VERSION 5.7 ;
  NOWIREEXTENSIONATPIN ON ;
  DIVIDERCHAR "/" ;
  BUSBITCHARS "[]" ;
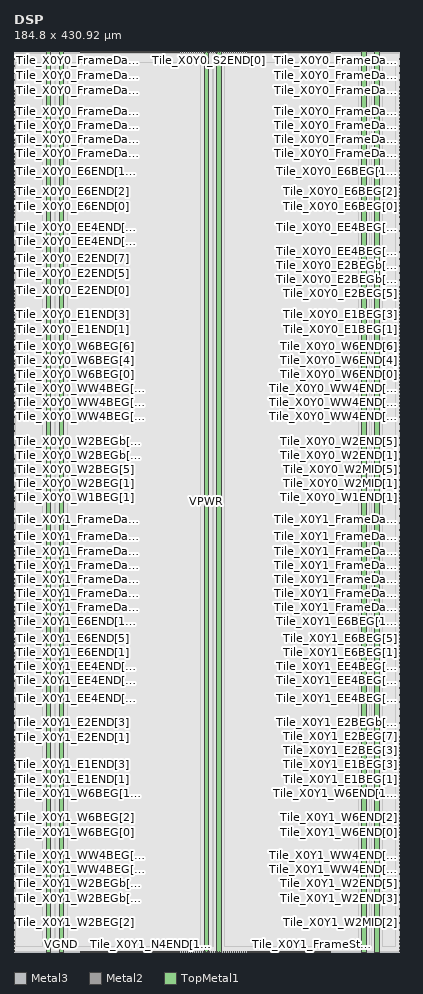
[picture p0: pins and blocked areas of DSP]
MACRO DSP
  CLASS BLOCK ;
  FOREIGN DSP ;
  ORIGIN 0.000 0.000 ;
  SIZE 184.800 BY 430.920 ;
  PIN Tile_X0Y0_E1BEG[0]
    DIRECTION OUTPUT ;
    USE SIGNAL ;
    ANTENNADIFFAREA 0.708600 ;
    PORT
      LAYER Metal3 ;
        RECT 184.400 296.320 184.800 296.720 ;
    END
  END Tile_X0Y0_E1BEG[0]
  PIN Tile_X0Y0_E1BEG[1]
    DIRECTION OUTPUT ;
    USE SIGNAL ;
    ANTENNADIFFAREA 0.708600 ;
    PORT
      LAYER Metal3 ;
        RECT 184.400 298.000 184.800 298.400 ;
    END
  END Tile_X0Y0_E1BEG[1]
  PIN Tile_X0Y0_E1BEG[2]
    DIRECTION OUTPUT ;
    USE SIGNAL ;
    ANTENNADIFFAREA 0.708600 ;
    PORT
      LAYER Metal3 ;
        RECT 184.400 299.680 184.800 300.080 ;
    END
  END Tile_X0Y0_E1BEG[2]
  PIN Tile_X0Y0_E1BEG[3]
    DIRECTION OUTPUT ;
    USE SIGNAL ;
    ANTENNADIFFAREA 0.708600 ;
    PORT
      LAYER Metal3 ;
        RECT 184.400 301.360 184.800 301.760 ;
    END
  END Tile_X0Y0_E1BEG[3]
  PIN Tile_X0Y0_E1END[0]
    DIRECTION INPUT ;
    USE SIGNAL ;
    ANTENNAGATEAREA 0.668200 ;
    PORT
      LAYER Metal3 ;
        RECT 0.000 296.320 0.400 296.720 ;
    END
  END Tile_X0Y0_E1END[0]
  PIN Tile_X0Y0_E1END[1]
    DIRECTION INPUT ;
    USE SIGNAL ;
    ANTENNAGATEAREA 1.834300 ;
    PORT
      LAYER Metal3 ;
        RECT 0.000 298.000 0.400 298.400 ;
    END
  END Tile_X0Y0_E1END[1]
  PIN Tile_X0Y0_E1END[2]
    DIRECTION INPUT ;
    USE SIGNAL ;
    ANTENNAGATEAREA 2.345200 ;
    PORT
      LAYER Metal3 ;
        RECT 0.000 299.680 0.400 300.080 ;
    END
  END Tile_X0Y0_E1END[2]
  PIN Tile_X0Y0_E1END[3]
    DIRECTION INPUT ;
    USE SIGNAL ;
    ANTENNAGATEAREA 1.336400 ;
    PORT
      LAYER Metal3 ;
        RECT 0.000 301.360 0.400 301.760 ;
    END
  END Tile_X0Y0_E1END[3]
  PIN Tile_X0Y0_E2BEG[0]
    DIRECTION OUTPUT ;
    USE SIGNAL ;
    ANTENNADIFFAREA 0.708600 ;
    PORT
      LAYER Metal3 ;
        RECT 184.400 303.040 184.800 303.440 ;
    END
  END Tile_X0Y0_E2BEG[0]
  PIN Tile_X0Y0_E2BEG[1]
    DIRECTION OUTPUT ;
    USE SIGNAL ;
    ANTENNADIFFAREA 0.708600 ;
    PORT
      LAYER Metal3 ;
        RECT 184.400 304.720 184.800 305.120 ;
    END
  END Tile_X0Y0_E2BEG[1]
  PIN Tile_X0Y0_E2BEG[2]
    DIRECTION OUTPUT ;
    USE SIGNAL ;
    ANTENNADIFFAREA 0.708600 ;
    PORT
      LAYER Metal3 ;
        RECT 184.400 306.400 184.800 306.800 ;
    END
  END Tile_X0Y0_E2BEG[2]
  PIN Tile_X0Y0_E2BEG[3]
    DIRECTION OUTPUT ;
    USE SIGNAL ;
    ANTENNADIFFAREA 0.708600 ;
    PORT
      LAYER Metal3 ;
        RECT 184.400 308.080 184.800 308.480 ;
    END
  END Tile_X0Y0_E2BEG[3]
  PIN Tile_X0Y0_E2BEG[4]
    DIRECTION OUTPUT ;
    USE SIGNAL ;
    ANTENNADIFFAREA 0.708600 ;
    PORT
      LAYER Metal3 ;
        RECT 184.400 309.760 184.800 310.160 ;
    END
  END Tile_X0Y0_E2BEG[4]
  PIN Tile_X0Y0_E2BEG[5]
    DIRECTION OUTPUT ;
    USE SIGNAL ;
    ANTENNADIFFAREA 0.708600 ;
    PORT
      LAYER Metal3 ;
        RECT 184.400 311.440 184.800 311.840 ;
    END
  END Tile_X0Y0_E2BEG[5]
  PIN Tile_X0Y0_E2BEG[6]
    DIRECTION OUTPUT ;
    USE SIGNAL ;
    ANTENNADIFFAREA 0.708600 ;
    PORT
      LAYER Metal3 ;
        RECT 184.400 313.120 184.800 313.520 ;
    END
  END Tile_X0Y0_E2BEG[6]
  PIN Tile_X0Y0_E2BEG[7]
    DIRECTION OUTPUT ;
    USE SIGNAL ;
    ANTENNADIFFAREA 0.708600 ;
    PORT
      LAYER Metal3 ;
        RECT 184.400 314.800 184.800 315.200 ;
    END
  END Tile_X0Y0_E2BEG[7]
  PIN Tile_X0Y0_E2BEGb[0]
    DIRECTION OUTPUT ;
    USE SIGNAL ;
    ANTENNADIFFAREA 0.708600 ;
    PORT
      LAYER Metal3 ;
        RECT 184.400 316.480 184.800 316.880 ;
    END
  END Tile_X0Y0_E2BEGb[0]
  PIN Tile_X0Y0_E2BEGb[1]
    DIRECTION OUTPUT ;
    USE SIGNAL ;
    ANTENNADIFFAREA 0.708600 ;
    PORT
      LAYER Metal3 ;
        RECT 184.400 318.160 184.800 318.560 ;
    END
  END Tile_X0Y0_E2BEGb[1]
  PIN Tile_X0Y0_E2BEGb[2]
    DIRECTION OUTPUT ;
    USE SIGNAL ;
    ANTENNADIFFAREA 0.708600 ;
    PORT
      LAYER Metal3 ;
        RECT 184.400 319.840 184.800 320.240 ;
    END
  END Tile_X0Y0_E2BEGb[2]
  PIN Tile_X0Y0_E2BEGb[3]
    DIRECTION OUTPUT ;
    USE SIGNAL ;
    ANTENNADIFFAREA 0.708600 ;
    PORT
      LAYER Metal3 ;
        RECT 184.400 321.520 184.800 321.920 ;
    END
  END Tile_X0Y0_E2BEGb[3]
  PIN Tile_X0Y0_E2BEGb[4]
    DIRECTION OUTPUT ;
    USE SIGNAL ;
    ANTENNADIFFAREA 0.708600 ;
    PORT
      LAYER Metal3 ;
        RECT 184.400 323.200 184.800 323.600 ;
    END
  END Tile_X0Y0_E2BEGb[4]
  PIN Tile_X0Y0_E2BEGb[5]
    DIRECTION OUTPUT ;
    USE SIGNAL ;
    ANTENNADIFFAREA 0.708600 ;
    PORT
      LAYER Metal3 ;
        RECT 184.400 324.880 184.800 325.280 ;
    END
  END Tile_X0Y0_E2BEGb[5]
  PIN Tile_X0Y0_E2BEGb[6]
    DIRECTION OUTPUT ;
    USE SIGNAL ;
    ANTENNADIFFAREA 0.708600 ;
    PORT
      LAYER Metal3 ;
        RECT 184.400 326.560 184.800 326.960 ;
    END
  END Tile_X0Y0_E2BEGb[6]
  PIN Tile_X0Y0_E2BEGb[7]
    DIRECTION OUTPUT ;
    USE SIGNAL ;
    ANTENNADIFFAREA 0.708600 ;
    PORT
      LAYER Metal3 ;
        RECT 184.400 328.240 184.800 328.640 ;
    END
  END Tile_X0Y0_E2BEGb[7]
  PIN Tile_X0Y0_E2END[0]
    DIRECTION INPUT ;
    USE SIGNAL ;
    ANTENNAGATEAREA 0.938600 ;
    PORT
      LAYER Metal3 ;
        RECT 0.000 316.480 0.400 316.880 ;
    END
  END Tile_X0Y0_E2END[0]
  PIN Tile_X0Y0_E2END[1]
    DIRECTION INPUT ;
    USE SIGNAL ;
    ANTENNAGATEAREA 0.894400 ;
    PORT
      LAYER Metal3 ;
        RECT 0.000 318.160 0.400 318.560 ;
    END
  END Tile_X0Y0_E2END[1]
  PIN Tile_X0Y0_E2END[2]
    DIRECTION INPUT ;
    USE SIGNAL ;
    ANTENNAGATEAREA 1.501500 ;
    PORT
      LAYER Metal3 ;
        RECT 0.000 319.840 0.400 320.240 ;
    END
  END Tile_X0Y0_E2END[2]
  PIN Tile_X0Y0_E2END[3]
    DIRECTION INPUT ;
    USE SIGNAL ;
    ANTENNAGATEAREA 1.714700 ;
    PORT
      LAYER Metal3 ;
        RECT 0.000 321.520 0.400 321.920 ;
    END
  END Tile_X0Y0_E2END[3]
  PIN Tile_X0Y0_E2END[4]
    DIRECTION INPUT ;
    USE SIGNAL ;
    ANTENNAGATEAREA 1.066000 ;
    PORT
      LAYER Metal3 ;
        RECT 0.000 323.200 0.400 323.600 ;
    END
  END Tile_X0Y0_E2END[4]
  PIN Tile_X0Y0_E2END[5]
    DIRECTION INPUT ;
    USE SIGNAL ;
    ANTENNAGATEAREA 1.378000 ;
    PORT
      LAYER Metal3 ;
        RECT 0.000 324.880 0.400 325.280 ;
    END
  END Tile_X0Y0_E2END[5]
  PIN Tile_X0Y0_E2END[6]
    DIRECTION INPUT ;
    USE SIGNAL ;
    ANTENNAGATEAREA 1.279200 ;
    PORT
      LAYER Metal3 ;
        RECT 0.000 326.560 0.400 326.960 ;
    END
  END Tile_X0Y0_E2END[6]
  PIN Tile_X0Y0_E2END[7]
    DIRECTION INPUT ;
    USE SIGNAL ;
    ANTENNAGATEAREA 1.180400 ;
    PORT
      LAYER Metal3 ;
        RECT 0.000 328.240 0.400 328.640 ;
    END
  END Tile_X0Y0_E2END[7]
  PIN Tile_X0Y0_E2MID[0]
    DIRECTION INPUT ;
    USE SIGNAL ;
    ANTENNAGATEAREA 0.914700 ;
    PORT
      LAYER Metal3 ;
        RECT 0.000 303.040 0.400 303.440 ;
    END
  END Tile_X0Y0_E2MID[0]
  PIN Tile_X0Y0_E2MID[1]
    DIRECTION INPUT ;
    USE SIGNAL ;
    ANTENNAGATEAREA 0.968500 ;
    PORT
      LAYER Metal3 ;
        RECT 0.000 304.720 0.400 305.120 ;
    END
  END Tile_X0Y0_E2MID[1]
  PIN Tile_X0Y0_E2MID[2]
    DIRECTION INPUT ;
    USE SIGNAL ;
    ANTENNAGATEAREA 0.848900 ;
    PORT
      LAYER Metal3 ;
        RECT 0.000 306.400 0.400 306.800 ;
    END
  END Tile_X0Y0_E2MID[2]
  PIN Tile_X0Y0_E2MID[3]
    DIRECTION INPUT ;
    USE SIGNAL ;
    ANTENNAGATEAREA 1.059500 ;
    PORT
      LAYER Metal3 ;
        RECT 0.000 308.080 0.400 308.480 ;
    END
  END Tile_X0Y0_E2MID[3]
  PIN Tile_X0Y0_E2MID[4]
    DIRECTION INPUT ;
    USE SIGNAL ;
    ANTENNAGATEAREA 1.062100 ;
    PORT
      LAYER Metal3 ;
        RECT 0.000 309.760 0.400 310.160 ;
    END
  END Tile_X0Y0_E2MID[4]
  PIN Tile_X0Y0_E2MID[5]
    DIRECTION INPUT ;
    USE SIGNAL ;
    ANTENNAGATEAREA 1.127900 ;
    PORT
      LAYER Metal3 ;
        RECT 0.000 311.440 0.400 311.840 ;
    END
  END Tile_X0Y0_E2MID[5]
  PIN Tile_X0Y0_E2MID[6]
    DIRECTION INPUT ;
    USE SIGNAL ;
    ANTENNAGATEAREA 0.848900 ;
    PORT
      LAYER Metal3 ;
        RECT 0.000 313.120 0.400 313.520 ;
    END
  END Tile_X0Y0_E2MID[6]
  PIN Tile_X0Y0_E2MID[7]
    DIRECTION INPUT ;
    USE SIGNAL ;
    ANTENNAGATEAREA 1.062100 ;
    PORT
      LAYER Metal3 ;
        RECT 0.000 314.800 0.400 315.200 ;
    END
  END Tile_X0Y0_E2MID[7]
  PIN Tile_X0Y0_E6BEG[0]
    DIRECTION OUTPUT ;
    USE SIGNAL ;
    ANTENNADIFFAREA 0.708600 ;
    PORT
      LAYER Metal3 ;
        RECT 184.400 356.800 184.800 357.200 ;
    END
  END Tile_X0Y0_E6BEG[0]
  PIN Tile_X0Y0_E6BEG[10]
    DIRECTION OUTPUT ;
    USE SIGNAL ;
    ANTENNADIFFAREA 0.708600 ;
    PORT
      LAYER Metal3 ;
        RECT 184.400 373.600 184.800 374.000 ;
    END
  END Tile_X0Y0_E6BEG[10]
  PIN Tile_X0Y0_E6BEG[11]
    DIRECTION OUTPUT ;
    USE SIGNAL ;
    ANTENNADIFFAREA 0.708600 ;
    PORT
      LAYER Metal3 ;
        RECT 184.400 375.280 184.800 375.680 ;
    END
  END Tile_X0Y0_E6BEG[11]
  PIN Tile_X0Y0_E6BEG[1]
    DIRECTION OUTPUT ;
    USE SIGNAL ;
    ANTENNADIFFAREA 0.708600 ;
    PORT
      LAYER Metal3 ;
        RECT 184.400 358.480 184.800 358.880 ;
    END
  END Tile_X0Y0_E6BEG[1]
  PIN Tile_X0Y0_E6BEG[2]
    DIRECTION OUTPUT ;
    USE SIGNAL ;
    ANTENNADIFFAREA 0.708600 ;
    PORT
      LAYER Metal3 ;
        RECT 184.400 360.160 184.800 360.560 ;
    END
  END Tile_X0Y0_E6BEG[2]
  PIN Tile_X0Y0_E6BEG[3]
    DIRECTION OUTPUT ;
    USE SIGNAL ;
    ANTENNADIFFAREA 0.708600 ;
    PORT
      LAYER Metal3 ;
        RECT 184.400 361.840 184.800 362.240 ;
    END
  END Tile_X0Y0_E6BEG[3]
  PIN Tile_X0Y0_E6BEG[4]
    DIRECTION OUTPUT ;
    USE SIGNAL ;
    ANTENNADIFFAREA 0.708600 ;
    PORT
      LAYER Metal3 ;
        RECT 184.400 363.520 184.800 363.920 ;
    END
  END Tile_X0Y0_E6BEG[4]
  PIN Tile_X0Y0_E6BEG[5]
    DIRECTION OUTPUT ;
    USE SIGNAL ;
    ANTENNADIFFAREA 0.708600 ;
    PORT
      LAYER Metal3 ;
        RECT 184.400 365.200 184.800 365.600 ;
    END
  END Tile_X0Y0_E6BEG[5]
  PIN Tile_X0Y0_E6BEG[6]
    DIRECTION OUTPUT ;
    USE SIGNAL ;
    ANTENNADIFFAREA 0.708600 ;
    PORT
      LAYER Metal3 ;
        RECT 184.400 366.880 184.800 367.280 ;
    END
  END Tile_X0Y0_E6BEG[6]
  PIN Tile_X0Y0_E6BEG[7]
    DIRECTION OUTPUT ;
    USE SIGNAL ;
    ANTENNADIFFAREA 0.708600 ;
    PORT
      LAYER Metal3 ;
        RECT 184.400 368.560 184.800 368.960 ;
    END
  END Tile_X0Y0_E6BEG[7]
  PIN Tile_X0Y0_E6BEG[8]
    DIRECTION OUTPUT ;
    USE SIGNAL ;
    ANTENNADIFFAREA 0.708600 ;
    PORT
      LAYER Metal3 ;
        RECT 184.400 370.240 184.800 370.640 ;
    END
  END Tile_X0Y0_E6BEG[8]
  PIN Tile_X0Y0_E6BEG[9]
    DIRECTION OUTPUT ;
    USE SIGNAL ;
    ANTENNADIFFAREA 0.708600 ;
    PORT
      LAYER Metal3 ;
        RECT 184.400 371.920 184.800 372.320 ;
    END
  END Tile_X0Y0_E6BEG[9]
  PIN Tile_X0Y0_E6END[0]
    DIRECTION INPUT ;
    USE SIGNAL ;
    ANTENNAGATEAREA 2.567500 ;
    PORT
      LAYER Metal3 ;
        RECT 0.000 356.800 0.400 357.200 ;
    END
  END Tile_X0Y0_E6END[0]
  PIN Tile_X0Y0_E6END[10]
    DIRECTION INPUT ;
    USE SIGNAL ;
    ANTENNAGATEAREA 0.789100 ;
    ANTENNADIFFAREA 2.015400 ;
    PORT
      LAYER Metal3 ;
        RECT 0.000 373.600 0.400 374.000 ;
    END
  END Tile_X0Y0_E6END[10]
  PIN Tile_X0Y0_E6END[11]
    DIRECTION INPUT ;
    USE SIGNAL ;
    ANTENNAGATEAREA 0.180700 ;
    PORT
      LAYER Metal3 ;
        RECT 0.000 375.280 0.400 375.680 ;
    END
  END Tile_X0Y0_E6END[11]
  PIN Tile_X0Y0_E6END[1]
    DIRECTION INPUT ;
    USE SIGNAL ;
    ANTENNAGATEAREA 2.764900 ;
    PORT
      LAYER Metal3 ;
        RECT 0.000 358.480 0.400 358.880 ;
    END
  END Tile_X0Y0_E6END[1]
  PIN Tile_X0Y0_E6END[2]
    DIRECTION INPUT ;
    USE SIGNAL ;
    ANTENNAGATEAREA 0.180700 ;
    PORT
      LAYER Metal3 ;
        RECT 0.000 360.160 0.400 360.560 ;
    END
  END Tile_X0Y0_E6END[2]
  PIN Tile_X0Y0_E6END[3]
    DIRECTION INPUT ;
    USE SIGNAL ;
    ANTENNAGATEAREA 0.789100 ;
    ANTENNADIFFAREA 2.015400 ;
    PORT
      LAYER Metal3 ;
        RECT 0.000 361.840 0.400 362.240 ;
    END
  END Tile_X0Y0_E6END[3]
  PIN Tile_X0Y0_E6END[4]
    DIRECTION INPUT ;
    USE SIGNAL ;
    ANTENNAGATEAREA 0.789100 ;
    ANTENNADIFFAREA 2.015400 ;
    PORT
      LAYER Metal3 ;
        RECT 0.000 363.520 0.400 363.920 ;
    END
  END Tile_X0Y0_E6END[4]
  PIN Tile_X0Y0_E6END[5]
    DIRECTION INPUT ;
    USE SIGNAL ;
    ANTENNAGATEAREA 0.180700 ;
    PORT
      LAYER Metal3 ;
        RECT 0.000 365.200 0.400 365.600 ;
    END
  END Tile_X0Y0_E6END[5]
  PIN Tile_X0Y0_E6END[6]
    DIRECTION INPUT ;
    USE SIGNAL ;
    ANTENNAGATEAREA 0.789100 ;
    ANTENNADIFFAREA 2.015400 ;
    PORT
      LAYER Metal3 ;
        RECT 0.000 366.880 0.400 367.280 ;
    END
  END Tile_X0Y0_E6END[6]
  PIN Tile_X0Y0_E6END[7]
    DIRECTION INPUT ;
    USE SIGNAL ;
    ANTENNAGATEAREA 0.180700 ;
    PORT
      LAYER Metal3 ;
        RECT 0.000 368.560 0.400 368.960 ;
    END
  END Tile_X0Y0_E6END[7]
  PIN Tile_X0Y0_E6END[8]
    DIRECTION INPUT ;
    USE SIGNAL ;
    ANTENNAGATEAREA 0.180700 ;
    PORT
      LAYER Metal3 ;
        RECT 0.000 370.240 0.400 370.640 ;
    END
  END Tile_X0Y0_E6END[8]
  PIN Tile_X0Y0_E6END[9]
    DIRECTION INPUT ;
    USE SIGNAL ;
    ANTENNAGATEAREA 0.180700 ;
    PORT
      LAYER Metal3 ;
        RECT 0.000 371.920 0.400 372.320 ;
    END
  END Tile_X0Y0_E6END[9]
  PIN Tile_X0Y0_EE4BEG[0]
    DIRECTION OUTPUT ;
    USE SIGNAL ;
    ANTENNADIFFAREA 0.708600 ;
    PORT
      LAYER Metal3 ;
        RECT 184.400 329.920 184.800 330.320 ;
    END
  END Tile_X0Y0_EE4BEG[0]
  PIN Tile_X0Y0_EE4BEG[10]
    DIRECTION OUTPUT ;
    USE SIGNAL ;
    ANTENNADIFFAREA 0.708600 ;
    PORT
      LAYER Metal3 ;
        RECT 184.400 346.720 184.800 347.120 ;
    END
  END Tile_X0Y0_EE4BEG[10]
  PIN Tile_X0Y0_EE4BEG[11]
    DIRECTION OUTPUT ;
    USE SIGNAL ;
    ANTENNADIFFAREA 0.708600 ;
    PORT
      LAYER Metal3 ;
        RECT 184.400 348.400 184.800 348.800 ;
    END
  END Tile_X0Y0_EE4BEG[11]
  PIN Tile_X0Y0_EE4BEG[12]
    DIRECTION OUTPUT ;
    USE SIGNAL ;
    ANTENNADIFFAREA 0.708600 ;
    PORT
      LAYER Metal3 ;
        RECT 184.400 350.080 184.800 350.480 ;
    END
  END Tile_X0Y0_EE4BEG[12]
  PIN Tile_X0Y0_EE4BEG[13]
    DIRECTION OUTPUT ;
    USE SIGNAL ;
    ANTENNADIFFAREA 0.708600 ;
    PORT
      LAYER Metal3 ;
        RECT 184.400 351.760 184.800 352.160 ;
    END
  END Tile_X0Y0_EE4BEG[13]
  PIN Tile_X0Y0_EE4BEG[14]
    DIRECTION OUTPUT ;
    USE SIGNAL ;
    ANTENNADIFFAREA 0.708600 ;
    PORT
      LAYER Metal3 ;
        RECT 184.400 353.440 184.800 353.840 ;
    END
  END Tile_X0Y0_EE4BEG[14]
  PIN Tile_X0Y0_EE4BEG[15]
    DIRECTION OUTPUT ;
    USE SIGNAL ;
    ANTENNADIFFAREA 0.708600 ;
    PORT
      LAYER Metal3 ;
        RECT 184.400 355.120 184.800 355.520 ;
    END
  END Tile_X0Y0_EE4BEG[15]
  PIN Tile_X0Y0_EE4BEG[1]
    DIRECTION OUTPUT ;
    USE SIGNAL ;
    ANTENNADIFFAREA 0.708600 ;
    PORT
      LAYER Metal3 ;
        RECT 184.400 331.600 184.800 332.000 ;
    END
  END Tile_X0Y0_EE4BEG[1]
  PIN Tile_X0Y0_EE4BEG[2]
    DIRECTION OUTPUT ;
    USE SIGNAL ;
    ANTENNADIFFAREA 0.708600 ;
    PORT
      LAYER Metal3 ;
        RECT 184.400 333.280 184.800 333.680 ;
    END
  END Tile_X0Y0_EE4BEG[2]
  PIN Tile_X0Y0_EE4BEG[3]
    DIRECTION OUTPUT ;
    USE SIGNAL ;
    ANTENNADIFFAREA 0.708600 ;
    PORT
      LAYER Metal3 ;
        RECT 184.400 334.960 184.800 335.360 ;
    END
  END Tile_X0Y0_EE4BEG[3]
  PIN Tile_X0Y0_EE4BEG[4]
    DIRECTION OUTPUT ;
    USE SIGNAL ;
    ANTENNADIFFAREA 0.708600 ;
    PORT
      LAYER Metal3 ;
        RECT 184.400 336.640 184.800 337.040 ;
    END
  END Tile_X0Y0_EE4BEG[4]
  PIN Tile_X0Y0_EE4BEG[5]
    DIRECTION OUTPUT ;
    USE SIGNAL ;
    ANTENNADIFFAREA 0.708600 ;
    PORT
      LAYER Metal3 ;
        RECT 184.400 338.320 184.800 338.720 ;
    END
  END Tile_X0Y0_EE4BEG[5]
  PIN Tile_X0Y0_EE4BEG[6]
    DIRECTION OUTPUT ;
    USE SIGNAL ;
    ANTENNADIFFAREA 0.708600 ;
    PORT
      LAYER Metal3 ;
        RECT 184.400 340.000 184.800 340.400 ;
    END
  END Tile_X0Y0_EE4BEG[6]
  PIN Tile_X0Y0_EE4BEG[7]
    DIRECTION OUTPUT ;
    USE SIGNAL ;
    ANTENNADIFFAREA 0.708600 ;
    PORT
      LAYER Metal3 ;
        RECT 184.400 341.680 184.800 342.080 ;
    END
  END Tile_X0Y0_EE4BEG[7]
  PIN Tile_X0Y0_EE4BEG[8]
    DIRECTION OUTPUT ;
    USE SIGNAL ;
    ANTENNADIFFAREA 0.708600 ;
    PORT
      LAYER Metal3 ;
        RECT 184.400 343.360 184.800 343.760 ;
    END
  END Tile_X0Y0_EE4BEG[8]
  PIN Tile_X0Y0_EE4BEG[9]
    DIRECTION OUTPUT ;
    USE SIGNAL ;
    ANTENNADIFFAREA 0.708600 ;
    PORT
      LAYER Metal3 ;
        RECT 184.400 345.040 184.800 345.440 ;
    END
  END Tile_X0Y0_EE4BEG[9]
  PIN Tile_X0Y0_EE4END[0]
    DIRECTION INPUT ;
    USE SIGNAL ;
    ANTENNAGATEAREA 0.696800 ;
    PORT
      LAYER Metal3 ;
        RECT 0.000 329.920 0.400 330.320 ;
    END
  END Tile_X0Y0_EE4END[0]
  PIN Tile_X0Y0_EE4END[10]
    DIRECTION INPUT ;
    USE SIGNAL ;
    ANTENNAGATEAREA 0.789100 ;
    ANTENNADIFFAREA 2.015400 ;
    PORT
      LAYER Metal3 ;
        RECT 0.000 346.720 0.400 347.120 ;
    END
  END Tile_X0Y0_EE4END[10]
  PIN Tile_X0Y0_EE4END[11]
    DIRECTION INPUT ;
    USE SIGNAL ;
    ANTENNAGATEAREA 0.789100 ;
    ANTENNADIFFAREA 2.015400 ;
    PORT
      LAYER Metal3 ;
        RECT 0.000 348.400 0.400 348.800 ;
    END
  END Tile_X0Y0_EE4END[11]
  PIN Tile_X0Y0_EE4END[12]
    DIRECTION INPUT ;
    USE SIGNAL ;
    ANTENNAGATEAREA 0.789100 ;
    ANTENNADIFFAREA 2.015400 ;
    PORT
      LAYER Metal3 ;
        RECT 0.000 350.080 0.400 350.480 ;
    END
  END Tile_X0Y0_EE4END[12]
  PIN Tile_X0Y0_EE4END[13]
    DIRECTION INPUT ;
    USE SIGNAL ;
    ANTENNAGATEAREA 0.789100 ;
    ANTENNADIFFAREA 2.015400 ;
    PORT
      LAYER Metal3 ;
        RECT 0.000 351.760 0.400 352.160 ;
    END
  END Tile_X0Y0_EE4END[13]
  PIN Tile_X0Y0_EE4END[14]
    DIRECTION INPUT ;
    USE SIGNAL ;
    ANTENNAGATEAREA 0.789100 ;
    ANTENNADIFFAREA 2.015400 ;
    PORT
      LAYER Metal3 ;
        RECT 0.000 353.440 0.400 353.840 ;
    END
  END Tile_X0Y0_EE4END[14]
  PIN Tile_X0Y0_EE4END[15]
    DIRECTION INPUT ;
    USE SIGNAL ;
    ANTENNAGATEAREA 0.180700 ;
    PORT
      LAYER Metal3 ;
        RECT 0.000 355.120 0.400 355.520 ;
    END
  END Tile_X0Y0_EE4END[15]
  PIN Tile_X0Y0_EE4END[1]
    DIRECTION INPUT ;
    USE SIGNAL ;
    ANTENNAGATEAREA 0.681200 ;
    PORT
      LAYER Metal3 ;
        RECT 0.000 331.600 0.400 332.000 ;
    END
  END Tile_X0Y0_EE4END[1]
  PIN Tile_X0Y0_EE4END[2]
    DIRECTION INPUT ;
    USE SIGNAL ;
    ANTENNAGATEAREA 0.705400 ;
    PORT
      LAYER Metal3 ;
        RECT 0.000 333.280 0.400 333.680 ;
    END
  END Tile_X0Y0_EE4END[2]
  PIN Tile_X0Y0_EE4END[3]
    DIRECTION INPUT ;
    USE SIGNAL ;
    ANTENNAGATEAREA 0.393900 ;
    PORT
      LAYER Metal3 ;
        RECT 0.000 334.960 0.400 335.360 ;
    END
  END Tile_X0Y0_EE4END[3]
  PIN Tile_X0Y0_EE4END[4]
    DIRECTION INPUT ;
    USE SIGNAL ;
    ANTENNAGATEAREA 0.180700 ;
    PORT
      LAYER Metal3 ;
        RECT 0.000 336.640 0.400 337.040 ;
    END
  END Tile_X0Y0_EE4END[4]
  PIN Tile_X0Y0_EE4END[5]
    DIRECTION INPUT ;
    USE SIGNAL ;
    ANTENNAGATEAREA 0.789100 ;
    ANTENNADIFFAREA 2.015400 ;
    PORT
      LAYER Metal3 ;
        RECT 0.000 338.320 0.400 338.720 ;
    END
  END Tile_X0Y0_EE4END[5]
  PIN Tile_X0Y0_EE4END[6]
    DIRECTION INPUT ;
    USE SIGNAL ;
    ANTENNAGATEAREA 0.789100 ;
    ANTENNADIFFAREA 2.015400 ;
    PORT
      LAYER Metal3 ;
        RECT 0.000 340.000 0.400 340.400 ;
    END
  END Tile_X0Y0_EE4END[6]
  PIN Tile_X0Y0_EE4END[7]
    DIRECTION INPUT ;
    USE SIGNAL ;
    ANTENNAGATEAREA 0.180700 ;
    PORT
      LAYER Metal3 ;
        RECT 0.000 341.680 0.400 342.080 ;
    END
  END Tile_X0Y0_EE4END[7]
  PIN Tile_X0Y0_EE4END[8]
    DIRECTION INPUT ;
    USE SIGNAL ;
    ANTENNAGATEAREA 0.789100 ;
    ANTENNADIFFAREA 2.015400 ;
    PORT
      LAYER Metal3 ;
        RECT 0.000 343.360 0.400 343.760 ;
    END
  END Tile_X0Y0_EE4END[8]
  PIN Tile_X0Y0_EE4END[9]
    DIRECTION INPUT ;
    USE SIGNAL ;
    ANTENNAGATEAREA 0.180700 ;
    PORT
      LAYER Metal3 ;
        RECT 0.000 345.040 0.400 345.440 ;
    END
  END Tile_X0Y0_EE4END[9]
  PIN Tile_X0Y0_FrameData[0]
    DIRECTION INPUT ;
    USE SIGNAL ;
    ANTENNAGATEAREA 2.349100 ;
    PORT
      LAYER Metal3 ;
        RECT 0.000 376.960 0.400 377.360 ;
    END
  END Tile_X0Y0_FrameData[0]
  PIN Tile_X0Y0_FrameData[10]
    DIRECTION INPUT ;
    USE SIGNAL ;
    ANTENNAGATEAREA 2.529800 ;
    PORT
      LAYER Metal3 ;
        RECT 0.000 393.760 0.400 394.160 ;
    END
  END Tile_X0Y0_FrameData[10]
  PIN Tile_X0Y0_FrameData[11]
    DIRECTION INPUT ;
    USE SIGNAL ;
    ANTENNAGATEAREA 2.529800 ;
    PORT
      LAYER Metal3 ;
        RECT 0.000 395.440 0.400 395.840 ;
    END
  END Tile_X0Y0_FrameData[11]
  PIN Tile_X0Y0_FrameData[12]
    DIRECTION INPUT ;
    USE SIGNAL ;
    ANTENNAGATEAREA 2.529800 ;
    PORT
      LAYER Metal3 ;
        RECT 0.000 397.120 0.400 397.520 ;
    END
  END Tile_X0Y0_FrameData[12]
  PIN Tile_X0Y0_FrameData[13]
    DIRECTION INPUT ;
    USE SIGNAL ;
    ANTENNAGATEAREA 2.529800 ;
    PORT
      LAYER Metal3 ;
        RECT 0.000 398.800 0.400 399.200 ;
    END
  END Tile_X0Y0_FrameData[13]
  PIN Tile_X0Y0_FrameData[14]
    DIRECTION INPUT ;
    USE SIGNAL ;
    ANTENNAGATEAREA 2.529800 ;
    PORT
      LAYER Metal3 ;
        RECT 0.000 400.480 0.400 400.880 ;
    END
  END Tile_X0Y0_FrameData[14]
  PIN Tile_X0Y0_FrameData[15]
    DIRECTION INPUT ;
    USE SIGNAL ;
    ANTENNAGATEAREA 2.529800 ;
    PORT
      LAYER Metal3 ;
        RECT 0.000 402.160 0.400 402.560 ;
    END
  END Tile_X0Y0_FrameData[15]
  PIN Tile_X0Y0_FrameData[16]
    DIRECTION INPUT ;
    USE SIGNAL ;
    ANTENNAGATEAREA 2.529800 ;
    PORT
      LAYER Metal3 ;
        RECT 0.000 403.840 0.400 404.240 ;
    END
  END Tile_X0Y0_FrameData[16]
  PIN Tile_X0Y0_FrameData[17]
    DIRECTION INPUT ;
    USE SIGNAL ;
    ANTENNAGATEAREA 2.529800 ;
    PORT
      LAYER Metal3 ;
        RECT 0.000 405.520 0.400 405.920 ;
    END
  END Tile_X0Y0_FrameData[17]
  PIN Tile_X0Y0_FrameData[18]
    DIRECTION INPUT ;
    USE SIGNAL ;
    ANTENNAGATEAREA 2.529800 ;
    PORT
      LAYER Metal3 ;
        RECT 0.000 407.200 0.400 407.600 ;
    END
  END Tile_X0Y0_FrameData[18]
  PIN Tile_X0Y0_FrameData[19]
    DIRECTION INPUT ;
    USE SIGNAL ;
    ANTENNAGATEAREA 2.529800 ;
    PORT
      LAYER Metal3 ;
        RECT 0.000 408.880 0.400 409.280 ;
    END
  END Tile_X0Y0_FrameData[19]
  PIN Tile_X0Y0_FrameData[1]
    DIRECTION INPUT ;
    USE SIGNAL ;
    ANTENNAGATEAREA 2.349100 ;
    PORT
      LAYER Metal3 ;
        RECT 0.000 378.640 0.400 379.040 ;
    END
  END Tile_X0Y0_FrameData[1]
  PIN Tile_X0Y0_FrameData[20]
    DIRECTION INPUT ;
    USE SIGNAL ;
    ANTENNAGATEAREA 2.529800 ;
    PORT
      LAYER Metal3 ;
        RECT 0.000 410.560 0.400 410.960 ;
    END
  END Tile_X0Y0_FrameData[20]
  PIN Tile_X0Y0_FrameData[21]
    DIRECTION INPUT ;
    USE SIGNAL ;
    ANTENNAGATEAREA 2.529800 ;
    PORT
      LAYER Metal3 ;
        RECT 0.000 412.240 0.400 412.640 ;
    END
  END Tile_X0Y0_FrameData[21]
  PIN Tile_X0Y0_FrameData[22]
    DIRECTION INPUT ;
    USE SIGNAL ;
    ANTENNAGATEAREA 2.529800 ;
    PORT
      LAYER Metal3 ;
        RECT 0.000 413.920 0.400 414.320 ;
    END
  END Tile_X0Y0_FrameData[22]
  PIN Tile_X0Y0_FrameData[23]
    DIRECTION INPUT ;
    USE SIGNAL ;
    ANTENNAGATEAREA 2.529800 ;
    PORT
      LAYER Metal3 ;
        RECT 0.000 415.600 0.400 416.000 ;
    END
  END Tile_X0Y0_FrameData[23]
  PIN Tile_X0Y0_FrameData[24]
    DIRECTION INPUT ;
    USE SIGNAL ;
    ANTENNAGATEAREA 2.529800 ;
    PORT
      LAYER Metal3 ;
        RECT 0.000 417.280 0.400 417.680 ;
    END
  END Tile_X0Y0_FrameData[24]
  PIN Tile_X0Y0_FrameData[25]
    DIRECTION INPUT ;
    USE SIGNAL ;
    ANTENNAGATEAREA 2.529800 ;
    PORT
      LAYER Metal3 ;
        RECT 0.000 418.960 0.400 419.360 ;
    END
  END Tile_X0Y0_FrameData[25]
  PIN Tile_X0Y0_FrameData[26]
    DIRECTION INPUT ;
    USE SIGNAL ;
    ANTENNAGATEAREA 2.529800 ;
    PORT
      LAYER Metal3 ;
        RECT 0.000 420.640 0.400 421.040 ;
    END
  END Tile_X0Y0_FrameData[26]
  PIN Tile_X0Y0_FrameData[27]
    DIRECTION INPUT ;
    USE SIGNAL ;
    ANTENNAGATEAREA 2.529800 ;
    PORT
      LAYER Metal3 ;
        RECT 0.000 422.320 0.400 422.720 ;
    END
  END Tile_X0Y0_FrameData[27]
  PIN Tile_X0Y0_FrameData[28]
    DIRECTION INPUT ;
    USE SIGNAL ;
    ANTENNAGATEAREA 2.529800 ;
    PORT
      LAYER Metal3 ;
        RECT 0.000 424.000 0.400 424.400 ;
    END
  END Tile_X0Y0_FrameData[28]
  PIN Tile_X0Y0_FrameData[29]
    DIRECTION INPUT ;
    USE SIGNAL ;
    ANTENNAGATEAREA 2.529800 ;
    PORT
      LAYER Metal3 ;
        RECT 0.000 425.680 0.400 426.080 ;
    END
  END Tile_X0Y0_FrameData[29]
  PIN Tile_X0Y0_FrameData[2]
    DIRECTION INPUT ;
    USE SIGNAL ;
    ANTENNAGATEAREA 2.349100 ;
    PORT
      LAYER Metal3 ;
        RECT 0.000 380.320 0.400 380.720 ;
    END
  END Tile_X0Y0_FrameData[2]
  PIN Tile_X0Y0_FrameData[30]
    DIRECTION INPUT ;
    USE SIGNAL ;
    ANTENNAGATEAREA 2.529800 ;
    PORT
      LAYER Metal3 ;
        RECT 0.000 427.360 0.400 427.760 ;
    END
  END Tile_X0Y0_FrameData[30]
  PIN Tile_X0Y0_FrameData[31]
    DIRECTION INPUT ;
    USE SIGNAL ;
    ANTENNAGATEAREA 2.529800 ;
    PORT
      LAYER Metal3 ;
        RECT 0.000 429.040 0.400 429.440 ;
    END
  END Tile_X0Y0_FrameData[31]
  PIN Tile_X0Y0_FrameData[3]
    DIRECTION INPUT ;
    USE SIGNAL ;
    ANTENNAGATEAREA 2.349100 ;
    PORT
      LAYER Metal3 ;
        RECT 0.000 382.000 0.400 382.400 ;
    END
  END Tile_X0Y0_FrameData[3]
  PIN Tile_X0Y0_FrameData[4]
    DIRECTION INPUT ;
    USE SIGNAL ;
    ANTENNAGATEAREA 2.349100 ;
    PORT
      LAYER Metal3 ;
        RECT 0.000 383.680 0.400 384.080 ;
    END
  END Tile_X0Y0_FrameData[4]
  PIN Tile_X0Y0_FrameData[5]
    DIRECTION INPUT ;
    USE SIGNAL ;
    ANTENNAGATEAREA 2.349100 ;
    PORT
      LAYER Metal3 ;
        RECT 0.000 385.360 0.400 385.760 ;
    END
  END Tile_X0Y0_FrameData[5]
  PIN Tile_X0Y0_FrameData[6]
    DIRECTION INPUT ;
    USE SIGNAL ;
    ANTENNAGATEAREA 2.349100 ;
    PORT
      LAYER Metal3 ;
        RECT 0.000 387.040 0.400 387.440 ;
    END
  END Tile_X0Y0_FrameData[6]
  PIN Tile_X0Y0_FrameData[7]
    DIRECTION INPUT ;
    USE SIGNAL ;
    ANTENNAGATEAREA 2.349100 ;
    PORT
      LAYER Metal3 ;
        RECT 0.000 388.720 0.400 389.120 ;
    END
  END Tile_X0Y0_FrameData[7]
  PIN Tile_X0Y0_FrameData[8]
    DIRECTION INPUT ;
    USE SIGNAL ;
    ANTENNAGATEAREA 2.349100 ;
    PORT
      LAYER Metal3 ;
        RECT 0.000 390.400 0.400 390.800 ;
    END
  END Tile_X0Y0_FrameData[8]
  PIN Tile_X0Y0_FrameData[9]
    DIRECTION INPUT ;
    USE SIGNAL ;
    ANTENNAGATEAREA 2.349100 ;
    PORT
      LAYER Metal3 ;
        RECT 0.000 392.080 0.400 392.480 ;
    END
  END Tile_X0Y0_FrameData[9]
  PIN Tile_X0Y0_FrameData_O[0]
    DIRECTION OUTPUT ;
    USE SIGNAL ;
    ANTENNADIFFAREA 0.708600 ;
    PORT
      LAYER Metal3 ;
        RECT 184.400 376.960 184.800 377.360 ;
    END
  END Tile_X0Y0_FrameData_O[0]
  PIN Tile_X0Y0_FrameData_O[10]
    DIRECTION OUTPUT ;
    USE SIGNAL ;
    ANTENNADIFFAREA 0.708600 ;
    PORT
      LAYER Metal3 ;
        RECT 184.400 393.760 184.800 394.160 ;
    END
  END Tile_X0Y0_FrameData_O[10]
  PIN Tile_X0Y0_FrameData_O[11]
    DIRECTION OUTPUT ;
    USE SIGNAL ;
    ANTENNADIFFAREA 0.708600 ;
    PORT
      LAYER Metal3 ;
        RECT 184.400 395.440 184.800 395.840 ;
    END
  END Tile_X0Y0_FrameData_O[11]
  PIN Tile_X0Y0_FrameData_O[12]
    DIRECTION OUTPUT ;
    USE SIGNAL ;
    ANTENNADIFFAREA 0.708600 ;
    PORT
      LAYER Metal3 ;
        RECT 184.400 397.120 184.800 397.520 ;
    END
  END Tile_X0Y0_FrameData_O[12]
  PIN Tile_X0Y0_FrameData_O[13]
    DIRECTION OUTPUT ;
    USE SIGNAL ;
    ANTENNADIFFAREA 0.708600 ;
    PORT
      LAYER Metal3 ;
        RECT 184.400 398.800 184.800 399.200 ;
    END
  END Tile_X0Y0_FrameData_O[13]
  PIN Tile_X0Y0_FrameData_O[14]
    DIRECTION OUTPUT ;
    USE SIGNAL ;
    ANTENNADIFFAREA 0.708600 ;
    PORT
      LAYER Metal3 ;
        RECT 184.400 400.480 184.800 400.880 ;
    END
  END Tile_X0Y0_FrameData_O[14]
  PIN Tile_X0Y0_FrameData_O[15]
    DIRECTION OUTPUT ;
    USE SIGNAL ;
    ANTENNADIFFAREA 0.708600 ;
    PORT
      LAYER Metal3 ;
        RECT 184.400 402.160 184.800 402.560 ;
    END
  END Tile_X0Y0_FrameData_O[15]
  PIN Tile_X0Y0_FrameData_O[16]
    DIRECTION OUTPUT ;
    USE SIGNAL ;
    ANTENNADIFFAREA 0.708600 ;
    PORT
      LAYER Metal3 ;
        RECT 184.400 403.840 184.800 404.240 ;
    END
  END Tile_X0Y0_FrameData_O[16]
  PIN Tile_X0Y0_FrameData_O[17]
    DIRECTION OUTPUT ;
    USE SIGNAL ;
    ANTENNADIFFAREA 0.708600 ;
    PORT
      LAYER Metal3 ;
        RECT 184.400 405.520 184.800 405.920 ;
    END
  END Tile_X0Y0_FrameData_O[17]
  PIN Tile_X0Y0_FrameData_O[18]
    DIRECTION OUTPUT ;
    USE SIGNAL ;
    ANTENNADIFFAREA 0.708600 ;
    PORT
      LAYER Metal3 ;
        RECT 184.400 407.200 184.800 407.600 ;
    END
  END Tile_X0Y0_FrameData_O[18]
  PIN Tile_X0Y0_FrameData_O[19]
    DIRECTION OUTPUT ;
    USE SIGNAL ;
    ANTENNADIFFAREA 0.708600 ;
    PORT
      LAYER Metal3 ;
        RECT 184.400 408.880 184.800 409.280 ;
    END
  END Tile_X0Y0_FrameData_O[19]
  PIN Tile_X0Y0_FrameData_O[1]
    DIRECTION OUTPUT ;
    USE SIGNAL ;
    ANTENNADIFFAREA 0.708600 ;
    PORT
      LAYER Metal3 ;
        RECT 184.400 378.640 184.800 379.040 ;
    END
  END Tile_X0Y0_FrameData_O[1]
  PIN Tile_X0Y0_FrameData_O[20]
    DIRECTION OUTPUT ;
    USE SIGNAL ;
    ANTENNADIFFAREA 0.708600 ;
    PORT
      LAYER Metal3 ;
        RECT 184.400 410.560 184.800 410.960 ;
    END
  END Tile_X0Y0_FrameData_O[20]
  PIN Tile_X0Y0_FrameData_O[21]
    DIRECTION OUTPUT ;
    USE SIGNAL ;
    ANTENNADIFFAREA 0.708600 ;
    PORT
      LAYER Metal3 ;
        RECT 184.400 412.240 184.800 412.640 ;
    END
  END Tile_X0Y0_FrameData_O[21]
  PIN Tile_X0Y0_FrameData_O[22]
    DIRECTION OUTPUT ;
    USE SIGNAL ;
    ANTENNADIFFAREA 0.708600 ;
    PORT
      LAYER Metal3 ;
        RECT 184.400 413.920 184.800 414.320 ;
    END
  END Tile_X0Y0_FrameData_O[22]
  PIN Tile_X0Y0_FrameData_O[23]
    DIRECTION OUTPUT ;
    USE SIGNAL ;
    ANTENNADIFFAREA 0.708600 ;
    PORT
      LAYER Metal3 ;
        RECT 184.400 415.600 184.800 416.000 ;
    END
  END Tile_X0Y0_FrameData_O[23]
  PIN Tile_X0Y0_FrameData_O[24]
    DIRECTION OUTPUT ;
    USE SIGNAL ;
    ANTENNADIFFAREA 0.708600 ;
    PORT
      LAYER Metal3 ;
        RECT 184.400 417.280 184.800 417.680 ;
    END
  END Tile_X0Y0_FrameData_O[24]
  PIN Tile_X0Y0_FrameData_O[25]
    DIRECTION OUTPUT ;
    USE SIGNAL ;
    ANTENNADIFFAREA 0.708600 ;
    PORT
      LAYER Metal3 ;
        RECT 184.400 418.960 184.800 419.360 ;
    END
  END Tile_X0Y0_FrameData_O[25]
  PIN Tile_X0Y0_FrameData_O[26]
    DIRECTION OUTPUT ;
    USE SIGNAL ;
    ANTENNADIFFAREA 0.708600 ;
    PORT
      LAYER Metal3 ;
        RECT 184.400 420.640 184.800 421.040 ;
    END
  END Tile_X0Y0_FrameData_O[26]
  PIN Tile_X0Y0_FrameData_O[27]
    DIRECTION OUTPUT ;
    USE SIGNAL ;
    ANTENNADIFFAREA 0.708600 ;
    PORT
      LAYER Metal3 ;
        RECT 184.400 422.320 184.800 422.720 ;
    END
  END Tile_X0Y0_FrameData_O[27]
  PIN Tile_X0Y0_FrameData_O[28]
    DIRECTION OUTPUT ;
    USE SIGNAL ;
    ANTENNADIFFAREA 0.708600 ;
    PORT
      LAYER Metal3 ;
        RECT 184.400 424.000 184.800 424.400 ;
    END
  END Tile_X0Y0_FrameData_O[28]
  PIN Tile_X0Y0_FrameData_O[29]
    DIRECTION OUTPUT ;
    USE SIGNAL ;
    ANTENNADIFFAREA 0.708600 ;
    PORT
      LAYER Metal3 ;
        RECT 184.400 425.680 184.800 426.080 ;
    END
  END Tile_X0Y0_FrameData_O[29]
  PIN Tile_X0Y0_FrameData_O[2]
    DIRECTION OUTPUT ;
    USE SIGNAL ;
    ANTENNADIFFAREA 0.708600 ;
    PORT
      LAYER Metal3 ;
        RECT 184.400 380.320 184.800 380.720 ;
    END
  END Tile_X0Y0_FrameData_O[2]
  PIN Tile_X0Y0_FrameData_O[30]
    DIRECTION OUTPUT ;
    USE SIGNAL ;
    ANTENNADIFFAREA 0.708600 ;
    PORT
      LAYER Metal3 ;
        RECT 184.400 427.360 184.800 427.760 ;
    END
  END Tile_X0Y0_FrameData_O[30]
  PIN Tile_X0Y0_FrameData_O[31]
    DIRECTION OUTPUT ;
    USE SIGNAL ;
    ANTENNADIFFAREA 0.708600 ;
    PORT
      LAYER Metal3 ;
        RECT 184.400 429.040 184.800 429.440 ;
    END
  END Tile_X0Y0_FrameData_O[31]
  PIN Tile_X0Y0_FrameData_O[3]
    DIRECTION OUTPUT ;
    USE SIGNAL ;
    ANTENNADIFFAREA 0.708600 ;
    PORT
      LAYER Metal3 ;
        RECT 184.400 382.000 184.800 382.400 ;
    END
  END Tile_X0Y0_FrameData_O[3]
  PIN Tile_X0Y0_FrameData_O[4]
    DIRECTION OUTPUT ;
    USE SIGNAL ;
    ANTENNADIFFAREA 0.708600 ;
    PORT
      LAYER Metal3 ;
        RECT 184.400 383.680 184.800 384.080 ;
    END
  END Tile_X0Y0_FrameData_O[4]
  PIN Tile_X0Y0_FrameData_O[5]
    DIRECTION OUTPUT ;
    USE SIGNAL ;
    ANTENNADIFFAREA 0.708600 ;
    PORT
      LAYER Metal3 ;
        RECT 184.400 385.360 184.800 385.760 ;
    END
  END Tile_X0Y0_FrameData_O[5]
  PIN Tile_X0Y0_FrameData_O[6]
    DIRECTION OUTPUT ;
    USE SIGNAL ;
    ANTENNADIFFAREA 0.708600 ;
    PORT
      LAYER Metal3 ;
        RECT 184.400 387.040 184.800 387.440 ;
    END
  END Tile_X0Y0_FrameData_O[6]
  PIN Tile_X0Y0_FrameData_O[7]
    DIRECTION OUTPUT ;
    USE SIGNAL ;
    ANTENNADIFFAREA 0.708600 ;
    PORT
      LAYER Metal3 ;
        RECT 184.400 388.720 184.800 389.120 ;
    END
  END Tile_X0Y0_FrameData_O[7]
  PIN Tile_X0Y0_FrameData_O[8]
    DIRECTION OUTPUT ;
    USE SIGNAL ;
    ANTENNADIFFAREA 0.708600 ;
    PORT
      LAYER Metal3 ;
        RECT 184.400 390.400 184.800 390.800 ;
    END
  END Tile_X0Y0_FrameData_O[8]
  PIN Tile_X0Y0_FrameData_O[9]
    DIRECTION OUTPUT ;
    USE SIGNAL ;
    ANTENNADIFFAREA 0.708600 ;
    PORT
      LAYER Metal3 ;
        RECT 184.400 392.080 184.800 392.480 ;
    END
  END Tile_X0Y0_FrameData_O[9]
  PIN Tile_X0Y0_FrameStrobe_O[0]
    DIRECTION OUTPUT ;
    USE SIGNAL ;
    ANTENNADIFFAREA 0.708600 ;
    PORT
      LAYER Metal2 ;
        RECT 132.760 430.520 133.160 430.920 ;
    END
  END Tile_X0Y0_FrameStrobe_O[0]
  PIN Tile_X0Y0_FrameStrobe_O[10]
    DIRECTION OUTPUT ;
    USE SIGNAL ;
    ANTENNADIFFAREA 0.708600 ;
    PORT
      LAYER Metal2 ;
        RECT 142.360 430.520 142.760 430.920 ;
    END
  END Tile_X0Y0_FrameStrobe_O[10]
  PIN Tile_X0Y0_FrameStrobe_O[11]
    DIRECTION OUTPUT ;
    USE SIGNAL ;
    ANTENNADIFFAREA 0.708600 ;
    PORT
      LAYER Metal2 ;
        RECT 143.320 430.520 143.720 430.920 ;
    END
  END Tile_X0Y0_FrameStrobe_O[11]
  PIN Tile_X0Y0_FrameStrobe_O[12]
    DIRECTION OUTPUT ;
    USE SIGNAL ;
    ANTENNADIFFAREA 0.708600 ;
    PORT
      LAYER Metal2 ;
        RECT 144.280 430.520 144.680 430.920 ;
    END
  END Tile_X0Y0_FrameStrobe_O[12]
  PIN Tile_X0Y0_FrameStrobe_O[13]
    DIRECTION OUTPUT ;
    USE SIGNAL ;
    ANTENNADIFFAREA 0.708600 ;
    PORT
      LAYER Metal2 ;
        RECT 145.240 430.520 145.640 430.920 ;
    END
  END Tile_X0Y0_FrameStrobe_O[13]
  PIN Tile_X0Y0_FrameStrobe_O[14]
    DIRECTION OUTPUT ;
    USE SIGNAL ;
    ANTENNADIFFAREA 0.708600 ;
    PORT
      LAYER Metal2 ;
        RECT 146.200 430.520 146.600 430.920 ;
    END
  END Tile_X0Y0_FrameStrobe_O[14]
  PIN Tile_X0Y0_FrameStrobe_O[15]
    DIRECTION OUTPUT ;
    USE SIGNAL ;
    ANTENNADIFFAREA 0.708600 ;
    PORT
      LAYER Metal2 ;
        RECT 147.160 430.520 147.560 430.920 ;
    END
  END Tile_X0Y0_FrameStrobe_O[15]
  PIN Tile_X0Y0_FrameStrobe_O[16]
    DIRECTION OUTPUT ;
    USE SIGNAL ;
    ANTENNADIFFAREA 0.708600 ;
    PORT
      LAYER Metal2 ;
        RECT 148.120 430.520 148.520 430.920 ;
    END
  END Tile_X0Y0_FrameStrobe_O[16]
  PIN Tile_X0Y0_FrameStrobe_O[17]
    DIRECTION OUTPUT ;
    USE SIGNAL ;
    ANTENNADIFFAREA 0.708600 ;
    PORT
      LAYER Metal2 ;
        RECT 149.080 430.520 149.480 430.920 ;
    END
  END Tile_X0Y0_FrameStrobe_O[17]
  PIN Tile_X0Y0_FrameStrobe_O[18]
    DIRECTION OUTPUT ;
    USE SIGNAL ;
    ANTENNADIFFAREA 0.708600 ;
    PORT
      LAYER Metal2 ;
        RECT 150.040 430.520 150.440 430.920 ;
    END
  END Tile_X0Y0_FrameStrobe_O[18]
  PIN Tile_X0Y0_FrameStrobe_O[19]
    DIRECTION OUTPUT ;
    USE SIGNAL ;
    ANTENNADIFFAREA 0.708600 ;
    PORT
      LAYER Metal2 ;
        RECT 151.000 430.520 151.400 430.920 ;
    END
  END Tile_X0Y0_FrameStrobe_O[19]
  PIN Tile_X0Y0_FrameStrobe_O[1]
    DIRECTION OUTPUT ;
    USE SIGNAL ;
    ANTENNADIFFAREA 0.708600 ;
    PORT
      LAYER Metal2 ;
        RECT 133.720 430.520 134.120 430.920 ;
    END
  END Tile_X0Y0_FrameStrobe_O[1]
  PIN Tile_X0Y0_FrameStrobe_O[2]
    DIRECTION OUTPUT ;
    USE SIGNAL ;
    ANTENNADIFFAREA 0.708600 ;
    PORT
      LAYER Metal2 ;
        RECT 134.680 430.520 135.080 430.920 ;
    END
  END Tile_X0Y0_FrameStrobe_O[2]
  PIN Tile_X0Y0_FrameStrobe_O[3]
    DIRECTION OUTPUT ;
    USE SIGNAL ;
    ANTENNADIFFAREA 0.708600 ;
    PORT
      LAYER Metal2 ;
        RECT 135.640 430.520 136.040 430.920 ;
    END
  END Tile_X0Y0_FrameStrobe_O[3]
  PIN Tile_X0Y0_FrameStrobe_O[4]
    DIRECTION OUTPUT ;
    USE SIGNAL ;
    ANTENNADIFFAREA 0.708600 ;
    PORT
      LAYER Metal2 ;
        RECT 136.600 430.520 137.000 430.920 ;
    END
  END Tile_X0Y0_FrameStrobe_O[4]
  PIN Tile_X0Y0_FrameStrobe_O[5]
    DIRECTION OUTPUT ;
    USE SIGNAL ;
    ANTENNADIFFAREA 0.708600 ;
    PORT
      LAYER Metal2 ;
        RECT 137.560 430.520 137.960 430.920 ;
    END
  END Tile_X0Y0_FrameStrobe_O[5]
  PIN Tile_X0Y0_FrameStrobe_O[6]
    DIRECTION OUTPUT ;
    USE SIGNAL ;
    ANTENNADIFFAREA 0.708600 ;
    PORT
      LAYER Metal2 ;
        RECT 138.520 430.520 138.920 430.920 ;
    END
  END Tile_X0Y0_FrameStrobe_O[6]
  PIN Tile_X0Y0_FrameStrobe_O[7]
    DIRECTION OUTPUT ;
    USE SIGNAL ;
    ANTENNADIFFAREA 0.708600 ;
    PORT
      LAYER Metal2 ;
        RECT 139.480 430.520 139.880 430.920 ;
    END
  END Tile_X0Y0_FrameStrobe_O[7]
  PIN Tile_X0Y0_FrameStrobe_O[8]
    DIRECTION OUTPUT ;
    USE SIGNAL ;
    ANTENNADIFFAREA 0.708600 ;
    PORT
      LAYER Metal2 ;
        RECT 140.440 430.520 140.840 430.920 ;
    END
  END Tile_X0Y0_FrameStrobe_O[8]
  PIN Tile_X0Y0_FrameStrobe_O[9]
    DIRECTION OUTPUT ;
    USE SIGNAL ;
    ANTENNADIFFAREA 0.708600 ;
    PORT
      LAYER Metal2 ;
        RECT 141.400 430.520 141.800 430.920 ;
    END
  END Tile_X0Y0_FrameStrobe_O[9]
  PIN Tile_X0Y0_N1BEG[0]
    DIRECTION OUTPUT ;
    USE SIGNAL ;
    ANTENNADIFFAREA 0.708600 ;
    PORT
      LAYER Metal2 ;
        RECT 31.960 430.520 32.360 430.920 ;
    END
  END Tile_X0Y0_N1BEG[0]
  PIN Tile_X0Y0_N1BEG[1]
    DIRECTION OUTPUT ;
    USE SIGNAL ;
    ANTENNADIFFAREA 0.708600 ;
    PORT
      LAYER Metal2 ;
        RECT 32.920 430.520 33.320 430.920 ;
    END
  END Tile_X0Y0_N1BEG[1]
  PIN Tile_X0Y0_N1BEG[2]
    DIRECTION OUTPUT ;
    USE SIGNAL ;
    ANTENNADIFFAREA 0.708600 ;
    PORT
      LAYER Metal2 ;
        RECT 33.880 430.520 34.280 430.920 ;
    END
  END Tile_X0Y0_N1BEG[2]
  PIN Tile_X0Y0_N1BEG[3]
    DIRECTION OUTPUT ;
    USE SIGNAL ;
    ANTENNADIFFAREA 0.708600 ;
    PORT
      LAYER Metal2 ;
        RECT 34.840 430.520 35.240 430.920 ;
    END
  END Tile_X0Y0_N1BEG[3]
  PIN Tile_X0Y0_N2BEG[0]
    DIRECTION OUTPUT ;
    USE SIGNAL ;
    ANTENNADIFFAREA 0.708600 ;
    PORT
      LAYER Metal2 ;
        RECT 35.800 430.520 36.200 430.920 ;
    END
  END Tile_X0Y0_N2BEG[0]
  PIN Tile_X0Y0_N2BEG[1]
    DIRECTION OUTPUT ;
    USE SIGNAL ;
    ANTENNADIFFAREA 0.708600 ;
    PORT
      LAYER Metal2 ;
        RECT 36.760 430.520 37.160 430.920 ;
    END
  END Tile_X0Y0_N2BEG[1]
  PIN Tile_X0Y0_N2BEG[2]
    DIRECTION OUTPUT ;
    USE SIGNAL ;
    ANTENNADIFFAREA 0.708600 ;
    PORT
      LAYER Metal2 ;
        RECT 37.720 430.520 38.120 430.920 ;
    END
  END Tile_X0Y0_N2BEG[2]
  PIN Tile_X0Y0_N2BEG[3]
    DIRECTION OUTPUT ;
    USE SIGNAL ;
    ANTENNADIFFAREA 0.708600 ;
    PORT
      LAYER Metal2 ;
        RECT 38.680 430.520 39.080 430.920 ;
    END
  END Tile_X0Y0_N2BEG[3]
  PIN Tile_X0Y0_N2BEG[4]
    DIRECTION OUTPUT ;
    USE SIGNAL ;
    ANTENNADIFFAREA 0.708600 ;
    PORT
      LAYER Metal2 ;
        RECT 39.640 430.520 40.040 430.920 ;
    END
  END Tile_X0Y0_N2BEG[4]
  PIN Tile_X0Y0_N2BEG[5]
    DIRECTION OUTPUT ;
    USE SIGNAL ;
    ANTENNADIFFAREA 0.708600 ;
    PORT
      LAYER Metal2 ;
        RECT 40.600 430.520 41.000 430.920 ;
    END
  END Tile_X0Y0_N2BEG[5]
  PIN Tile_X0Y0_N2BEG[6]
    DIRECTION OUTPUT ;
    USE SIGNAL ;
    ANTENNADIFFAREA 0.708600 ;
    PORT
      LAYER Metal2 ;
        RECT 41.560 430.520 41.960 430.920 ;
    END
  END Tile_X0Y0_N2BEG[6]
  PIN Tile_X0Y0_N2BEG[7]
    DIRECTION OUTPUT ;
    USE SIGNAL ;
    ANTENNADIFFAREA 0.708600 ;
    PORT
      LAYER Metal2 ;
        RECT 42.520 430.520 42.920 430.920 ;
    END
  END Tile_X0Y0_N2BEG[7]
  PIN Tile_X0Y0_N2BEGb[0]
    DIRECTION OUTPUT ;
    USE SIGNAL ;
    ANTENNADIFFAREA 0.708600 ;
    PORT
      LAYER Metal2 ;
        RECT 43.480 430.520 43.880 430.920 ;
    END
  END Tile_X0Y0_N2BEGb[0]
  PIN Tile_X0Y0_N2BEGb[1]
    DIRECTION OUTPUT ;
    USE SIGNAL ;
    ANTENNADIFFAREA 0.708600 ;
    PORT
      LAYER Metal2 ;
        RECT 44.440 430.520 44.840 430.920 ;
    END
  END Tile_X0Y0_N2BEGb[1]
  PIN Tile_X0Y0_N2BEGb[2]
    DIRECTION OUTPUT ;
    USE SIGNAL ;
    ANTENNADIFFAREA 0.708600 ;
    PORT
      LAYER Metal2 ;
        RECT 45.400 430.520 45.800 430.920 ;
    END
  END Tile_X0Y0_N2BEGb[2]
  PIN Tile_X0Y0_N2BEGb[3]
    DIRECTION OUTPUT ;
    USE SIGNAL ;
    ANTENNADIFFAREA 0.708600 ;
    PORT
      LAYER Metal2 ;
        RECT 46.360 430.520 46.760 430.920 ;
    END
  END Tile_X0Y0_N2BEGb[3]
  PIN Tile_X0Y0_N2BEGb[4]
    DIRECTION OUTPUT ;
    USE SIGNAL ;
    ANTENNADIFFAREA 0.708600 ;
    PORT
      LAYER Metal2 ;
        RECT 47.320 430.520 47.720 430.920 ;
    END
  END Tile_X0Y0_N2BEGb[4]
  PIN Tile_X0Y0_N2BEGb[5]
    DIRECTION OUTPUT ;
    USE SIGNAL ;
    ANTENNADIFFAREA 0.708600 ;
    PORT
      LAYER Metal2 ;
        RECT 48.280 430.520 48.680 430.920 ;
    END
  END Tile_X0Y0_N2BEGb[5]
  PIN Tile_X0Y0_N2BEGb[6]
    DIRECTION OUTPUT ;
    USE SIGNAL ;
    ANTENNADIFFAREA 0.708600 ;
    PORT
      LAYER Metal2 ;
        RECT 49.240 430.520 49.640 430.920 ;
    END
  END Tile_X0Y0_N2BEGb[6]
  PIN Tile_X0Y0_N2BEGb[7]
    DIRECTION OUTPUT ;
    USE SIGNAL ;
    ANTENNADIFFAREA 0.708600 ;
    PORT
      LAYER Metal2 ;
        RECT 50.200 430.520 50.600 430.920 ;
    END
  END Tile_X0Y0_N2BEGb[7]
  PIN Tile_X0Y0_N4BEG[0]
    DIRECTION OUTPUT ;
    USE SIGNAL ;
    ANTENNADIFFAREA 0.708600 ;
    PORT
      LAYER Metal2 ;
        RECT 51.160 430.520 51.560 430.920 ;
    END
  END Tile_X0Y0_N4BEG[0]
  PIN Tile_X0Y0_N4BEG[10]
    DIRECTION OUTPUT ;
    USE SIGNAL ;
    ANTENNADIFFAREA 0.708600 ;
    PORT
      LAYER Metal2 ;
        RECT 60.760 430.520 61.160 430.920 ;
    END
  END Tile_X0Y0_N4BEG[10]
  PIN Tile_X0Y0_N4BEG[11]
    DIRECTION OUTPUT ;
    USE SIGNAL ;
    ANTENNADIFFAREA 0.708600 ;
    PORT
      LAYER Metal2 ;
        RECT 61.720 430.520 62.120 430.920 ;
    END
  END Tile_X0Y0_N4BEG[11]
  PIN Tile_X0Y0_N4BEG[12]
    DIRECTION OUTPUT ;
    USE SIGNAL ;
    ANTENNADIFFAREA 0.708600 ;
    PORT
      LAYER Metal2 ;
        RECT 62.680 430.520 63.080 430.920 ;
    END
  END Tile_X0Y0_N4BEG[12]
  PIN Tile_X0Y0_N4BEG[13]
    DIRECTION OUTPUT ;
    USE SIGNAL ;
    ANTENNADIFFAREA 0.708600 ;
    PORT
      LAYER Metal2 ;
        RECT 63.640 430.520 64.040 430.920 ;
    END
  END Tile_X0Y0_N4BEG[13]
  PIN Tile_X0Y0_N4BEG[14]
    DIRECTION OUTPUT ;
    USE SIGNAL ;
    ANTENNADIFFAREA 0.708600 ;
    PORT
      LAYER Metal2 ;
        RECT 64.600 430.520 65.000 430.920 ;
    END
  END Tile_X0Y0_N4BEG[14]
  PIN Tile_X0Y0_N4BEG[15]
    DIRECTION OUTPUT ;
    USE SIGNAL ;
    ANTENNADIFFAREA 0.708600 ;
    PORT
      LAYER Metal2 ;
        RECT 65.560 430.520 65.960 430.920 ;
    END
  END Tile_X0Y0_N4BEG[15]
  PIN Tile_X0Y0_N4BEG[1]
    DIRECTION OUTPUT ;
    USE SIGNAL ;
    ANTENNADIFFAREA 0.708600 ;
    PORT
      LAYER Metal2 ;
        RECT 52.120 430.520 52.520 430.920 ;
    END
  END Tile_X0Y0_N4BEG[1]
  PIN Tile_X0Y0_N4BEG[2]
    DIRECTION OUTPUT ;
    USE SIGNAL ;
    ANTENNADIFFAREA 0.708600 ;
    PORT
      LAYER Metal2 ;
        RECT 53.080 430.520 53.480 430.920 ;
    END
  END Tile_X0Y0_N4BEG[2]
  PIN Tile_X0Y0_N4BEG[3]
    DIRECTION OUTPUT ;
    USE SIGNAL ;
    ANTENNADIFFAREA 0.708600 ;
    PORT
      LAYER Metal2 ;
        RECT 54.040 430.520 54.440 430.920 ;
    END
  END Tile_X0Y0_N4BEG[3]
  PIN Tile_X0Y0_N4BEG[4]
    DIRECTION OUTPUT ;
    USE SIGNAL ;
    ANTENNADIFFAREA 0.708600 ;
    PORT
      LAYER Metal2 ;
        RECT 55.000 430.520 55.400 430.920 ;
    END
  END Tile_X0Y0_N4BEG[4]
  PIN Tile_X0Y0_N4BEG[5]
    DIRECTION OUTPUT ;
    USE SIGNAL ;
    ANTENNADIFFAREA 0.708600 ;
    PORT
      LAYER Metal2 ;
        RECT 55.960 430.520 56.360 430.920 ;
    END
  END Tile_X0Y0_N4BEG[5]
  PIN Tile_X0Y0_N4BEG[6]
    DIRECTION OUTPUT ;
    USE SIGNAL ;
    ANTENNADIFFAREA 0.708600 ;
    PORT
      LAYER Metal2 ;
        RECT 56.920 430.520 57.320 430.920 ;
    END
  END Tile_X0Y0_N4BEG[6]
  PIN Tile_X0Y0_N4BEG[7]
    DIRECTION OUTPUT ;
    USE SIGNAL ;
    ANTENNADIFFAREA 0.708600 ;
    PORT
      LAYER Metal2 ;
        RECT 57.880 430.520 58.280 430.920 ;
    END
  END Tile_X0Y0_N4BEG[7]
  PIN Tile_X0Y0_N4BEG[8]
    DIRECTION OUTPUT ;
    USE SIGNAL ;
    ANTENNADIFFAREA 0.708600 ;
    PORT
      LAYER Metal2 ;
        RECT 58.840 430.520 59.240 430.920 ;
    END
  END Tile_X0Y0_N4BEG[8]
  PIN Tile_X0Y0_N4BEG[9]
    DIRECTION OUTPUT ;
    USE SIGNAL ;
    ANTENNADIFFAREA 0.708600 ;
    PORT
      LAYER Metal2 ;
        RECT 59.800 430.520 60.200 430.920 ;
    END
  END Tile_X0Y0_N4BEG[9]
  PIN Tile_X0Y0_NN4BEG[0]
    DIRECTION OUTPUT ;
    USE SIGNAL ;
    ANTENNADIFFAREA 0.708600 ;
    PORT
      LAYER Metal2 ;
        RECT 66.520 430.520 66.920 430.920 ;
    END
  END Tile_X0Y0_NN4BEG[0]
  PIN Tile_X0Y0_NN4BEG[10]
    DIRECTION OUTPUT ;
    USE SIGNAL ;
    ANTENNADIFFAREA 0.708600 ;
    PORT
      LAYER Metal2 ;
        RECT 76.120 430.520 76.520 430.920 ;
    END
  END Tile_X0Y0_NN4BEG[10]
  PIN Tile_X0Y0_NN4BEG[11]
    DIRECTION OUTPUT ;
    USE SIGNAL ;
    ANTENNADIFFAREA 0.708600 ;
    PORT
      LAYER Metal2 ;
        RECT 77.080 430.520 77.480 430.920 ;
    END
  END Tile_X0Y0_NN4BEG[11]
  PIN Tile_X0Y0_NN4BEG[12]
    DIRECTION OUTPUT ;
    USE SIGNAL ;
    ANTENNADIFFAREA 0.708600 ;
    PORT
      LAYER Metal2 ;
        RECT 78.040 430.520 78.440 430.920 ;
    END
  END Tile_X0Y0_NN4BEG[12]
  PIN Tile_X0Y0_NN4BEG[13]
    DIRECTION OUTPUT ;
    USE SIGNAL ;
    ANTENNADIFFAREA 0.708600 ;
    PORT
      LAYER Metal2 ;
        RECT 79.000 430.520 79.400 430.920 ;
    END
  END Tile_X0Y0_NN4BEG[13]
  PIN Tile_X0Y0_NN4BEG[14]
    DIRECTION OUTPUT ;
    USE SIGNAL ;
    ANTENNADIFFAREA 0.708600 ;
    PORT
      LAYER Metal2 ;
        RECT 79.960 430.520 80.360 430.920 ;
    END
  END Tile_X0Y0_NN4BEG[14]
  PIN Tile_X0Y0_NN4BEG[15]
    DIRECTION OUTPUT ;
    USE SIGNAL ;
    ANTENNADIFFAREA 0.708600 ;
    PORT
      LAYER Metal2 ;
        RECT 80.920 430.520 81.320 430.920 ;
    END
  END Tile_X0Y0_NN4BEG[15]
  PIN Tile_X0Y0_NN4BEG[1]
    DIRECTION OUTPUT ;
    USE SIGNAL ;
    ANTENNADIFFAREA 0.708600 ;
    PORT
      LAYER Metal2 ;
        RECT 67.480 430.520 67.880 430.920 ;
    END
  END Tile_X0Y0_NN4BEG[1]
  PIN Tile_X0Y0_NN4BEG[2]
    DIRECTION OUTPUT ;
    USE SIGNAL ;
    ANTENNADIFFAREA 0.708600 ;
    PORT
      LAYER Metal2 ;
        RECT 68.440 430.520 68.840 430.920 ;
    END
  END Tile_X0Y0_NN4BEG[2]
  PIN Tile_X0Y0_NN4BEG[3]
    DIRECTION OUTPUT ;
    USE SIGNAL ;
    ANTENNADIFFAREA 0.708600 ;
    PORT
      LAYER Metal2 ;
        RECT 69.400 430.520 69.800 430.920 ;
    END
  END Tile_X0Y0_NN4BEG[3]
  PIN Tile_X0Y0_NN4BEG[4]
    DIRECTION OUTPUT ;
    USE SIGNAL ;
    ANTENNADIFFAREA 0.708600 ;
    PORT
      LAYER Metal2 ;
        RECT 70.360 430.520 70.760 430.920 ;
    END
  END Tile_X0Y0_NN4BEG[4]
  PIN Tile_X0Y0_NN4BEG[5]
    DIRECTION OUTPUT ;
    USE SIGNAL ;
    ANTENNADIFFAREA 0.708600 ;
    PORT
      LAYER Metal2 ;
        RECT 71.320 430.520 71.720 430.920 ;
    END
  END Tile_X0Y0_NN4BEG[5]
  PIN Tile_X0Y0_NN4BEG[6]
    DIRECTION OUTPUT ;
    USE SIGNAL ;
    ANTENNADIFFAREA 0.708600 ;
    PORT
      LAYER Metal2 ;
        RECT 72.280 430.520 72.680 430.920 ;
    END
  END Tile_X0Y0_NN4BEG[6]
  PIN Tile_X0Y0_NN4BEG[7]
    DIRECTION OUTPUT ;
    USE SIGNAL ;
    ANTENNADIFFAREA 0.708600 ;
    PORT
      LAYER Metal2 ;
        RECT 73.240 430.520 73.640 430.920 ;
    END
  END Tile_X0Y0_NN4BEG[7]
  PIN Tile_X0Y0_NN4BEG[8]
    DIRECTION OUTPUT ;
    USE SIGNAL ;
    ANTENNADIFFAREA 0.708600 ;
    PORT
      LAYER Metal2 ;
        RECT 74.200 430.520 74.600 430.920 ;
    END
  END Tile_X0Y0_NN4BEG[8]
  PIN Tile_X0Y0_NN4BEG[9]
    DIRECTION OUTPUT ;
    USE SIGNAL ;
    ANTENNADIFFAREA 0.708600 ;
    PORT
      LAYER Metal2 ;
        RECT 75.160 430.520 75.560 430.920 ;
    END
  END Tile_X0Y0_NN4BEG[9]
  PIN Tile_X0Y0_S1END[0]
    DIRECTION INPUT ;
    USE SIGNAL ;
    ANTENNAGATEAREA 1.107600 ;
    PORT
      LAYER Metal2 ;
        RECT 81.880 430.520 82.280 430.920 ;
    END
  END Tile_X0Y0_S1END[0]
  PIN Tile_X0Y0_S1END[1]
    DIRECTION INPUT ;
    USE SIGNAL ;
    ANTENNAGATEAREA 1.606800 ;
    PORT
      LAYER Metal2 ;
        RECT 82.840 430.520 83.240 430.920 ;
    END
  END Tile_X0Y0_S1END[1]
  PIN Tile_X0Y0_S1END[2]
    DIRECTION INPUT ;
    USE SIGNAL ;
    ANTENNAGATEAREA 1.830400 ;
    PORT
      LAYER Metal2 ;
        RECT 83.800 430.520 84.200 430.920 ;
    END
  END Tile_X0Y0_S1END[2]
  PIN Tile_X0Y0_S1END[3]
    DIRECTION INPUT ;
    USE SIGNAL ;
    ANTENNAGATEAREA 1.648400 ;
    PORT
      LAYER Metal2 ;
        RECT 84.760 430.520 85.160 430.920 ;
    END
  END Tile_X0Y0_S1END[3]
  PIN Tile_X0Y0_S2END[0]
    DIRECTION INPUT ;
    USE SIGNAL ;
    ANTENNAGATEAREA 1.246700 ;
    PORT
      LAYER Metal2 ;
        RECT 93.400 430.520 93.800 430.920 ;
    END
  END Tile_X0Y0_S2END[0]
  PIN Tile_X0Y0_S2END[1]
    DIRECTION INPUT ;
    USE SIGNAL ;
    ANTENNAGATEAREA 1.280000 ;
    PORT
      LAYER Metal2 ;
        RECT 94.360 430.520 94.760 430.920 ;
    END
  END Tile_X0Y0_S2END[1]
  PIN Tile_X0Y0_S2END[2]
    DIRECTION INPUT ;
    USE SIGNAL ;
    ANTENNAGATEAREA 1.373600 ;
    PORT
      LAYER Metal2 ;
        RECT 95.320 430.520 95.720 430.920 ;
    END
  END Tile_X0Y0_S2END[2]
  PIN Tile_X0Y0_S2END[3]
    DIRECTION INPUT ;
    USE SIGNAL ;
    ANTENNAGATEAREA 1.094600 ;
    PORT
      LAYER Metal2 ;
        RECT 96.280 430.520 96.680 430.920 ;
    END
  END Tile_X0Y0_S2END[3]
  PIN Tile_X0Y0_S2END[4]
    DIRECTION INPUT ;
    USE SIGNAL ;
    ANTENNAGATEAREA 1.066000 ;
    PORT
      LAYER Metal2 ;
        RECT 97.240 430.520 97.640 430.920 ;
    END
  END Tile_X0Y0_S2END[4]
  PIN Tile_X0Y0_S2END[5]
    DIRECTION INPUT ;
    USE SIGNAL ;
    ANTENNAGATEAREA 1.189000 ;
    PORT
      LAYER Metal2 ;
        RECT 98.200 430.520 98.600 430.920 ;
    END
  END Tile_X0Y0_S2END[5]
  PIN Tile_X0Y0_S2END[6]
    DIRECTION INPUT ;
    USE SIGNAL ;
    ANTENNAGATEAREA 1.223600 ;
    PORT
      LAYER Metal2 ;
        RECT 99.160 430.520 99.560 430.920 ;
    END
  END Tile_X0Y0_S2END[6]
  PIN Tile_X0Y0_S2END[7]
    DIRECTION INPUT ;
    USE SIGNAL ;
    ANTENNAGATEAREA 1.468000 ;
    PORT
      LAYER Metal2 ;
        RECT 100.120 430.520 100.520 430.920 ;
    END
  END Tile_X0Y0_S2END[7]
  PIN Tile_X0Y0_S2MID[0]
    DIRECTION INPUT ;
    USE SIGNAL ;
    ANTENNAGATEAREA 1.094600 ;
    PORT
      LAYER Metal2 ;
        RECT 85.720 430.520 86.120 430.920 ;
    END
  END Tile_X0Y0_S2MID[0]
  PIN Tile_X0Y0_S2MID[1]
    DIRECTION INPUT ;
    USE SIGNAL ;
    ANTENNAGATEAREA 2.167100 ;
    PORT
      LAYER Metal2 ;
        RECT 86.680 430.520 87.080 430.920 ;
    END
  END Tile_X0Y0_S2MID[1]
  PIN Tile_X0Y0_S2MID[2]
    DIRECTION INPUT ;
    USE SIGNAL ;
    ANTENNAGATEAREA 7.937800 ;
    ANTENNADIFFAREA 20.153999 ;
    PORT
      LAYER Metal2 ;
        RECT 87.640 430.520 88.040 430.920 ;
    END
  END Tile_X0Y0_S2MID[2]
  PIN Tile_X0Y0_S2MID[3]
    DIRECTION INPUT ;
    USE SIGNAL ;
    ANTENNAGATEAREA 2.215200 ;
    PORT
      LAYER Metal2 ;
        RECT 88.600 430.520 89.000 430.920 ;
    END
  END Tile_X0Y0_S2MID[3]
  PIN Tile_X0Y0_S2MID[4]
    DIRECTION INPUT ;
    USE SIGNAL ;
    ANTENNAGATEAREA 1.307800 ;
    PORT
      LAYER Metal2 ;
        RECT 89.560 430.520 89.960 430.920 ;
    END
  END Tile_X0Y0_S2MID[4]
  PIN Tile_X0Y0_S2MID[5]
    DIRECTION INPUT ;
    USE SIGNAL ;
    ANTENNAGATEAREA 1.718400 ;
    PORT
      LAYER Metal2 ;
        RECT 90.520 430.520 90.920 430.920 ;
    END
  END Tile_X0Y0_S2MID[5]
  PIN Tile_X0Y0_S2MID[6]
    DIRECTION INPUT ;
    USE SIGNAL ;
    ANTENNAGATEAREA 1.586800 ;
    PORT
      LAYER Metal2 ;
        RECT 91.480 430.520 91.880 430.920 ;
    END
  END Tile_X0Y0_S2MID[6]
  PIN Tile_X0Y0_S2MID[7]
    DIRECTION INPUT ;
    USE SIGNAL ;
    ANTENNAGATEAREA 2.358000 ;
    PORT
      LAYER Metal2 ;
        RECT 92.440 430.520 92.840 430.920 ;
    END
  END Tile_X0Y0_S2MID[7]
  PIN Tile_X0Y0_S4END[0]
    DIRECTION INPUT ;
    USE SIGNAL ;
    ANTENNAGATEAREA 1.107600 ;
    PORT
      LAYER Metal2 ;
        RECT 101.080 430.520 101.480 430.920 ;
    END
  END Tile_X0Y0_S4END[0]
  PIN Tile_X0Y0_S4END[10]
    DIRECTION INPUT ;
    USE SIGNAL ;
    ANTENNAGATEAREA 0.180700 ;
    PORT
      LAYER Metal2 ;
        RECT 110.680 430.520 111.080 430.920 ;
    END
  END Tile_X0Y0_S4END[10]
  PIN Tile_X0Y0_S4END[11]
    DIRECTION INPUT ;
    USE SIGNAL ;
    ANTENNAGATEAREA 0.180700 ;
    PORT
      LAYER Metal2 ;
        RECT 111.640 430.520 112.040 430.920 ;
    END
  END Tile_X0Y0_S4END[11]
  PIN Tile_X0Y0_S4END[12]
    DIRECTION INPUT ;
    USE SIGNAL ;
    ANTENNAGATEAREA 0.180700 ;
    PORT
      LAYER Metal2 ;
        RECT 112.600 430.520 113.000 430.920 ;
    END
  END Tile_X0Y0_S4END[12]
  PIN Tile_X0Y0_S4END[13]
    DIRECTION INPUT ;
    USE SIGNAL ;
    ANTENNAGATEAREA 0.180700 ;
    PORT
      LAYER Metal2 ;
        RECT 113.560 430.520 113.960 430.920 ;
    END
  END Tile_X0Y0_S4END[13]
  PIN Tile_X0Y0_S4END[14]
    DIRECTION INPUT ;
    USE SIGNAL ;
    ANTENNAGATEAREA 0.180700 ;
    PORT
      LAYER Metal2 ;
        RECT 114.520 430.520 114.920 430.920 ;
    END
  END Tile_X0Y0_S4END[14]
  PIN Tile_X0Y0_S4END[15]
    DIRECTION INPUT ;
    USE SIGNAL ;
    ANTENNAGATEAREA 0.180700 ;
    PORT
      LAYER Metal2 ;
        RECT 115.480 430.520 115.880 430.920 ;
    END
  END Tile_X0Y0_S4END[15]
  PIN Tile_X0Y0_S4END[1]
    DIRECTION INPUT ;
    USE SIGNAL ;
    ANTENNAGATEAREA 0.696800 ;
    PORT
      LAYER Metal2 ;
        RECT 102.040 430.520 102.440 430.920 ;
    END
  END Tile_X0Y0_S4END[1]
  PIN Tile_X0Y0_S4END[2]
    DIRECTION INPUT ;
    USE SIGNAL ;
    ANTENNAGATEAREA 0.960200 ;
    PORT
      LAYER Metal2 ;
        RECT 103.000 430.520 103.400 430.920 ;
    END
  END Tile_X0Y0_S4END[2]
  PIN Tile_X0Y0_S4END[3]
    DIRECTION INPUT ;
    USE SIGNAL ;
    ANTENNAGATEAREA 1.107600 ;
    PORT
      LAYER Metal2 ;
        RECT 103.960 430.520 104.360 430.920 ;
    END
  END Tile_X0Y0_S4END[3]
  PIN Tile_X0Y0_S4END[4]
    DIRECTION INPUT ;
    USE SIGNAL ;
    ANTENNAGATEAREA 3.101800 ;
    ANTENNADIFFAREA 8.061600 ;
    PORT
      LAYER Metal2 ;
        RECT 104.920 430.520 105.320 430.920 ;
    END
  END Tile_X0Y0_S4END[4]
  PIN Tile_X0Y0_S4END[5]
    DIRECTION INPUT ;
    USE SIGNAL ;
    ANTENNAGATEAREA 1.107600 ;
    PORT
      LAYER Metal2 ;
        RECT 105.880 430.520 106.280 430.920 ;
    END
  END Tile_X0Y0_S4END[5]
  PIN Tile_X0Y0_S4END[6]
    DIRECTION INPUT ;
    USE SIGNAL ;
    ANTENNAGATEAREA 1.029600 ;
    PORT
      LAYER Metal2 ;
        RECT 106.840 430.520 107.240 430.920 ;
    END
  END Tile_X0Y0_S4END[6]
  PIN Tile_X0Y0_S4END[7]
    DIRECTION INPUT ;
    USE SIGNAL ;
    ANTENNAGATEAREA 1.144800 ;
    PORT
      LAYER Metal2 ;
        RECT 107.800 430.520 108.200 430.920 ;
    END
  END Tile_X0Y0_S4END[7]
  PIN Tile_X0Y0_S4END[8]
    DIRECTION INPUT ;
    USE SIGNAL ;
    ANTENNAGATEAREA 0.180700 ;
    PORT
      LAYER Metal2 ;
        RECT 108.760 430.520 109.160 430.920 ;
    END
  END Tile_X0Y0_S4END[8]
  PIN Tile_X0Y0_S4END[9]
    DIRECTION INPUT ;
    USE SIGNAL ;
    ANTENNAGATEAREA 0.180700 ;
    PORT
      LAYER Metal2 ;
        RECT 109.720 430.520 110.120 430.920 ;
    END
  END Tile_X0Y0_S4END[9]
  PIN Tile_X0Y0_SS4END[0]
    DIRECTION INPUT ;
    USE SIGNAL ;
    ANTENNAGATEAREA 0.668200 ;
    PORT
      LAYER Metal2 ;
        RECT 116.440 430.520 116.840 430.920 ;
    END
  END Tile_X0Y0_SS4END[0]
  PIN Tile_X0Y0_SS4END[10]
    DIRECTION INPUT ;
    USE SIGNAL ;
    ANTENNAGATEAREA 0.180700 ;
    PORT
      LAYER Metal2 ;
        RECT 126.040 430.520 126.440 430.920 ;
    END
  END Tile_X0Y0_SS4END[10]
  PIN Tile_X0Y0_SS4END[11]
    DIRECTION INPUT ;
    USE SIGNAL ;
    ANTENNAGATEAREA 0.180700 ;
    PORT
      LAYER Metal2 ;
        RECT 127.000 430.520 127.400 430.920 ;
    END
  END Tile_X0Y0_SS4END[11]
  PIN Tile_X0Y0_SS4END[12]
    DIRECTION INPUT ;
    USE SIGNAL ;
    ANTENNAGATEAREA 0.180700 ;
    PORT
      LAYER Metal2 ;
        RECT 127.960 430.520 128.360 430.920 ;
    END
  END Tile_X0Y0_SS4END[12]
  PIN Tile_X0Y0_SS4END[13]
    DIRECTION INPUT ;
    USE SIGNAL ;
    ANTENNAGATEAREA 0.180700 ;
    PORT
      LAYER Metal2 ;
        RECT 128.920 430.520 129.320 430.920 ;
    END
  END Tile_X0Y0_SS4END[13]
  PIN Tile_X0Y0_SS4END[14]
    DIRECTION INPUT ;
    USE SIGNAL ;
    ANTENNAGATEAREA 0.180700 ;
    PORT
      LAYER Metal2 ;
        RECT 129.880 430.520 130.280 430.920 ;
    END
  END Tile_X0Y0_SS4END[14]
  PIN Tile_X0Y0_SS4END[15]
    DIRECTION INPUT ;
    USE SIGNAL ;
    ANTENNAGATEAREA 0.180700 ;
    PORT
      LAYER Metal2 ;
        RECT 130.840 430.520 131.240 430.920 ;
    END
  END Tile_X0Y0_SS4END[15]
  PIN Tile_X0Y0_SS4END[1]
    DIRECTION INPUT ;
    USE SIGNAL ;
    ANTENNAGATEAREA 0.668200 ;
    PORT
      LAYER Metal2 ;
        RECT 117.400 430.520 117.800 430.920 ;
    END
  END Tile_X0Y0_SS4END[1]
  PIN Tile_X0Y0_SS4END[2]
    DIRECTION INPUT ;
    USE SIGNAL ;
    ANTENNAGATEAREA 0.681200 ;
    PORT
      LAYER Metal2 ;
        RECT 118.360 430.520 118.760 430.920 ;
    END
  END Tile_X0Y0_SS4END[2]
  PIN Tile_X0Y0_SS4END[3]
    DIRECTION INPUT ;
    USE SIGNAL ;
    ANTENNAGATEAREA 0.455000 ;
    PORT
      LAYER Metal2 ;
        RECT 119.320 430.520 119.720 430.920 ;
    END
  END Tile_X0Y0_SS4END[3]
  PIN Tile_X0Y0_SS4END[4]
    DIRECTION INPUT ;
    USE SIGNAL ;
    ANTENNAGATEAREA 0.734000 ;
    PORT
      LAYER Metal2 ;
        RECT 120.280 430.520 120.680 430.920 ;
    END
  END Tile_X0Y0_SS4END[4]
  PIN Tile_X0Y0_SS4END[5]
    DIRECTION INPUT ;
    USE SIGNAL ;
    ANTENNAGATEAREA 3.086200 ;
    ANTENNADIFFAREA 8.061600 ;
    PORT
      LAYER Metal2 ;
        RECT 121.240 430.520 121.640 430.920 ;
    END
  END Tile_X0Y0_SS4END[5]
  PIN Tile_X0Y0_SS4END[6]
    DIRECTION INPUT ;
    USE SIGNAL ;
    ANTENNAGATEAREA 0.696800 ;
    PORT
      LAYER Metal2 ;
        RECT 122.200 430.520 122.600 430.920 ;
    END
  END Tile_X0Y0_SS4END[6]
  PIN Tile_X0Y0_SS4END[7]
    DIRECTION INPUT ;
    USE SIGNAL ;
    ANTENNAGATEAREA 0.455000 ;
    PORT
      LAYER Metal2 ;
        RECT 123.160 430.520 123.560 430.920 ;
    END
  END Tile_X0Y0_SS4END[7]
  PIN Tile_X0Y0_SS4END[8]
    DIRECTION INPUT ;
    USE SIGNAL ;
    ANTENNAGATEAREA 0.180700 ;
    PORT
      LAYER Metal2 ;
        RECT 124.120 430.520 124.520 430.920 ;
    END
  END Tile_X0Y0_SS4END[8]
  PIN Tile_X0Y0_SS4END[9]
    DIRECTION INPUT ;
    USE SIGNAL ;
    ANTENNAGATEAREA 0.180700 ;
    PORT
      LAYER Metal2 ;
        RECT 125.080 430.520 125.480 430.920 ;
    END
  END Tile_X0Y0_SS4END[9]
  PIN Tile_X0Y0_UserCLKo
    DIRECTION OUTPUT ;
    USE SIGNAL ;
    ANTENNADIFFAREA 0.708600 ;
    PORT
      LAYER Metal2 ;
        RECT 131.800 430.520 132.200 430.920 ;
    END
  END Tile_X0Y0_UserCLKo
  PIN Tile_X0Y0_W1BEG[0]
    DIRECTION OUTPUT ;
    USE SIGNAL ;
    ANTENNADIFFAREA 0.708600 ;
    PORT
      LAYER Metal3 ;
        RECT 0.000 215.680 0.400 216.080 ;
    END
  END Tile_X0Y0_W1BEG[0]
  PIN Tile_X0Y0_W1BEG[1]
    DIRECTION OUTPUT ;
    USE SIGNAL ;
    ANTENNADIFFAREA 0.708600 ;
    PORT
      LAYER Metal3 ;
        RECT 0.000 217.360 0.400 217.760 ;
    END
  END Tile_X0Y0_W1BEG[1]
  PIN Tile_X0Y0_W1BEG[2]
    DIRECTION OUTPUT ;
    USE SIGNAL ;
    ANTENNADIFFAREA 0.708600 ;
    PORT
      LAYER Metal3 ;
        RECT 0.000 219.040 0.400 219.440 ;
    END
  END Tile_X0Y0_W1BEG[2]
  PIN Tile_X0Y0_W1BEG[3]
    DIRECTION OUTPUT ;
    USE SIGNAL ;
    ANTENNADIFFAREA 0.708600 ;
    PORT
      LAYER Metal3 ;
        RECT 0.000 220.720 0.400 221.120 ;
    END
  END Tile_X0Y0_W1BEG[3]
  PIN Tile_X0Y0_W1END[0]
    DIRECTION INPUT ;
    USE SIGNAL ;
    ANTENNAGATEAREA 1.904800 ;
    PORT
      LAYER Metal3 ;
        RECT 184.400 215.680 184.800 216.080 ;
    END
  END Tile_X0Y0_W1END[0]
  PIN Tile_X0Y0_W1END[1]
    DIRECTION INPUT ;
    USE SIGNAL ;
    ANTENNAGATEAREA 2.149500 ;
    PORT
      LAYER Metal3 ;
        RECT 184.400 217.360 184.800 217.760 ;
    END
  END Tile_X0Y0_W1END[1]
  PIN Tile_X0Y0_W1END[2]
    DIRECTION INPUT ;
    USE SIGNAL ;
    ANTENNAGATEAREA 2.228200 ;
    PORT
      LAYER Metal3 ;
        RECT 184.400 219.040 184.800 219.440 ;
    END
  END Tile_X0Y0_W1END[2]
  PIN Tile_X0Y0_W1END[3]
    DIRECTION INPUT ;
    USE SIGNAL ;
    ANTENNAGATEAREA 2.176200 ;
    PORT
      LAYER Metal3 ;
        RECT 184.400 220.720 184.800 221.120 ;
    END
  END Tile_X0Y0_W1END[3]
  PIN Tile_X0Y0_W2BEG[0]
    DIRECTION OUTPUT ;
    USE SIGNAL ;
    ANTENNADIFFAREA 0.708600 ;
    PORT
      LAYER Metal3 ;
        RECT 0.000 222.400 0.400 222.800 ;
    END
  END Tile_X0Y0_W2BEG[0]
  PIN Tile_X0Y0_W2BEG[1]
    DIRECTION OUTPUT ;
    USE SIGNAL ;
    ANTENNADIFFAREA 0.708600 ;
    PORT
      LAYER Metal3 ;
        RECT 0.000 224.080 0.400 224.480 ;
    END
  END Tile_X0Y0_W2BEG[1]
  PIN Tile_X0Y0_W2BEG[2]
    DIRECTION OUTPUT ;
    USE SIGNAL ;
    ANTENNADIFFAREA 0.708600 ;
    PORT
      LAYER Metal3 ;
        RECT 0.000 225.760 0.400 226.160 ;
    END
  END Tile_X0Y0_W2BEG[2]
  PIN Tile_X0Y0_W2BEG[3]
    DIRECTION OUTPUT ;
    USE SIGNAL ;
    ANTENNADIFFAREA 0.708600 ;
    PORT
      LAYER Metal3 ;
        RECT 0.000 227.440 0.400 227.840 ;
    END
  END Tile_X0Y0_W2BEG[3]
  PIN Tile_X0Y0_W2BEG[4]
    DIRECTION OUTPUT ;
    USE SIGNAL ;
    ANTENNADIFFAREA 0.708600 ;
    PORT
      LAYER Metal3 ;
        RECT 0.000 229.120 0.400 229.520 ;
    END
  END Tile_X0Y0_W2BEG[4]
  PIN Tile_X0Y0_W2BEG[5]
    DIRECTION OUTPUT ;
    USE SIGNAL ;
    ANTENNADIFFAREA 0.708600 ;
    PORT
      LAYER Metal3 ;
        RECT 0.000 230.800 0.400 231.200 ;
    END
  END Tile_X0Y0_W2BEG[5]
  PIN Tile_X0Y0_W2BEG[6]
    DIRECTION OUTPUT ;
    USE SIGNAL ;
    ANTENNADIFFAREA 0.708600 ;
    PORT
      LAYER Metal3 ;
        RECT 0.000 232.480 0.400 232.880 ;
    END
  END Tile_X0Y0_W2BEG[6]
  PIN Tile_X0Y0_W2BEG[7]
    DIRECTION OUTPUT ;
    USE SIGNAL ;
    ANTENNADIFFAREA 0.708600 ;
    PORT
      LAYER Metal3 ;
        RECT 0.000 234.160 0.400 234.560 ;
    END
  END Tile_X0Y0_W2BEG[7]
  PIN Tile_X0Y0_W2BEGb[0]
    DIRECTION OUTPUT ;
    USE SIGNAL ;
    ANTENNADIFFAREA 0.708600 ;
    PORT
      LAYER Metal3 ;
        RECT 0.000 235.840 0.400 236.240 ;
    END
  END Tile_X0Y0_W2BEGb[0]
  PIN Tile_X0Y0_W2BEGb[1]
    DIRECTION OUTPUT ;
    USE SIGNAL ;
    ANTENNADIFFAREA 0.708600 ;
    PORT
      LAYER Metal3 ;
        RECT 0.000 237.520 0.400 237.920 ;
    END
  END Tile_X0Y0_W2BEGb[1]
  PIN Tile_X0Y0_W2BEGb[2]
    DIRECTION OUTPUT ;
    USE SIGNAL ;
    ANTENNADIFFAREA 0.708600 ;
    PORT
      LAYER Metal3 ;
        RECT 0.000 239.200 0.400 239.600 ;
    END
  END Tile_X0Y0_W2BEGb[2]
  PIN Tile_X0Y0_W2BEGb[3]
    DIRECTION OUTPUT ;
    USE SIGNAL ;
    ANTENNADIFFAREA 0.708600 ;
    PORT
      LAYER Metal3 ;
        RECT 0.000 240.880 0.400 241.280 ;
    END
  END Tile_X0Y0_W2BEGb[3]
  PIN Tile_X0Y0_W2BEGb[4]
    DIRECTION OUTPUT ;
    USE SIGNAL ;
    ANTENNADIFFAREA 0.708600 ;
    PORT
      LAYER Metal3 ;
        RECT 0.000 242.560 0.400 242.960 ;
    END
  END Tile_X0Y0_W2BEGb[4]
  PIN Tile_X0Y0_W2BEGb[5]
    DIRECTION OUTPUT ;
    USE SIGNAL ;
    ANTENNADIFFAREA 0.708600 ;
    PORT
      LAYER Metal3 ;
        RECT 0.000 244.240 0.400 244.640 ;
    END
  END Tile_X0Y0_W2BEGb[5]
  PIN Tile_X0Y0_W2BEGb[6]
    DIRECTION OUTPUT ;
    USE SIGNAL ;
    ANTENNADIFFAREA 0.708600 ;
    PORT
      LAYER Metal3 ;
        RECT 0.000 245.920 0.400 246.320 ;
    END
  END Tile_X0Y0_W2BEGb[6]
  PIN Tile_X0Y0_W2BEGb[7]
    DIRECTION OUTPUT ;
    USE SIGNAL ;
    ANTENNADIFFAREA 0.708600 ;
    PORT
      LAYER Metal3 ;
        RECT 0.000 247.600 0.400 248.000 ;
    END
  END Tile_X0Y0_W2BEGb[7]
  PIN Tile_X0Y0_W2END[0]
    DIRECTION INPUT ;
    USE SIGNAL ;
    ANTENNAGATEAREA 3.649100 ;
    ANTENNADIFFAREA 10.077000 ;
    PORT
      LAYER Metal3 ;
        RECT 184.400 235.840 184.800 236.240 ;
    END
  END Tile_X0Y0_W2END[0]
  PIN Tile_X0Y0_W2END[1]
    DIRECTION INPUT ;
    USE SIGNAL ;
    ANTENNAGATEAREA 1.489600 ;
    PORT
      LAYER Metal3 ;
        RECT 184.400 237.520 184.800 237.920 ;
    END
  END Tile_X0Y0_W2END[1]
  PIN Tile_X0Y0_W2END[2]
    DIRECTION INPUT ;
    USE SIGNAL ;
    ANTENNAGATEAREA 1.331200 ;
    PORT
      LAYER Metal3 ;
        RECT 184.400 239.200 184.800 239.600 ;
    END
  END Tile_X0Y0_W2END[2]
  PIN Tile_X0Y0_W2END[3]
    DIRECTION INPUT ;
    USE SIGNAL ;
    ANTENNAGATEAREA 1.604500 ;
    PORT
      LAYER Metal3 ;
        RECT 184.400 240.880 184.800 241.280 ;
    END
  END Tile_X0Y0_W2END[3]
  PIN Tile_X0Y0_W2END[4]
    DIRECTION INPUT ;
    USE SIGNAL ;
    ANTENNAGATEAREA 1.673100 ;
    PORT
      LAYER Metal3 ;
        RECT 184.400 242.560 184.800 242.960 ;
    END
  END Tile_X0Y0_W2END[4]
  PIN Tile_X0Y0_W2END[5]
    DIRECTION INPUT ;
    USE SIGNAL ;
    ANTENNAGATEAREA 0.426400 ;
    PORT
      LAYER Metal3 ;
        RECT 184.400 244.240 184.800 244.640 ;
    END
  END Tile_X0Y0_W2END[5]
  PIN Tile_X0Y0_W2END[6]
    DIRECTION INPUT ;
    USE SIGNAL ;
    ANTENNAGATEAREA 0.426400 ;
    PORT
      LAYER Metal3 ;
        RECT 184.400 245.920 184.800 246.320 ;
    END
  END Tile_X0Y0_W2END[6]
  PIN Tile_X0Y0_W2END[7]
    DIRECTION INPUT ;
    USE SIGNAL ;
    ANTENNAGATEAREA 0.833300 ;
    PORT
      LAYER Metal3 ;
        RECT 184.400 247.600 184.800 248.000 ;
    END
  END Tile_X0Y0_W2END[7]
  PIN Tile_X0Y0_W2MID[0]
    DIRECTION INPUT ;
    USE SIGNAL ;
    ANTENNAGATEAREA 0.899100 ;
    PORT
      LAYER Metal3 ;
        RECT 184.400 222.400 184.800 222.800 ;
    END
  END Tile_X0Y0_W2MID[0]
  PIN Tile_X0Y0_W2MID[1]
    DIRECTION INPUT ;
    USE SIGNAL ;
    ANTENNAGATEAREA 1.059500 ;
    PORT
      LAYER Metal3 ;
        RECT 184.400 224.080 184.800 224.480 ;
    END
  END Tile_X0Y0_W2MID[1]
  PIN Tile_X0Y0_W2MID[2]
    DIRECTION INPUT ;
    USE SIGNAL ;
    ANTENNAGATEAREA 0.820300 ;
    PORT
      LAYER Metal3 ;
        RECT 184.400 225.760 184.800 226.160 ;
    END
  END Tile_X0Y0_W2MID[2]
  PIN Tile_X0Y0_W2MID[3]
    DIRECTION INPUT ;
    USE SIGNAL ;
    ANTENNAGATEAREA 1.090700 ;
    PORT
      LAYER Metal3 ;
        RECT 184.400 227.440 184.800 227.840 ;
    END
  END Tile_X0Y0_W2MID[3]
  PIN Tile_X0Y0_W2MID[4]
    DIRECTION INPUT ;
    USE SIGNAL ;
    ANTENNAGATEAREA 0.820300 ;
    PORT
      LAYER Metal3 ;
        RECT 184.400 229.120 184.800 229.520 ;
    END
  END Tile_X0Y0_W2MID[4]
  PIN Tile_X0Y0_W2MID[5]
    DIRECTION INPUT ;
    USE SIGNAL ;
    ANTENNAGATEAREA 1.062100 ;
    PORT
      LAYER Metal3 ;
        RECT 184.400 230.800 184.800 231.200 ;
    END
  END Tile_X0Y0_W2MID[5]
  PIN Tile_X0Y0_W2MID[6]
    DIRECTION INPUT ;
    USE SIGNAL ;
    ANTENNAGATEAREA 3.234400 ;
    ANTENNADIFFAREA 8.061600 ;
    PORT
      LAYER Metal3 ;
        RECT 184.400 232.480 184.800 232.880 ;
    END
  END Tile_X0Y0_W2MID[6]
  PIN Tile_X0Y0_W2MID[7]
    DIRECTION INPUT ;
    USE SIGNAL ;
    ANTENNAGATEAREA 1.062100 ;
    PORT
      LAYER Metal3 ;
        RECT 184.400 234.160 184.800 234.560 ;
    END
  END Tile_X0Y0_W2MID[7]
  PIN Tile_X0Y0_W6BEG[0]
    DIRECTION OUTPUT ;
    USE SIGNAL ;
    ANTENNADIFFAREA 0.708600 ;
    PORT
      LAYER Metal3 ;
        RECT 0.000 276.160 0.400 276.560 ;
    END
  END Tile_X0Y0_W6BEG[0]
  PIN Tile_X0Y0_W6BEG[10]
    DIRECTION OUTPUT ;
    USE SIGNAL ;
    ANTENNADIFFAREA 0.708600 ;
    PORT
      LAYER Metal3 ;
        RECT 0.000 292.960 0.400 293.360 ;
    END
  END Tile_X0Y0_W6BEG[10]
  PIN Tile_X0Y0_W6BEG[11]
    DIRECTION OUTPUT ;
    USE SIGNAL ;
    ANTENNADIFFAREA 0.708600 ;
    PORT
      LAYER Metal3 ;
        RECT 0.000 294.640 0.400 295.040 ;
    END
  END Tile_X0Y0_W6BEG[11]
  PIN Tile_X0Y0_W6BEG[1]
    DIRECTION OUTPUT ;
    USE SIGNAL ;
    ANTENNADIFFAREA 0.708600 ;
    PORT
      LAYER Metal3 ;
        RECT 0.000 277.840 0.400 278.240 ;
    END
  END Tile_X0Y0_W6BEG[1]
  PIN Tile_X0Y0_W6BEG[2]
    DIRECTION OUTPUT ;
    USE SIGNAL ;
    ANTENNADIFFAREA 0.708600 ;
    PORT
      LAYER Metal3 ;
        RECT 0.000 279.520 0.400 279.920 ;
    END
  END Tile_X0Y0_W6BEG[2]
  PIN Tile_X0Y0_W6BEG[3]
    DIRECTION OUTPUT ;
    USE SIGNAL ;
    ANTENNADIFFAREA 0.708600 ;
    PORT
      LAYER Metal3 ;
        RECT 0.000 281.200 0.400 281.600 ;
    END
  END Tile_X0Y0_W6BEG[3]
  PIN Tile_X0Y0_W6BEG[4]
    DIRECTION OUTPUT ;
    USE SIGNAL ;
    ANTENNADIFFAREA 0.708600 ;
    PORT
      LAYER Metal3 ;
        RECT 0.000 282.880 0.400 283.280 ;
    END
  END Tile_X0Y0_W6BEG[4]
  PIN Tile_X0Y0_W6BEG[5]
    DIRECTION OUTPUT ;
    USE SIGNAL ;
    ANTENNADIFFAREA 0.708600 ;
    PORT
      LAYER Metal3 ;
        RECT 0.000 284.560 0.400 284.960 ;
    END
  END Tile_X0Y0_W6BEG[5]
  PIN Tile_X0Y0_W6BEG[6]
    DIRECTION OUTPUT ;
    USE SIGNAL ;
    ANTENNADIFFAREA 0.708600 ;
    PORT
      LAYER Metal3 ;
        RECT 0.000 286.240 0.400 286.640 ;
    END
  END Tile_X0Y0_W6BEG[6]
  PIN Tile_X0Y0_W6BEG[7]
    DIRECTION OUTPUT ;
    USE SIGNAL ;
    ANTENNADIFFAREA 0.708600 ;
    PORT
      LAYER Metal3 ;
        RECT 0.000 287.920 0.400 288.320 ;
    END
  END Tile_X0Y0_W6BEG[7]
  PIN Tile_X0Y0_W6BEG[8]
    DIRECTION OUTPUT ;
    USE SIGNAL ;
    ANTENNADIFFAREA 0.708600 ;
    PORT
      LAYER Metal3 ;
        RECT 0.000 289.600 0.400 290.000 ;
    END
  END Tile_X0Y0_W6BEG[8]
  PIN Tile_X0Y0_W6BEG[9]
    DIRECTION OUTPUT ;
    USE SIGNAL ;
    ANTENNADIFFAREA 0.708600 ;
    PORT
      LAYER Metal3 ;
        RECT 0.000 291.280 0.400 291.680 ;
    END
  END Tile_X0Y0_W6BEG[9]
  PIN Tile_X0Y0_W6END[0]
    DIRECTION INPUT ;
    USE SIGNAL ;
    ANTENNAGATEAREA 1.970800 ;
    PORT
      LAYER Metal3 ;
        RECT 184.400 276.160 184.800 276.560 ;
    END
  END Tile_X0Y0_W6END[0]
  PIN Tile_X0Y0_W6END[10]
    DIRECTION INPUT ;
    USE SIGNAL ;
    ANTENNAGATEAREA 0.180700 ;
    PORT
      LAYER Metal3 ;
        RECT 184.400 292.960 184.800 293.360 ;
    END
  END Tile_X0Y0_W6END[10]
  PIN Tile_X0Y0_W6END[11]
    DIRECTION INPUT ;
    USE SIGNAL ;
    ANTENNAGATEAREA 0.180700 ;
    PORT
      LAYER Metal3 ;
        RECT 184.400 294.640 184.800 295.040 ;
    END
  END Tile_X0Y0_W6END[11]
  PIN Tile_X0Y0_W6END[1]
    DIRECTION INPUT ;
    USE SIGNAL ;
    ANTENNAGATEAREA 1.386600 ;
    PORT
      LAYER Metal3 ;
        RECT 184.400 277.840 184.800 278.240 ;
    END
  END Tile_X0Y0_W6END[1]
  PIN Tile_X0Y0_W6END[2]
    DIRECTION INPUT ;
    USE SIGNAL ;
    ANTENNAGATEAREA 0.180700 ;
    PORT
      LAYER Metal3 ;
        RECT 184.400 279.520 184.800 279.920 ;
    END
  END Tile_X0Y0_W6END[2]
  PIN Tile_X0Y0_W6END[3]
    DIRECTION INPUT ;
    USE SIGNAL ;
    ANTENNAGATEAREA 0.180700 ;
    PORT
      LAYER Metal3 ;
        RECT 184.400 281.200 184.800 281.600 ;
    END
  END Tile_X0Y0_W6END[3]
  PIN Tile_X0Y0_W6END[4]
    DIRECTION INPUT ;
    USE SIGNAL ;
    ANTENNAGATEAREA 0.180700 ;
    PORT
      LAYER Metal3 ;
        RECT 184.400 282.880 184.800 283.280 ;
    END
  END Tile_X0Y0_W6END[4]
  PIN Tile_X0Y0_W6END[5]
    DIRECTION INPUT ;
    USE SIGNAL ;
    ANTENNAGATEAREA 0.180700 ;
    PORT
      LAYER Metal3 ;
        RECT 184.400 284.560 184.800 284.960 ;
    END
  END Tile_X0Y0_W6END[5]
  PIN Tile_X0Y0_W6END[6]
    DIRECTION INPUT ;
    USE SIGNAL ;
    ANTENNAGATEAREA 0.180700 ;
    PORT
      LAYER Metal3 ;
        RECT 184.400 286.240 184.800 286.640 ;
    END
  END Tile_X0Y0_W6END[6]
  PIN Tile_X0Y0_W6END[7]
    DIRECTION INPUT ;
    USE SIGNAL ;
    ANTENNAGATEAREA 0.180700 ;
    PORT
      LAYER Metal3 ;
        RECT 184.400 287.920 184.800 288.320 ;
    END
  END Tile_X0Y0_W6END[7]
  PIN Tile_X0Y0_W6END[8]
    DIRECTION INPUT ;
    USE SIGNAL ;
    ANTENNAGATEAREA 0.180700 ;
    PORT
      LAYER Metal3 ;
        RECT 184.400 289.600 184.800 290.000 ;
    END
  END Tile_X0Y0_W6END[8]
  PIN Tile_X0Y0_W6END[9]
    DIRECTION INPUT ;
    USE SIGNAL ;
    ANTENNAGATEAREA 0.180700 ;
    PORT
      LAYER Metal3 ;
        RECT 184.400 291.280 184.800 291.680 ;
    END
  END Tile_X0Y0_W6END[9]
  PIN Tile_X0Y0_WW4BEG[0]
    DIRECTION OUTPUT ;
    USE SIGNAL ;
    ANTENNADIFFAREA 0.708600 ;
    PORT
      LAYER Metal3 ;
        RECT 0.000 249.280 0.400 249.680 ;
    END
  END Tile_X0Y0_WW4BEG[0]
  PIN Tile_X0Y0_WW4BEG[10]
    DIRECTION OUTPUT ;
    USE SIGNAL ;
    ANTENNADIFFAREA 0.708600 ;
    PORT
      LAYER Metal3 ;
        RECT 0.000 266.080 0.400 266.480 ;
    END
  END Tile_X0Y0_WW4BEG[10]
  PIN Tile_X0Y0_WW4BEG[11]
    DIRECTION OUTPUT ;
    USE SIGNAL ;
    ANTENNADIFFAREA 0.708600 ;
    PORT
      LAYER Metal3 ;
        RECT 0.000 267.760 0.400 268.160 ;
    END
  END Tile_X0Y0_WW4BEG[11]
  PIN Tile_X0Y0_WW4BEG[12]
    DIRECTION OUTPUT ;
    USE SIGNAL ;
    ANTENNADIFFAREA 0.708600 ;
    PORT
      LAYER Metal3 ;
        RECT 0.000 269.440 0.400 269.840 ;
    END
  END Tile_X0Y0_WW4BEG[12]
  PIN Tile_X0Y0_WW4BEG[13]
    DIRECTION OUTPUT ;
    USE SIGNAL ;
    ANTENNADIFFAREA 0.708600 ;
    PORT
      LAYER Metal3 ;
        RECT 0.000 271.120 0.400 271.520 ;
    END
  END Tile_X0Y0_WW4BEG[13]
  PIN Tile_X0Y0_WW4BEG[14]
    DIRECTION OUTPUT ;
    USE SIGNAL ;
    ANTENNADIFFAREA 0.708600 ;
    PORT
      LAYER Metal3 ;
        RECT 0.000 272.800 0.400 273.200 ;
    END
  END Tile_X0Y0_WW4BEG[14]
  PIN Tile_X0Y0_WW4BEG[15]
    DIRECTION OUTPUT ;
    USE SIGNAL ;
    ANTENNADIFFAREA 0.708600 ;
    PORT
      LAYER Metal3 ;
        RECT 0.000 274.480 0.400 274.880 ;
    END
  END Tile_X0Y0_WW4BEG[15]
  PIN Tile_X0Y0_WW4BEG[1]
    DIRECTION OUTPUT ;
    USE SIGNAL ;
    ANTENNADIFFAREA 0.708600 ;
    PORT
      LAYER Metal3 ;
        RECT 0.000 250.960 0.400 251.360 ;
    END
  END Tile_X0Y0_WW4BEG[1]
  PIN Tile_X0Y0_WW4BEG[2]
    DIRECTION OUTPUT ;
    USE SIGNAL ;
    ANTENNADIFFAREA 0.708600 ;
    PORT
      LAYER Metal3 ;
        RECT 0.000 252.640 0.400 253.040 ;
    END
  END Tile_X0Y0_WW4BEG[2]
  PIN Tile_X0Y0_WW4BEG[3]
    DIRECTION OUTPUT ;
    USE SIGNAL ;
    ANTENNADIFFAREA 0.708600 ;
    PORT
      LAYER Metal3 ;
        RECT 0.000 254.320 0.400 254.720 ;
    END
  END Tile_X0Y0_WW4BEG[3]
  PIN Tile_X0Y0_WW4BEG[4]
    DIRECTION OUTPUT ;
    USE SIGNAL ;
    ANTENNADIFFAREA 0.708600 ;
    PORT
      LAYER Metal3 ;
        RECT 0.000 256.000 0.400 256.400 ;
    END
  END Tile_X0Y0_WW4BEG[4]
  PIN Tile_X0Y0_WW4BEG[5]
    DIRECTION OUTPUT ;
    USE SIGNAL ;
    ANTENNADIFFAREA 0.708600 ;
    PORT
      LAYER Metal3 ;
        RECT 0.000 257.680 0.400 258.080 ;
    END
  END Tile_X0Y0_WW4BEG[5]
  PIN Tile_X0Y0_WW4BEG[6]
    DIRECTION OUTPUT ;
    USE SIGNAL ;
    ANTENNADIFFAREA 0.708600 ;
    PORT
      LAYER Metal3 ;
        RECT 0.000 259.360 0.400 259.760 ;
    END
  END Tile_X0Y0_WW4BEG[6]
  PIN Tile_X0Y0_WW4BEG[7]
    DIRECTION OUTPUT ;
    USE SIGNAL ;
    ANTENNADIFFAREA 0.708600 ;
    PORT
      LAYER Metal3 ;
        RECT 0.000 261.040 0.400 261.440 ;
    END
  END Tile_X0Y0_WW4BEG[7]
  PIN Tile_X0Y0_WW4BEG[8]
    DIRECTION OUTPUT ;
    USE SIGNAL ;
    ANTENNADIFFAREA 0.708600 ;
    PORT
      LAYER Metal3 ;
        RECT 0.000 262.720 0.400 263.120 ;
    END
  END Tile_X0Y0_WW4BEG[8]
  PIN Tile_X0Y0_WW4BEG[9]
    DIRECTION OUTPUT ;
    USE SIGNAL ;
    ANTENNADIFFAREA 0.708600 ;
    PORT
      LAYER Metal3 ;
        RECT 0.000 264.400 0.400 264.800 ;
    END
  END Tile_X0Y0_WW4BEG[9]
  PIN Tile_X0Y0_WW4END[0]
    DIRECTION INPUT ;
    USE SIGNAL ;
    ANTENNAGATEAREA 0.639600 ;
    PORT
      LAYER Metal3 ;
        RECT 184.400 249.280 184.800 249.680 ;
    END
  END Tile_X0Y0_WW4END[0]
  PIN Tile_X0Y0_WW4END[10]
    DIRECTION INPUT ;
    USE SIGNAL ;
    ANTENNAGATEAREA 0.180700 ;
    PORT
      LAYER Metal3 ;
        RECT 184.400 266.080 184.800 266.480 ;
    END
  END Tile_X0Y0_WW4END[10]
  PIN Tile_X0Y0_WW4END[11]
    DIRECTION INPUT ;
    USE SIGNAL ;
    ANTENNAGATEAREA 0.180700 ;
    PORT
      LAYER Metal3 ;
        RECT 184.400 267.760 184.800 268.160 ;
    END
  END Tile_X0Y0_WW4END[11]
  PIN Tile_X0Y0_WW4END[12]
    DIRECTION INPUT ;
    USE SIGNAL ;
    ANTENNAGATEAREA 0.180700 ;
    PORT
      LAYER Metal3 ;
        RECT 184.400 269.440 184.800 269.840 ;
    END
  END Tile_X0Y0_WW4END[12]
  PIN Tile_X0Y0_WW4END[13]
    DIRECTION INPUT ;
    USE SIGNAL ;
    ANTENNAGATEAREA 0.180700 ;
    PORT
      LAYER Metal3 ;
        RECT 184.400 271.120 184.800 271.520 ;
    END
  END Tile_X0Y0_WW4END[13]
  PIN Tile_X0Y0_WW4END[14]
    DIRECTION INPUT ;
    USE SIGNAL ;
    ANTENNAGATEAREA 0.180700 ;
    PORT
      LAYER Metal3 ;
        RECT 184.400 272.800 184.800 273.200 ;
    END
  END Tile_X0Y0_WW4END[14]
  PIN Tile_X0Y0_WW4END[15]
    DIRECTION INPUT ;
    USE SIGNAL ;
    ANTENNAGATEAREA 0.180700 ;
    PORT
      LAYER Metal3 ;
        RECT 184.400 274.480 184.800 274.880 ;
    END
  END Tile_X0Y0_WW4END[15]
  PIN Tile_X0Y0_WW4END[1]
    DIRECTION INPUT ;
    USE SIGNAL ;
    ANTENNAGATEAREA 0.652600 ;
    PORT
      LAYER Metal3 ;
        RECT 184.400 250.960 184.800 251.360 ;
    END
  END Tile_X0Y0_WW4END[1]
  PIN Tile_X0Y0_WW4END[2]
    DIRECTION INPUT ;
    USE SIGNAL ;
    ANTENNAGATEAREA 0.652600 ;
    PORT
      LAYER Metal3 ;
        RECT 184.400 252.640 184.800 253.040 ;
    END
  END Tile_X0Y0_WW4END[2]
  PIN Tile_X0Y0_WW4END[3]
    DIRECTION INPUT ;
    USE SIGNAL ;
    ANTENNAGATEAREA 0.705400 ;
    PORT
      LAYER Metal3 ;
        RECT 184.400 254.320 184.800 254.720 ;
    END
  END Tile_X0Y0_WW4END[3]
  PIN Tile_X0Y0_WW4END[4]
    DIRECTION INPUT ;
    USE SIGNAL ;
    ANTENNAGATEAREA 0.180700 ;
    PORT
      LAYER Metal3 ;
        RECT 184.400 256.000 184.800 256.400 ;
    END
  END Tile_X0Y0_WW4END[4]
  PIN Tile_X0Y0_WW4END[5]
    DIRECTION INPUT ;
    USE SIGNAL ;
    ANTENNAGATEAREA 0.180700 ;
    PORT
      LAYER Metal3 ;
        RECT 184.400 257.680 184.800 258.080 ;
    END
  END Tile_X0Y0_WW4END[5]
  PIN Tile_X0Y0_WW4END[6]
    DIRECTION INPUT ;
    USE SIGNAL ;
    ANTENNAGATEAREA 0.180700 ;
    PORT
      LAYER Metal3 ;
        RECT 184.400 259.360 184.800 259.760 ;
    END
  END Tile_X0Y0_WW4END[6]
  PIN Tile_X0Y0_WW4END[7]
    DIRECTION INPUT ;
    USE SIGNAL ;
    ANTENNAGATEAREA 0.180700 ;
    PORT
      LAYER Metal3 ;
        RECT 184.400 261.040 184.800 261.440 ;
    END
  END Tile_X0Y0_WW4END[7]
  PIN Tile_X0Y0_WW4END[8]
    DIRECTION INPUT ;
    USE SIGNAL ;
    ANTENNAGATEAREA 0.180700 ;
    PORT
      LAYER Metal3 ;
        RECT 184.400 262.720 184.800 263.120 ;
    END
  END Tile_X0Y0_WW4END[8]
  PIN Tile_X0Y0_WW4END[9]
    DIRECTION INPUT ;
    USE SIGNAL ;
    ANTENNAGATEAREA 0.180700 ;
    PORT
      LAYER Metal3 ;
        RECT 184.400 264.400 184.800 264.800 ;
    END
  END Tile_X0Y0_WW4END[9]
  PIN Tile_X0Y1_E1BEG[0]
    DIRECTION OUTPUT ;
    USE SIGNAL ;
    ANTENNADIFFAREA 0.708600 ;
    PORT
      LAYER Metal3 ;
        RECT 184.400 80.860 184.800 81.260 ;
    END
  END Tile_X0Y1_E1BEG[0]
  PIN Tile_X0Y1_E1BEG[1]
    DIRECTION OUTPUT ;
    USE SIGNAL ;
    ANTENNADIFFAREA 0.708600 ;
    PORT
      LAYER Metal3 ;
        RECT 184.400 82.540 184.800 82.940 ;
    END
  END Tile_X0Y1_E1BEG[1]
  PIN Tile_X0Y1_E1BEG[2]
    DIRECTION OUTPUT ;
    USE SIGNAL ;
    ANTENNADIFFAREA 0.708600 ;
    PORT
      LAYER Metal3 ;
        RECT 184.400 84.220 184.800 84.620 ;
    END
  END Tile_X0Y1_E1BEG[2]
  PIN Tile_X0Y1_E1BEG[3]
    DIRECTION OUTPUT ;
    USE SIGNAL ;
    ANTENNADIFFAREA 0.708600 ;
    PORT
      LAYER Metal3 ;
        RECT 184.400 85.900 184.800 86.300 ;
    END
  END Tile_X0Y1_E1BEG[3]
  PIN Tile_X0Y1_E1END[0]
    DIRECTION INPUT ;
    USE SIGNAL ;
    ANTENNAGATEAREA 1.918800 ;
    PORT
      LAYER Metal3 ;
        RECT 0.000 80.860 0.400 81.260 ;
    END
  END Tile_X0Y1_E1END[0]
  PIN Tile_X0Y1_E1END[1]
    DIRECTION INPUT ;
    USE SIGNAL ;
    ANTENNAGATEAREA 1.918800 ;
    PORT
      LAYER Metal3 ;
        RECT 0.000 82.540 0.400 82.940 ;
    END
  END Tile_X0Y1_E1END[1]
  PIN Tile_X0Y1_E1END[2]
    DIRECTION INPUT ;
    USE SIGNAL ;
    ANTENNAGATEAREA 2.411000 ;
    PORT
      LAYER Metal3 ;
        RECT 0.000 84.220 0.400 84.620 ;
    END
  END Tile_X0Y1_E1END[2]
  PIN Tile_X0Y1_E1END[3]
    DIRECTION INPUT ;
    USE SIGNAL ;
    ANTENNAGATEAREA 2.373800 ;
    PORT
      LAYER Metal3 ;
        RECT 0.000 85.900 0.400 86.300 ;
    END
  END Tile_X0Y1_E1END[3]
  PIN Tile_X0Y1_E2BEG[0]
    DIRECTION OUTPUT ;
    USE SIGNAL ;
    ANTENNADIFFAREA 0.708600 ;
    PORT
      LAYER Metal3 ;
        RECT 184.400 87.580 184.800 87.980 ;
    END
  END Tile_X0Y1_E2BEG[0]
  PIN Tile_X0Y1_E2BEG[1]
    DIRECTION OUTPUT ;
    USE SIGNAL ;
    ANTENNADIFFAREA 0.708600 ;
    PORT
      LAYER Metal3 ;
        RECT 184.400 89.260 184.800 89.660 ;
    END
  END Tile_X0Y1_E2BEG[1]
  PIN Tile_X0Y1_E2BEG[2]
    DIRECTION OUTPUT ;
    USE SIGNAL ;
    ANTENNADIFFAREA 0.708600 ;
    PORT
      LAYER Metal3 ;
        RECT 184.400 90.940 184.800 91.340 ;
    END
  END Tile_X0Y1_E2BEG[2]
  PIN Tile_X0Y1_E2BEG[3]
    DIRECTION OUTPUT ;
    USE SIGNAL ;
    ANTENNADIFFAREA 0.708600 ;
    PORT
      LAYER Metal3 ;
        RECT 184.400 92.620 184.800 93.020 ;
    END
  END Tile_X0Y1_E2BEG[3]
  PIN Tile_X0Y1_E2BEG[4]
    DIRECTION OUTPUT ;
    USE SIGNAL ;
    ANTENNADIFFAREA 0.708600 ;
    PORT
      LAYER Metal3 ;
        RECT 184.400 94.300 184.800 94.700 ;
    END
  END Tile_X0Y1_E2BEG[4]
  PIN Tile_X0Y1_E2BEG[5]
    DIRECTION OUTPUT ;
    USE SIGNAL ;
    ANTENNADIFFAREA 0.708600 ;
    PORT
      LAYER Metal3 ;
        RECT 184.400 95.980 184.800 96.380 ;
    END
  END Tile_X0Y1_E2BEG[5]
  PIN Tile_X0Y1_E2BEG[6]
    DIRECTION OUTPUT ;
    USE SIGNAL ;
    ANTENNADIFFAREA 0.708600 ;
    PORT
      LAYER Metal3 ;
        RECT 184.400 97.660 184.800 98.060 ;
    END
  END Tile_X0Y1_E2BEG[6]
  PIN Tile_X0Y1_E2BEG[7]
    DIRECTION OUTPUT ;
    USE SIGNAL ;
    ANTENNADIFFAREA 0.708600 ;
    PORT
      LAYER Metal3 ;
        RECT 184.400 99.340 184.800 99.740 ;
    END
  END Tile_X0Y1_E2BEG[7]
  PIN Tile_X0Y1_E2BEGb[0]
    DIRECTION OUTPUT ;
    USE SIGNAL ;
    ANTENNADIFFAREA 0.708600 ;
    PORT
      LAYER Metal3 ;
        RECT 184.400 101.020 184.800 101.420 ;
    END
  END Tile_X0Y1_E2BEGb[0]
  PIN Tile_X0Y1_E2BEGb[1]
    DIRECTION OUTPUT ;
    USE SIGNAL ;
    ANTENNADIFFAREA 0.708600 ;
    PORT
      LAYER Metal3 ;
        RECT 184.400 102.700 184.800 103.100 ;
    END
  END Tile_X0Y1_E2BEGb[1]
  PIN Tile_X0Y1_E2BEGb[2]
    DIRECTION OUTPUT ;
    USE SIGNAL ;
    ANTENNADIFFAREA 0.708600 ;
    PORT
      LAYER Metal3 ;
        RECT 184.400 104.380 184.800 104.780 ;
    END
  END Tile_X0Y1_E2BEGb[2]
  PIN Tile_X0Y1_E2BEGb[3]
    DIRECTION OUTPUT ;
    USE SIGNAL ;
    ANTENNADIFFAREA 0.708600 ;
    PORT
      LAYER Metal3 ;
        RECT 184.400 106.060 184.800 106.460 ;
    END
  END Tile_X0Y1_E2BEGb[3]
  PIN Tile_X0Y1_E2BEGb[4]
    DIRECTION OUTPUT ;
    USE SIGNAL ;
    ANTENNADIFFAREA 0.708600 ;
    PORT
      LAYER Metal3 ;
        RECT 184.400 107.740 184.800 108.140 ;
    END
  END Tile_X0Y1_E2BEGb[4]
  PIN Tile_X0Y1_E2BEGb[5]
    DIRECTION OUTPUT ;
    USE SIGNAL ;
    ANTENNADIFFAREA 0.708600 ;
    PORT
      LAYER Metal3 ;
        RECT 184.400 109.420 184.800 109.820 ;
    END
  END Tile_X0Y1_E2BEGb[5]
  PIN Tile_X0Y1_E2BEGb[6]
    DIRECTION OUTPUT ;
    USE SIGNAL ;
    ANTENNADIFFAREA 0.708600 ;
    PORT
      LAYER Metal3 ;
        RECT 184.400 111.100 184.800 111.500 ;
    END
  END Tile_X0Y1_E2BEGb[6]
  PIN Tile_X0Y1_E2BEGb[7]
    DIRECTION OUTPUT ;
    USE SIGNAL ;
    ANTENNADIFFAREA 0.708600 ;
    PORT
      LAYER Metal3 ;
        RECT 184.400 112.780 184.800 113.180 ;
    END
  END Tile_X0Y1_E2BEGb[7]
  PIN Tile_X0Y1_E2END[0]
    DIRECTION INPUT ;
    USE SIGNAL ;
    ANTENNAGATEAREA 0.852800 ;
    PORT
      LAYER Metal3 ;
        RECT 0.000 101.020 0.400 101.420 ;
    END
  END Tile_X0Y1_E2END[0]
  PIN Tile_X0Y1_E2END[1]
    DIRECTION INPUT ;
    USE SIGNAL ;
    ANTENNAGATEAREA 0.865800 ;
    PORT
      LAYER Metal3 ;
        RECT 0.000 102.700 0.400 103.100 ;
    END
  END Tile_X0Y1_E2END[1]
  PIN Tile_X0Y1_E2END[2]
    DIRECTION INPUT ;
    USE SIGNAL ;
    ANTENNAGATEAREA 1.459900 ;
    PORT
      LAYER Metal3 ;
        RECT 0.000 104.380 0.400 104.780 ;
    END
  END Tile_X0Y1_E2END[2]
  PIN Tile_X0Y1_E2END[3]
    DIRECTION INPUT ;
    USE SIGNAL ;
    ANTENNAGATEAREA 1.701700 ;
    PORT
      LAYER Metal3 ;
        RECT 0.000 106.060 0.400 106.460 ;
    END
  END Tile_X0Y1_E2END[3]
  PIN Tile_X0Y1_E2END[4]
    DIRECTION INPUT ;
    USE SIGNAL ;
    ANTENNAGATEAREA 1.001000 ;
    PORT
      LAYER Metal3 ;
        RECT 0.000 107.740 0.400 108.140 ;
    END
  END Tile_X0Y1_E2END[4]
  PIN Tile_X0Y1_E2END[5]
    DIRECTION INPUT ;
    USE SIGNAL ;
    ANTENNAGATEAREA 1.279200 ;
    PORT
      LAYER Metal3 ;
        RECT 0.000 109.420 0.400 109.820 ;
    END
  END Tile_X0Y1_E2END[5]
  PIN Tile_X0Y1_E2END[6]
    DIRECTION INPUT ;
    USE SIGNAL ;
    ANTENNAGATEAREA 1.279200 ;
    PORT
      LAYER Metal3 ;
        RECT 0.000 111.100 0.400 111.500 ;
    END
  END Tile_X0Y1_E2END[6]
  PIN Tile_X0Y1_E2END[7]
    DIRECTION INPUT ;
    USE SIGNAL ;
    ANTENNAGATEAREA 1.066000 ;
    PORT
      LAYER Metal3 ;
        RECT 0.000 112.780 0.400 113.180 ;
    END
  END Tile_X0Y1_E2END[7]
  PIN Tile_X0Y1_E2MID[0]
    DIRECTION INPUT ;
    USE SIGNAL ;
    ANTENNAGATEAREA 1.058200 ;
    PORT
      LAYER Metal3 ;
        RECT 0.000 87.580 0.400 87.980 ;
    END
  END Tile_X0Y1_E2MID[0]
  PIN Tile_X0Y1_E2MID[1]
    DIRECTION INPUT ;
    USE SIGNAL ;
    ANTENNAGATEAREA 0.936000 ;
    PORT
      LAYER Metal3 ;
        RECT 0.000 89.260 0.400 89.660 ;
    END
  END Tile_X0Y1_E2MID[1]
  PIN Tile_X0Y1_E2MID[2]
    DIRECTION INPUT ;
    USE SIGNAL ;
    ANTENNAGATEAREA 0.874900 ;
    PORT
      LAYER Metal3 ;
        RECT 0.000 90.940 0.400 91.340 ;
    END
  END Tile_X0Y1_E2MID[2]
  PIN Tile_X0Y1_E2MID[3]
    DIRECTION INPUT ;
    USE SIGNAL ;
    ANTENNAGATEAREA 0.848900 ;
    PORT
      LAYER Metal3 ;
        RECT 0.000 92.620 0.400 93.020 ;
    END
  END Tile_X0Y1_E2MID[3]
  PIN Tile_X0Y1_E2MID[4]
    DIRECTION INPUT ;
    USE SIGNAL ;
    ANTENNAGATEAREA 0.664300 ;
    PORT
      LAYER Metal3 ;
        RECT 0.000 94.300 0.400 94.700 ;
    END
  END Tile_X0Y1_E2MID[4]
  PIN Tile_X0Y1_E2MID[5]
    DIRECTION INPUT ;
    USE SIGNAL ;
    ANTENNAGATEAREA 1.033500 ;
    PORT
      LAYER Metal3 ;
        RECT 0.000 95.980 0.400 96.380 ;
    END
  END Tile_X0Y1_E2MID[5]
  PIN Tile_X0Y1_E2MID[6]
    DIRECTION INPUT ;
    USE SIGNAL ;
    ANTENNAGATEAREA 1.042600 ;
    PORT
      LAYER Metal3 ;
        RECT 0.000 97.660 0.400 98.060 ;
    END
  END Tile_X0Y1_E2MID[6]
  PIN Tile_X0Y1_E2MID[7]
    DIRECTION INPUT ;
    USE SIGNAL ;
    ANTENNAGATEAREA 0.936000 ;
    PORT
      LAYER Metal3 ;
        RECT 0.000 99.340 0.400 99.740 ;
    END
  END Tile_X0Y1_E2MID[7]
  PIN Tile_X0Y1_E6BEG[0]
    DIRECTION OUTPUT ;
    USE SIGNAL ;
    ANTENNADIFFAREA 0.708600 ;
    PORT
      LAYER Metal3 ;
        RECT 184.400 141.340 184.800 141.740 ;
    END
  END Tile_X0Y1_E6BEG[0]
  PIN Tile_X0Y1_E6BEG[10]
    DIRECTION OUTPUT ;
    USE SIGNAL ;
    ANTENNADIFFAREA 0.708600 ;
    PORT
      LAYER Metal3 ;
        RECT 184.400 158.140 184.800 158.540 ;
    END
  END Tile_X0Y1_E6BEG[10]
  PIN Tile_X0Y1_E6BEG[11]
    DIRECTION OUTPUT ;
    USE SIGNAL ;
    ANTENNADIFFAREA 0.708600 ;
    PORT
      LAYER Metal3 ;
        RECT 184.400 159.820 184.800 160.220 ;
    END
  END Tile_X0Y1_E6BEG[11]
  PIN Tile_X0Y1_E6BEG[1]
    DIRECTION OUTPUT ;
    USE SIGNAL ;
    ANTENNADIFFAREA 0.708600 ;
    PORT
      LAYER Metal3 ;
        RECT 184.400 143.020 184.800 143.420 ;
    END
  END Tile_X0Y1_E6BEG[1]
  PIN Tile_X0Y1_E6BEG[2]
    DIRECTION OUTPUT ;
    USE SIGNAL ;
    ANTENNADIFFAREA 0.708600 ;
    PORT
      LAYER Metal3 ;
        RECT 184.400 144.700 184.800 145.100 ;
    END
  END Tile_X0Y1_E6BEG[2]
  PIN Tile_X0Y1_E6BEG[3]
    DIRECTION OUTPUT ;
    USE SIGNAL ;
    ANTENNADIFFAREA 0.708600 ;
    PORT
      LAYER Metal3 ;
        RECT 184.400 146.380 184.800 146.780 ;
    END
  END Tile_X0Y1_E6BEG[3]
  PIN Tile_X0Y1_E6BEG[4]
    DIRECTION OUTPUT ;
    USE SIGNAL ;
    ANTENNADIFFAREA 0.708600 ;
    PORT
      LAYER Metal3 ;
        RECT 184.400 148.060 184.800 148.460 ;
    END
  END Tile_X0Y1_E6BEG[4]
  PIN Tile_X0Y1_E6BEG[5]
    DIRECTION OUTPUT ;
    USE SIGNAL ;
    ANTENNADIFFAREA 0.708600 ;
    PORT
      LAYER Metal3 ;
        RECT 184.400 149.740 184.800 150.140 ;
    END
  END Tile_X0Y1_E6BEG[5]
  PIN Tile_X0Y1_E6BEG[6]
    DIRECTION OUTPUT ;
    USE SIGNAL ;
    ANTENNADIFFAREA 0.708600 ;
    PORT
      LAYER Metal3 ;
        RECT 184.400 151.420 184.800 151.820 ;
    END
  END Tile_X0Y1_E6BEG[6]
  PIN Tile_X0Y1_E6BEG[7]
    DIRECTION OUTPUT ;
    USE SIGNAL ;
    ANTENNADIFFAREA 0.708600 ;
    PORT
      LAYER Metal3 ;
        RECT 184.400 153.100 184.800 153.500 ;
    END
  END Tile_X0Y1_E6BEG[7]
  PIN Tile_X0Y1_E6BEG[8]
    DIRECTION OUTPUT ;
    USE SIGNAL ;
    ANTENNADIFFAREA 0.708600 ;
    PORT
      LAYER Metal3 ;
        RECT 184.400 154.780 184.800 155.180 ;
    END
  END Tile_X0Y1_E6BEG[8]
  PIN Tile_X0Y1_E6BEG[9]
    DIRECTION OUTPUT ;
    USE SIGNAL ;
    ANTENNADIFFAREA 0.708600 ;
    PORT
      LAYER Metal3 ;
        RECT 184.400 156.460 184.800 156.860 ;
    END
  END Tile_X0Y1_E6BEG[9]
  PIN Tile_X0Y1_E6END[0]
    DIRECTION INPUT ;
    USE SIGNAL ;
    ANTENNAGATEAREA 2.672800 ;
    PORT
      LAYER Metal3 ;
        RECT 0.000 141.340 0.400 141.740 ;
    END
  END Tile_X0Y1_E6END[0]
  PIN Tile_X0Y1_E6END[10]
    DIRECTION INPUT ;
    USE SIGNAL ;
    ANTENNAGATEAREA 0.789100 ;
    ANTENNADIFFAREA 2.015400 ;
    PORT
      LAYER Metal3 ;
        RECT 0.000 158.140 0.400 158.540 ;
    END
  END Tile_X0Y1_E6END[10]
  PIN Tile_X0Y1_E6END[11]
    DIRECTION INPUT ;
    USE SIGNAL ;
    ANTENNAGATEAREA 0.789100 ;
    ANTENNADIFFAREA 2.015400 ;
    PORT
      LAYER Metal3 ;
        RECT 0.000 159.820 0.400 160.220 ;
    END
  END Tile_X0Y1_E6END[11]
  PIN Tile_X0Y1_E6END[1]
    DIRECTION INPUT ;
    USE SIGNAL ;
    ANTENNAGATEAREA 2.564900 ;
    PORT
      LAYER Metal3 ;
        RECT 0.000 143.020 0.400 143.420 ;
    END
  END Tile_X0Y1_E6END[1]
  PIN Tile_X0Y1_E6END[2]
    DIRECTION INPUT ;
    USE SIGNAL ;
    ANTENNAGATEAREA 0.180700 ;
    PORT
      LAYER Metal3 ;
        RECT 0.000 144.700 0.400 145.100 ;
    END
  END Tile_X0Y1_E6END[2]
  PIN Tile_X0Y1_E6END[3]
    DIRECTION INPUT ;
    USE SIGNAL ;
    ANTENNAGATEAREA 0.180700 ;
    PORT
      LAYER Metal3 ;
        RECT 0.000 146.380 0.400 146.780 ;
    END
  END Tile_X0Y1_E6END[3]
  PIN Tile_X0Y1_E6END[4]
    DIRECTION INPUT ;
    USE SIGNAL ;
    ANTENNAGATEAREA 0.180700 ;
    PORT
      LAYER Metal3 ;
        RECT 0.000 148.060 0.400 148.460 ;
    END
  END Tile_X0Y1_E6END[4]
  PIN Tile_X0Y1_E6END[5]
    DIRECTION INPUT ;
    USE SIGNAL ;
    ANTENNAGATEAREA 0.789100 ;
    ANTENNADIFFAREA 2.015400 ;
    PORT
      LAYER Metal3 ;
        RECT 0.000 149.740 0.400 150.140 ;
    END
  END Tile_X0Y1_E6END[5]
  PIN Tile_X0Y1_E6END[6]
    DIRECTION INPUT ;
    USE SIGNAL ;
    ANTENNAGATEAREA 0.180700 ;
    PORT
      LAYER Metal3 ;
        RECT 0.000 151.420 0.400 151.820 ;
    END
  END Tile_X0Y1_E6END[6]
  PIN Tile_X0Y1_E6END[7]
    DIRECTION INPUT ;
    USE SIGNAL ;
    ANTENNAGATEAREA 0.180700 ;
    PORT
      LAYER Metal3 ;
        RECT 0.000 153.100 0.400 153.500 ;
    END
  END Tile_X0Y1_E6END[7]
  PIN Tile_X0Y1_E6END[8]
    DIRECTION INPUT ;
    USE SIGNAL ;
    ANTENNAGATEAREA 0.180700 ;
    PORT
      LAYER Metal3 ;
        RECT 0.000 154.780 0.400 155.180 ;
    END
  END Tile_X0Y1_E6END[8]
  PIN Tile_X0Y1_E6END[9]
    DIRECTION INPUT ;
    USE SIGNAL ;
    ANTENNAGATEAREA 0.789100 ;
    ANTENNADIFFAREA 2.015400 ;
    PORT
      LAYER Metal3 ;
        RECT 0.000 156.460 0.400 156.860 ;
    END
  END Tile_X0Y1_E6END[9]
  PIN Tile_X0Y1_EE4BEG[0]
    DIRECTION OUTPUT ;
    USE SIGNAL ;
    ANTENNADIFFAREA 0.708600 ;
    PORT
      LAYER Metal3 ;
        RECT 184.400 114.460 184.800 114.860 ;
    END
  END Tile_X0Y1_EE4BEG[0]
  PIN Tile_X0Y1_EE4BEG[10]
    DIRECTION OUTPUT ;
    USE SIGNAL ;
    ANTENNADIFFAREA 0.708600 ;
    PORT
      LAYER Metal3 ;
        RECT 184.400 131.260 184.800 131.660 ;
    END
  END Tile_X0Y1_EE4BEG[10]
  PIN Tile_X0Y1_EE4BEG[11]
    DIRECTION OUTPUT ;
    USE SIGNAL ;
    ANTENNADIFFAREA 0.708600 ;
    PORT
      LAYER Metal3 ;
        RECT 184.400 132.940 184.800 133.340 ;
    END
  END Tile_X0Y1_EE4BEG[11]
  PIN Tile_X0Y1_EE4BEG[12]
    DIRECTION OUTPUT ;
    USE SIGNAL ;
    ANTENNADIFFAREA 0.708600 ;
    PORT
      LAYER Metal3 ;
        RECT 184.400 134.620 184.800 135.020 ;
    END
  END Tile_X0Y1_EE4BEG[12]
  PIN Tile_X0Y1_EE4BEG[13]
    DIRECTION OUTPUT ;
    USE SIGNAL ;
    ANTENNADIFFAREA 0.708600 ;
    PORT
      LAYER Metal3 ;
        RECT 184.400 136.300 184.800 136.700 ;
    END
  END Tile_X0Y1_EE4BEG[13]
  PIN Tile_X0Y1_EE4BEG[14]
    DIRECTION OUTPUT ;
    USE SIGNAL ;
    ANTENNADIFFAREA 0.708600 ;
    PORT
      LAYER Metal3 ;
        RECT 184.400 137.980 184.800 138.380 ;
    END
  END Tile_X0Y1_EE4BEG[14]
  PIN Tile_X0Y1_EE4BEG[15]
    DIRECTION OUTPUT ;
    USE SIGNAL ;
    ANTENNADIFFAREA 0.708600 ;
    PORT
      LAYER Metal3 ;
        RECT 184.400 139.660 184.800 140.060 ;
    END
  END Tile_X0Y1_EE4BEG[15]
  PIN Tile_X0Y1_EE4BEG[1]
    DIRECTION OUTPUT ;
    USE SIGNAL ;
    ANTENNADIFFAREA 0.708600 ;
    PORT
      LAYER Metal3 ;
        RECT 184.400 116.140 184.800 116.540 ;
    END
  END Tile_X0Y1_EE4BEG[1]
  PIN Tile_X0Y1_EE4BEG[2]
    DIRECTION OUTPUT ;
    USE SIGNAL ;
    ANTENNADIFFAREA 0.708600 ;
    PORT
      LAYER Metal3 ;
        RECT 184.400 117.820 184.800 118.220 ;
    END
  END Tile_X0Y1_EE4BEG[2]
  PIN Tile_X0Y1_EE4BEG[3]
    DIRECTION OUTPUT ;
    USE SIGNAL ;
    ANTENNADIFFAREA 0.708600 ;
    PORT
      LAYER Metal3 ;
        RECT 184.400 119.500 184.800 119.900 ;
    END
  END Tile_X0Y1_EE4BEG[3]
  PIN Tile_X0Y1_EE4BEG[4]
    DIRECTION OUTPUT ;
    USE SIGNAL ;
    ANTENNADIFFAREA 0.708600 ;
    PORT
      LAYER Metal3 ;
        RECT 184.400 121.180 184.800 121.580 ;
    END
  END Tile_X0Y1_EE4BEG[4]
  PIN Tile_X0Y1_EE4BEG[5]
    DIRECTION OUTPUT ;
    USE SIGNAL ;
    ANTENNADIFFAREA 0.708600 ;
    PORT
      LAYER Metal3 ;
        RECT 184.400 122.860 184.800 123.260 ;
    END
  END Tile_X0Y1_EE4BEG[5]
  PIN Tile_X0Y1_EE4BEG[6]
    DIRECTION OUTPUT ;
    USE SIGNAL ;
    ANTENNADIFFAREA 0.708600 ;
    PORT
      LAYER Metal3 ;
        RECT 184.400 124.540 184.800 124.940 ;
    END
  END Tile_X0Y1_EE4BEG[6]
  PIN Tile_X0Y1_EE4BEG[7]
    DIRECTION OUTPUT ;
    USE SIGNAL ;
    ANTENNADIFFAREA 0.708600 ;
    PORT
      LAYER Metal3 ;
        RECT 184.400 126.220 184.800 126.620 ;
    END
  END Tile_X0Y1_EE4BEG[7]
  PIN Tile_X0Y1_EE4BEG[8]
    DIRECTION OUTPUT ;
    USE SIGNAL ;
    ANTENNADIFFAREA 0.708600 ;
    PORT
      LAYER Metal3 ;
        RECT 184.400 127.900 184.800 128.300 ;
    END
  END Tile_X0Y1_EE4BEG[8]
  PIN Tile_X0Y1_EE4BEG[9]
    DIRECTION OUTPUT ;
    USE SIGNAL ;
    ANTENNADIFFAREA 0.708600 ;
    PORT
      LAYER Metal3 ;
        RECT 184.400 129.580 184.800 129.980 ;
    END
  END Tile_X0Y1_EE4BEG[9]
  PIN Tile_X0Y1_EE4END[0]
    DIRECTION INPUT ;
    USE SIGNAL ;
    ANTENNAGATEAREA 0.668200 ;
    PORT
      LAYER Metal3 ;
        RECT 0.000 114.460 0.400 114.860 ;
    END
  END Tile_X0Y1_EE4END[0]
  PIN Tile_X0Y1_EE4END[10]
    DIRECTION INPUT ;
    USE SIGNAL ;
    ANTENNAGATEAREA 1.397500 ;
    ANTENNADIFFAREA 4.030800 ;
    PORT
      LAYER Metal3 ;
        RECT 0.000 131.260 0.400 131.660 ;
    END
  END Tile_X0Y1_EE4END[10]
  PIN Tile_X0Y1_EE4END[11]
    DIRECTION INPUT ;
    USE SIGNAL ;
    ANTENNAGATEAREA 0.789100 ;
    ANTENNADIFFAREA 2.015400 ;
    PORT
      LAYER Metal3 ;
        RECT 0.000 132.940 0.400 133.340 ;
    END
  END Tile_X0Y1_EE4END[11]
  PIN Tile_X0Y1_EE4END[12]
    DIRECTION INPUT ;
    USE SIGNAL ;
    ANTENNAGATEAREA 0.789100 ;
    ANTENNADIFFAREA 2.015400 ;
    PORT
      LAYER Metal3 ;
        RECT 0.000 134.620 0.400 135.020 ;
    END
  END Tile_X0Y1_EE4END[12]
  PIN Tile_X0Y1_EE4END[13]
    DIRECTION INPUT ;
    USE SIGNAL ;
    ANTENNAGATEAREA 0.180700 ;
    PORT
      LAYER Metal3 ;
        RECT 0.000 136.300 0.400 136.700 ;
    END
  END Tile_X0Y1_EE4END[13]
  PIN Tile_X0Y1_EE4END[14]
    DIRECTION INPUT ;
    USE SIGNAL ;
    ANTENNAGATEAREA 0.789100 ;
    ANTENNADIFFAREA 2.015400 ;
    PORT
      LAYER Metal3 ;
        RECT 0.000 137.980 0.400 138.380 ;
    END
  END Tile_X0Y1_EE4END[14]
  PIN Tile_X0Y1_EE4END[15]
    DIRECTION INPUT ;
    USE SIGNAL ;
    ANTENNAGATEAREA 0.180700 ;
    PORT
      LAYER Metal3 ;
        RECT 0.000 139.660 0.400 140.060 ;
    END
  END Tile_X0Y1_EE4END[15]
  PIN Tile_X0Y1_EE4END[1]
    DIRECTION INPUT ;
    USE SIGNAL ;
    ANTENNAGATEAREA 0.639600 ;
    PORT
      LAYER Metal3 ;
        RECT 0.000 116.140 0.400 116.540 ;
    END
  END Tile_X0Y1_EE4END[1]
  PIN Tile_X0Y1_EE4END[2]
    DIRECTION INPUT ;
    USE SIGNAL ;
    ANTENNAGATEAREA 0.705400 ;
    PORT
      LAYER Metal3 ;
        RECT 0.000 117.820 0.400 118.220 ;
    END
  END Tile_X0Y1_EE4END[2]
  PIN Tile_X0Y1_EE4END[3]
    DIRECTION INPUT ;
    USE SIGNAL ;
    ANTENNAGATEAREA 0.492200 ;
    PORT
      LAYER Metal3 ;
        RECT 0.000 119.500 0.400 119.900 ;
    END
  END Tile_X0Y1_EE4END[3]
  PIN Tile_X0Y1_EE4END[4]
    DIRECTION INPUT ;
    USE SIGNAL ;
    ANTENNAGATEAREA 0.789100 ;
    ANTENNADIFFAREA 2.015400 ;
    PORT
      LAYER Metal3 ;
        RECT 0.000 121.180 0.400 121.580 ;
    END
  END Tile_X0Y1_EE4END[4]
  PIN Tile_X0Y1_EE4END[5]
    DIRECTION INPUT ;
    USE SIGNAL ;
    ANTENNAGATEAREA 0.180700 ;
    PORT
      LAYER Metal3 ;
        RECT 0.000 122.860 0.400 123.260 ;
    END
  END Tile_X0Y1_EE4END[5]
  PIN Tile_X0Y1_EE4END[6]
    DIRECTION INPUT ;
    USE SIGNAL ;
    ANTENNAGATEAREA 0.180700 ;
    PORT
      LAYER Metal3 ;
        RECT 0.000 124.540 0.400 124.940 ;
    END
  END Tile_X0Y1_EE4END[6]
  PIN Tile_X0Y1_EE4END[7]
    DIRECTION INPUT ;
    USE SIGNAL ;
    ANTENNAGATEAREA 0.789100 ;
    ANTENNADIFFAREA 2.015400 ;
    PORT
      LAYER Metal3 ;
        RECT 0.000 126.220 0.400 126.620 ;
    END
  END Tile_X0Y1_EE4END[7]
  PIN Tile_X0Y1_EE4END[8]
    DIRECTION INPUT ;
    USE SIGNAL ;
    ANTENNAGATEAREA 0.789100 ;
    ANTENNADIFFAREA 2.015400 ;
    PORT
      LAYER Metal3 ;
        RECT 0.000 127.900 0.400 128.300 ;
    END
  END Tile_X0Y1_EE4END[8]
  PIN Tile_X0Y1_EE4END[9]
    DIRECTION INPUT ;
    USE SIGNAL ;
    ANTENNAGATEAREA 0.789100 ;
    ANTENNADIFFAREA 2.015400 ;
    PORT
      LAYER Metal3 ;
        RECT 0.000 129.580 0.400 129.980 ;
    END
  END Tile_X0Y1_EE4END[9]
  PIN Tile_X0Y1_FrameData[0]
    DIRECTION INPUT ;
    USE SIGNAL ;
    ANTENNAGATEAREA 2.529800 ;
    PORT
      LAYER Metal3 ;
        RECT 0.000 161.500 0.400 161.900 ;
    END
  END Tile_X0Y1_FrameData[0]
  PIN Tile_X0Y1_FrameData[10]
    DIRECTION INPUT ;
    USE SIGNAL ;
    ANTENNAGATEAREA 2.529800 ;
    PORT
      LAYER Metal3 ;
        RECT 0.000 178.300 0.400 178.700 ;
    END
  END Tile_X0Y1_FrameData[10]
  PIN Tile_X0Y1_FrameData[11]
    DIRECTION INPUT ;
    USE SIGNAL ;
    ANTENNAGATEAREA 2.529800 ;
    PORT
      LAYER Metal3 ;
        RECT 0.000 179.980 0.400 180.380 ;
    END
  END Tile_X0Y1_FrameData[11]
  PIN Tile_X0Y1_FrameData[12]
    DIRECTION INPUT ;
    USE SIGNAL ;
    ANTENNAGATEAREA 2.529800 ;
    PORT
      LAYER Metal3 ;
        RECT 0.000 181.660 0.400 182.060 ;
    END
  END Tile_X0Y1_FrameData[12]
  PIN Tile_X0Y1_FrameData[13]
    DIRECTION INPUT ;
    USE SIGNAL ;
    ANTENNAGATEAREA 2.529800 ;
    PORT
      LAYER Metal3 ;
        RECT 0.000 183.340 0.400 183.740 ;
    END
  END Tile_X0Y1_FrameData[13]
  PIN Tile_X0Y1_FrameData[14]
    DIRECTION INPUT ;
    USE SIGNAL ;
    ANTENNAGATEAREA 2.529800 ;
    PORT
      LAYER Metal3 ;
        RECT 0.000 185.020 0.400 185.420 ;
    END
  END Tile_X0Y1_FrameData[14]
  PIN Tile_X0Y1_FrameData[15]
    DIRECTION INPUT ;
    USE SIGNAL ;
    ANTENNAGATEAREA 2.529800 ;
    PORT
      LAYER Metal3 ;
        RECT 0.000 186.700 0.400 187.100 ;
    END
  END Tile_X0Y1_FrameData[15]
  PIN Tile_X0Y1_FrameData[16]
    DIRECTION INPUT ;
    USE SIGNAL ;
    ANTENNAGATEAREA 2.529800 ;
    PORT
      LAYER Metal3 ;
        RECT 0.000 188.380 0.400 188.780 ;
    END
  END Tile_X0Y1_FrameData[16]
  PIN Tile_X0Y1_FrameData[17]
    DIRECTION INPUT ;
    USE SIGNAL ;
    ANTENNAGATEAREA 2.529800 ;
    PORT
      LAYER Metal3 ;
        RECT 0.000 190.060 0.400 190.460 ;
    END
  END Tile_X0Y1_FrameData[17]
  PIN Tile_X0Y1_FrameData[18]
    DIRECTION INPUT ;
    USE SIGNAL ;
    ANTENNAGATEAREA 2.529800 ;
    PORT
      LAYER Metal3 ;
        RECT 0.000 191.740 0.400 192.140 ;
    END
  END Tile_X0Y1_FrameData[18]
  PIN Tile_X0Y1_FrameData[19]
    DIRECTION INPUT ;
    USE SIGNAL ;
    ANTENNAGATEAREA 2.529800 ;
    PORT
      LAYER Metal3 ;
        RECT 0.000 193.420 0.400 193.820 ;
    END
  END Tile_X0Y1_FrameData[19]
  PIN Tile_X0Y1_FrameData[1]
    DIRECTION INPUT ;
    USE SIGNAL ;
    ANTENNAGATEAREA 2.529800 ;
    PORT
      LAYER Metal3 ;
        RECT 0.000 163.180 0.400 163.580 ;
    END
  END Tile_X0Y1_FrameData[1]
  PIN Tile_X0Y1_FrameData[20]
    DIRECTION INPUT ;
    USE SIGNAL ;
    ANTENNAGATEAREA 2.529800 ;
    PORT
      LAYER Metal3 ;
        RECT 0.000 195.100 0.400 195.500 ;
    END
  END Tile_X0Y1_FrameData[20]
  PIN Tile_X0Y1_FrameData[21]
    DIRECTION INPUT ;
    USE SIGNAL ;
    ANTENNAGATEAREA 2.529800 ;
    PORT
      LAYER Metal3 ;
        RECT 0.000 196.780 0.400 197.180 ;
    END
  END Tile_X0Y1_FrameData[21]
  PIN Tile_X0Y1_FrameData[22]
    DIRECTION INPUT ;
    USE SIGNAL ;
    ANTENNAGATEAREA 2.529800 ;
    PORT
      LAYER Metal3 ;
        RECT 0.000 198.460 0.400 198.860 ;
    END
  END Tile_X0Y1_FrameData[22]
  PIN Tile_X0Y1_FrameData[23]
    DIRECTION INPUT ;
    USE SIGNAL ;
    ANTENNAGATEAREA 2.529800 ;
    PORT
      LAYER Metal3 ;
        RECT 0.000 200.140 0.400 200.540 ;
    END
  END Tile_X0Y1_FrameData[23]
  PIN Tile_X0Y1_FrameData[24]
    DIRECTION INPUT ;
    USE SIGNAL ;
    ANTENNAGATEAREA 2.529800 ;
    PORT
      LAYER Metal3 ;
        RECT 0.000 201.820 0.400 202.220 ;
    END
  END Tile_X0Y1_FrameData[24]
  PIN Tile_X0Y1_FrameData[25]
    DIRECTION INPUT ;
    USE SIGNAL ;
    ANTENNAGATEAREA 2.529800 ;
    PORT
      LAYER Metal3 ;
        RECT 0.000 203.500 0.400 203.900 ;
    END
  END Tile_X0Y1_FrameData[25]
  PIN Tile_X0Y1_FrameData[26]
    DIRECTION INPUT ;
    USE SIGNAL ;
    ANTENNAGATEAREA 2.529800 ;
    PORT
      LAYER Metal3 ;
        RECT 0.000 205.180 0.400 205.580 ;
    END
  END Tile_X0Y1_FrameData[26]
  PIN Tile_X0Y1_FrameData[27]
    DIRECTION INPUT ;
    USE SIGNAL ;
    ANTENNAGATEAREA 2.529800 ;
    PORT
      LAYER Metal3 ;
        RECT 0.000 206.860 0.400 207.260 ;
    END
  END Tile_X0Y1_FrameData[27]
  PIN Tile_X0Y1_FrameData[28]
    DIRECTION INPUT ;
    USE SIGNAL ;
    ANTENNAGATEAREA 2.529800 ;
    PORT
      LAYER Metal3 ;
        RECT 0.000 208.540 0.400 208.940 ;
    END
  END Tile_X0Y1_FrameData[28]
  PIN Tile_X0Y1_FrameData[29]
    DIRECTION INPUT ;
    USE SIGNAL ;
    ANTENNAGATEAREA 2.529800 ;
    PORT
      LAYER Metal3 ;
        RECT 0.000 210.220 0.400 210.620 ;
    END
  END Tile_X0Y1_FrameData[29]
  PIN Tile_X0Y1_FrameData[2]
    DIRECTION INPUT ;
    USE SIGNAL ;
    ANTENNAGATEAREA 2.529800 ;
    PORT
      LAYER Metal3 ;
        RECT 0.000 164.860 0.400 165.260 ;
    END
  END Tile_X0Y1_FrameData[2]
  PIN Tile_X0Y1_FrameData[30]
    DIRECTION INPUT ;
    USE SIGNAL ;
    ANTENNAGATEAREA 2.529800 ;
    PORT
      LAYER Metal3 ;
        RECT 0.000 211.900 0.400 212.300 ;
    END
  END Tile_X0Y1_FrameData[30]
  PIN Tile_X0Y1_FrameData[31]
    DIRECTION INPUT ;
    USE SIGNAL ;
    ANTENNAGATEAREA 2.529800 ;
    PORT
      LAYER Metal3 ;
        RECT 0.000 213.580 0.400 213.980 ;
    END
  END Tile_X0Y1_FrameData[31]
  PIN Tile_X0Y1_FrameData[3]
    DIRECTION INPUT ;
    USE SIGNAL ;
    ANTENNAGATEAREA 2.529800 ;
    PORT
      LAYER Metal3 ;
        RECT 0.000 166.540 0.400 166.940 ;
    END
  END Tile_X0Y1_FrameData[3]
  PIN Tile_X0Y1_FrameData[4]
    DIRECTION INPUT ;
    USE SIGNAL ;
    ANTENNAGATEAREA 11.047400 ;
    ANTENNADIFFAREA 28.215599 ;
    PORT
      LAYER Metal3 ;
        RECT 0.000 168.220 0.400 168.620 ;
    END
  END Tile_X0Y1_FrameData[4]
  PIN Tile_X0Y1_FrameData[5]
    DIRECTION INPUT ;
    USE SIGNAL ;
    ANTENNAGATEAREA 2.529800 ;
    PORT
      LAYER Metal3 ;
        RECT 0.000 169.900 0.400 170.300 ;
    END
  END Tile_X0Y1_FrameData[5]
  PIN Tile_X0Y1_FrameData[6]
    DIRECTION INPUT ;
    USE SIGNAL ;
    ANTENNAGATEAREA 2.529800 ;
    PORT
      LAYER Metal3 ;
        RECT 0.000 171.580 0.400 171.980 ;
    END
  END Tile_X0Y1_FrameData[6]
  PIN Tile_X0Y1_FrameData[7]
    DIRECTION INPUT ;
    USE SIGNAL ;
    ANTENNAGATEAREA 2.529800 ;
    PORT
      LAYER Metal3 ;
        RECT 0.000 173.260 0.400 173.660 ;
    END
  END Tile_X0Y1_FrameData[7]
  PIN Tile_X0Y1_FrameData[8]
    DIRECTION INPUT ;
    USE SIGNAL ;
    ANTENNAGATEAREA 2.529800 ;
    PORT
      LAYER Metal3 ;
        RECT 0.000 174.940 0.400 175.340 ;
    END
  END Tile_X0Y1_FrameData[8]
  PIN Tile_X0Y1_FrameData[9]
    DIRECTION INPUT ;
    USE SIGNAL ;
    ANTENNAGATEAREA 2.529800 ;
    PORT
      LAYER Metal3 ;
        RECT 0.000 176.620 0.400 177.020 ;
    END
  END Tile_X0Y1_FrameData[9]
  PIN Tile_X0Y1_FrameData_O[0]
    DIRECTION OUTPUT ;
    USE SIGNAL ;
    ANTENNADIFFAREA 0.708600 ;
    PORT
      LAYER Metal3 ;
        RECT 184.400 161.500 184.800 161.900 ;
    END
  END Tile_X0Y1_FrameData_O[0]
  PIN Tile_X0Y1_FrameData_O[10]
    DIRECTION OUTPUT ;
    USE SIGNAL ;
    ANTENNADIFFAREA 0.708600 ;
    PORT
      LAYER Metal3 ;
        RECT 184.400 178.300 184.800 178.700 ;
    END
  END Tile_X0Y1_FrameData_O[10]
  PIN Tile_X0Y1_FrameData_O[11]
    DIRECTION OUTPUT ;
    USE SIGNAL ;
    ANTENNADIFFAREA 0.708600 ;
    PORT
      LAYER Metal3 ;
        RECT 184.400 179.980 184.800 180.380 ;
    END
  END Tile_X0Y1_FrameData_O[11]
  PIN Tile_X0Y1_FrameData_O[12]
    DIRECTION OUTPUT ;
    USE SIGNAL ;
    ANTENNADIFFAREA 0.708600 ;
    PORT
      LAYER Metal3 ;
        RECT 184.400 181.660 184.800 182.060 ;
    END
  END Tile_X0Y1_FrameData_O[12]
  PIN Tile_X0Y1_FrameData_O[13]
    DIRECTION OUTPUT ;
    USE SIGNAL ;
    ANTENNADIFFAREA 0.708600 ;
    PORT
      LAYER Metal3 ;
        RECT 184.400 183.340 184.800 183.740 ;
    END
  END Tile_X0Y1_FrameData_O[13]
  PIN Tile_X0Y1_FrameData_O[14]
    DIRECTION OUTPUT ;
    USE SIGNAL ;
    ANTENNADIFFAREA 0.708600 ;
    PORT
      LAYER Metal3 ;
        RECT 184.400 185.020 184.800 185.420 ;
    END
  END Tile_X0Y1_FrameData_O[14]
  PIN Tile_X0Y1_FrameData_O[15]
    DIRECTION OUTPUT ;
    USE SIGNAL ;
    ANTENNADIFFAREA 0.708600 ;
    PORT
      LAYER Metal3 ;
        RECT 184.400 186.700 184.800 187.100 ;
    END
  END Tile_X0Y1_FrameData_O[15]
  PIN Tile_X0Y1_FrameData_O[16]
    DIRECTION OUTPUT ;
    USE SIGNAL ;
    ANTENNADIFFAREA 0.708600 ;
    PORT
      LAYER Metal3 ;
        RECT 184.400 188.380 184.800 188.780 ;
    END
  END Tile_X0Y1_FrameData_O[16]
  PIN Tile_X0Y1_FrameData_O[17]
    DIRECTION OUTPUT ;
    USE SIGNAL ;
    ANTENNADIFFAREA 0.708600 ;
    PORT
      LAYER Metal3 ;
        RECT 184.400 190.060 184.800 190.460 ;
    END
  END Tile_X0Y1_FrameData_O[17]
  PIN Tile_X0Y1_FrameData_O[18]
    DIRECTION OUTPUT ;
    USE SIGNAL ;
    ANTENNADIFFAREA 0.708600 ;
    PORT
      LAYER Metal3 ;
        RECT 184.400 191.740 184.800 192.140 ;
    END
  END Tile_X0Y1_FrameData_O[18]
  PIN Tile_X0Y1_FrameData_O[19]
    DIRECTION OUTPUT ;
    USE SIGNAL ;
    ANTENNADIFFAREA 0.708600 ;
    PORT
      LAYER Metal3 ;
        RECT 184.400 193.420 184.800 193.820 ;
    END
  END Tile_X0Y1_FrameData_O[19]
  PIN Tile_X0Y1_FrameData_O[1]
    DIRECTION OUTPUT ;
    USE SIGNAL ;
    ANTENNADIFFAREA 0.708600 ;
    PORT
      LAYER Metal3 ;
        RECT 184.400 163.180 184.800 163.580 ;
    END
  END Tile_X0Y1_FrameData_O[1]
  PIN Tile_X0Y1_FrameData_O[20]
    DIRECTION OUTPUT ;
    USE SIGNAL ;
    ANTENNADIFFAREA 0.708600 ;
    PORT
      LAYER Metal3 ;
        RECT 184.400 195.100 184.800 195.500 ;
    END
  END Tile_X0Y1_FrameData_O[20]
  PIN Tile_X0Y1_FrameData_O[21]
    DIRECTION OUTPUT ;
    USE SIGNAL ;
    ANTENNADIFFAREA 0.708600 ;
    PORT
      LAYER Metal3 ;
        RECT 184.400 196.780 184.800 197.180 ;
    END
  END Tile_X0Y1_FrameData_O[21]
  PIN Tile_X0Y1_FrameData_O[22]
    DIRECTION OUTPUT ;
    USE SIGNAL ;
    ANTENNADIFFAREA 0.708600 ;
    PORT
      LAYER Metal3 ;
        RECT 184.400 198.460 184.800 198.860 ;
    END
  END Tile_X0Y1_FrameData_O[22]
  PIN Tile_X0Y1_FrameData_O[23]
    DIRECTION OUTPUT ;
    USE SIGNAL ;
    ANTENNADIFFAREA 0.708600 ;
    PORT
      LAYER Metal3 ;
        RECT 184.400 200.140 184.800 200.540 ;
    END
  END Tile_X0Y1_FrameData_O[23]
  PIN Tile_X0Y1_FrameData_O[24]
    DIRECTION OUTPUT ;
    USE SIGNAL ;
    ANTENNADIFFAREA 0.708600 ;
    PORT
      LAYER Metal3 ;
        RECT 184.400 201.820 184.800 202.220 ;
    END
  END Tile_X0Y1_FrameData_O[24]
  PIN Tile_X0Y1_FrameData_O[25]
    DIRECTION OUTPUT ;
    USE SIGNAL ;
    ANTENNADIFFAREA 0.708600 ;
    PORT
      LAYER Metal3 ;
        RECT 184.400 203.500 184.800 203.900 ;
    END
  END Tile_X0Y1_FrameData_O[25]
  PIN Tile_X0Y1_FrameData_O[26]
    DIRECTION OUTPUT ;
    USE SIGNAL ;
    ANTENNADIFFAREA 0.708600 ;
    PORT
      LAYER Metal3 ;
        RECT 184.400 205.180 184.800 205.580 ;
    END
  END Tile_X0Y1_FrameData_O[26]
  PIN Tile_X0Y1_FrameData_O[27]
    DIRECTION OUTPUT ;
    USE SIGNAL ;
    ANTENNADIFFAREA 0.708600 ;
    PORT
      LAYER Metal3 ;
        RECT 184.400 206.860 184.800 207.260 ;
    END
  END Tile_X0Y1_FrameData_O[27]
  PIN Tile_X0Y1_FrameData_O[28]
    DIRECTION OUTPUT ;
    USE SIGNAL ;
    ANTENNADIFFAREA 0.708600 ;
    PORT
      LAYER Metal3 ;
        RECT 184.400 208.540 184.800 208.940 ;
    END
  END Tile_X0Y1_FrameData_O[28]
  PIN Tile_X0Y1_FrameData_O[29]
    DIRECTION OUTPUT ;
    USE SIGNAL ;
    ANTENNADIFFAREA 0.708600 ;
    PORT
      LAYER Metal3 ;
        RECT 184.400 210.220 184.800 210.620 ;
    END
  END Tile_X0Y1_FrameData_O[29]
  PIN Tile_X0Y1_FrameData_O[2]
    DIRECTION OUTPUT ;
    USE SIGNAL ;
    ANTENNADIFFAREA 0.708600 ;
    PORT
      LAYER Metal3 ;
        RECT 184.400 164.860 184.800 165.260 ;
    END
  END Tile_X0Y1_FrameData_O[2]
  PIN Tile_X0Y1_FrameData_O[30]
    DIRECTION OUTPUT ;
    USE SIGNAL ;
    ANTENNADIFFAREA 0.708600 ;
    PORT
      LAYER Metal3 ;
        RECT 184.400 211.900 184.800 212.300 ;
    END
  END Tile_X0Y1_FrameData_O[30]
  PIN Tile_X0Y1_FrameData_O[31]
    DIRECTION OUTPUT ;
    USE SIGNAL ;
    ANTENNADIFFAREA 0.708600 ;
    PORT
      LAYER Metal3 ;
        RECT 184.400 213.580 184.800 213.980 ;
    END
  END Tile_X0Y1_FrameData_O[31]
  PIN Tile_X0Y1_FrameData_O[3]
    DIRECTION OUTPUT ;
    USE SIGNAL ;
    ANTENNADIFFAREA 0.708600 ;
    PORT
      LAYER Metal3 ;
        RECT 184.400 166.540 184.800 166.940 ;
    END
  END Tile_X0Y1_FrameData_O[3]
  PIN Tile_X0Y1_FrameData_O[4]
    DIRECTION OUTPUT ;
    USE SIGNAL ;
    ANTENNADIFFAREA 0.708600 ;
    PORT
      LAYER Metal3 ;
        RECT 184.400 168.220 184.800 168.620 ;
    END
  END Tile_X0Y1_FrameData_O[4]
  PIN Tile_X0Y1_FrameData_O[5]
    DIRECTION OUTPUT ;
    USE SIGNAL ;
    ANTENNADIFFAREA 0.708600 ;
    PORT
      LAYER Metal3 ;
        RECT 184.400 169.900 184.800 170.300 ;
    END
  END Tile_X0Y1_FrameData_O[5]
  PIN Tile_X0Y1_FrameData_O[6]
    DIRECTION OUTPUT ;
    USE SIGNAL ;
    ANTENNADIFFAREA 0.708600 ;
    PORT
      LAYER Metal3 ;
        RECT 184.400 171.580 184.800 171.980 ;
    END
  END Tile_X0Y1_FrameData_O[6]
  PIN Tile_X0Y1_FrameData_O[7]
    DIRECTION OUTPUT ;
    USE SIGNAL ;
    ANTENNADIFFAREA 0.708600 ;
    PORT
      LAYER Metal3 ;
        RECT 184.400 173.260 184.800 173.660 ;
    END
  END Tile_X0Y1_FrameData_O[7]
  PIN Tile_X0Y1_FrameData_O[8]
    DIRECTION OUTPUT ;
    USE SIGNAL ;
    ANTENNADIFFAREA 0.708600 ;
    PORT
      LAYER Metal3 ;
        RECT 184.400 174.940 184.800 175.340 ;
    END
  END Tile_X0Y1_FrameData_O[8]
  PIN Tile_X0Y1_FrameData_O[9]
    DIRECTION OUTPUT ;
    USE SIGNAL ;
    ANTENNADIFFAREA 0.708600 ;
    PORT
      LAYER Metal3 ;
        RECT 184.400 176.620 184.800 177.020 ;
    END
  END Tile_X0Y1_FrameData_O[9]
  PIN Tile_X0Y1_FrameStrobe[0]
    DIRECTION INPUT ;
    USE SIGNAL ;
    ANTENNAGATEAREA 13.326300 ;
    PORT
      LAYER Metal2 ;
        RECT 132.760 0.000 133.160 0.400 ;
    END
  END Tile_X0Y1_FrameStrobe[0]
  PIN Tile_X0Y1_FrameStrobe[10]
    DIRECTION INPUT ;
    USE SIGNAL ;
    ANTENNAGATEAREA 13.326300 ;
    PORT
      LAYER Metal2 ;
        RECT 142.360 0.000 142.760 0.400 ;
    END
  END Tile_X0Y1_FrameStrobe[10]
  PIN Tile_X0Y1_FrameStrobe[11]
    DIRECTION INPUT ;
    USE SIGNAL ;
    ANTENNAGATEAREA 13.326300 ;
    PORT
      LAYER Metal2 ;
        RECT 143.320 0.000 143.720 0.400 ;
    END
  END Tile_X0Y1_FrameStrobe[11]
  PIN Tile_X0Y1_FrameStrobe[12]
    DIRECTION INPUT ;
    USE SIGNAL ;
    ANTENNAGATEAREA 11.272300 ;
    PORT
      LAYER Metal2 ;
        RECT 144.280 0.000 144.680 0.400 ;
    END
  END Tile_X0Y1_FrameStrobe[12]
  PIN Tile_X0Y1_FrameStrobe[13]
    DIRECTION INPUT ;
    USE SIGNAL ;
    ANTENNAGATEAREA 1.397500 ;
    ANTENNADIFFAREA 4.030800 ;
    PORT
      LAYER Metal2 ;
        RECT 145.240 0.000 145.640 0.400 ;
    END
  END Tile_X0Y1_FrameStrobe[13]
  PIN Tile_X0Y1_FrameStrobe[14]
    DIRECTION INPUT ;
    USE SIGNAL ;
    ANTENNAGATEAREA 0.180700 ;
    PORT
      LAYER Metal2 ;
        RECT 146.200 0.000 146.600 0.400 ;
    END
  END Tile_X0Y1_FrameStrobe[14]
  PIN Tile_X0Y1_FrameStrobe[15]
    DIRECTION INPUT ;
    USE SIGNAL ;
    ANTENNAGATEAREA 0.789100 ;
    ANTENNADIFFAREA 2.015400 ;
    PORT
      LAYER Metal2 ;
        RECT 147.160 0.000 147.560 0.400 ;
    END
  END Tile_X0Y1_FrameStrobe[15]
  PIN Tile_X0Y1_FrameStrobe[16]
    DIRECTION INPUT ;
    USE SIGNAL ;
    ANTENNAGATEAREA 0.789100 ;
    ANTENNADIFFAREA 2.015400 ;
    PORT
      LAYER Metal2 ;
        RECT 148.120 0.000 148.520 0.400 ;
    END
  END Tile_X0Y1_FrameStrobe[16]
  PIN Tile_X0Y1_FrameStrobe[17]
    DIRECTION INPUT ;
    USE SIGNAL ;
    ANTENNAGATEAREA 0.789100 ;
    ANTENNADIFFAREA 2.015400 ;
    PORT
      LAYER Metal2 ;
        RECT 149.080 0.000 149.480 0.400 ;
    END
  END Tile_X0Y1_FrameStrobe[17]
  PIN Tile_X0Y1_FrameStrobe[18]
    DIRECTION INPUT ;
    USE SIGNAL ;
    ANTENNAGATEAREA 0.789100 ;
    ANTENNADIFFAREA 2.015400 ;
    PORT
      LAYER Metal2 ;
        RECT 150.040 0.000 150.440 0.400 ;
    END
  END Tile_X0Y1_FrameStrobe[18]
  PIN Tile_X0Y1_FrameStrobe[19]
    DIRECTION INPUT ;
    USE SIGNAL ;
    ANTENNAGATEAREA 0.789100 ;
    ANTENNADIFFAREA 2.015400 ;
    PORT
      LAYER Metal2 ;
        RECT 151.000 0.000 151.400 0.400 ;
    END
  END Tile_X0Y1_FrameStrobe[19]
  PIN Tile_X0Y1_FrameStrobe[1]
    DIRECTION INPUT ;
    USE SIGNAL ;
    ANTENNAGATEAREA 13.326300 ;
    PORT
      LAYER Metal2 ;
        RECT 133.720 0.000 134.120 0.400 ;
    END
  END Tile_X0Y1_FrameStrobe[1]
  PIN Tile_X0Y1_FrameStrobe[2]
    DIRECTION INPUT ;
    USE SIGNAL ;
    ANTENNAGATEAREA 13.326300 ;
    PORT
      LAYER Metal2 ;
        RECT 134.680 0.000 135.080 0.400 ;
    END
  END Tile_X0Y1_FrameStrobe[2]
  PIN Tile_X0Y1_FrameStrobe[3]
    DIRECTION INPUT ;
    USE SIGNAL ;
    ANTENNAGATEAREA 13.326300 ;
    PORT
      LAYER Metal2 ;
        RECT 135.640 0.000 136.040 0.400 ;
    END
  END Tile_X0Y1_FrameStrobe[3]
  PIN Tile_X0Y1_FrameStrobe[4]
    DIRECTION INPUT ;
    USE SIGNAL ;
    ANTENNAGATEAREA 13.326300 ;
    PORT
      LAYER Metal2 ;
        RECT 136.600 0.000 137.000 0.400 ;
    END
  END Tile_X0Y1_FrameStrobe[4]
  PIN Tile_X0Y1_FrameStrobe[5]
    DIRECTION INPUT ;
    USE SIGNAL ;
    ANTENNAGATEAREA 13.326300 ;
    PORT
      LAYER Metal2 ;
        RECT 137.560 0.000 137.960 0.400 ;
    END
  END Tile_X0Y1_FrameStrobe[5]
  PIN Tile_X0Y1_FrameStrobe[6]
    DIRECTION INPUT ;
    USE SIGNAL ;
    ANTENNAGATEAREA 13.326300 ;
    PORT
      LAYER Metal2 ;
        RECT 138.520 0.000 138.920 0.400 ;
    END
  END Tile_X0Y1_FrameStrobe[6]
  PIN Tile_X0Y1_FrameStrobe[7]
    DIRECTION INPUT ;
    USE SIGNAL ;
    ANTENNAGATEAREA 13.326300 ;
    PORT
      LAYER Metal2 ;
        RECT 139.480 0.000 139.880 0.400 ;
    END
  END Tile_X0Y1_FrameStrobe[7]
  PIN Tile_X0Y1_FrameStrobe[8]
    DIRECTION INPUT ;
    USE SIGNAL ;
    ANTENNAGATEAREA 13.326300 ;
    PORT
      LAYER Metal2 ;
        RECT 140.440 0.000 140.840 0.400 ;
    END
  END Tile_X0Y1_FrameStrobe[8]
  PIN Tile_X0Y1_FrameStrobe[9]
    DIRECTION INPUT ;
    USE SIGNAL ;
    ANTENNAGATEAREA 13.326300 ;
    PORT
      LAYER Metal2 ;
        RECT 141.400 0.000 141.800 0.400 ;
    END
  END Tile_X0Y1_FrameStrobe[9]
  PIN Tile_X0Y1_N1END[0]
    DIRECTION INPUT ;
    USE SIGNAL ;
    ANTENNAGATEAREA 2.099500 ;
    PORT
      LAYER Metal2 ;
        RECT 31.960 0.000 32.360 0.400 ;
    END
  END Tile_X0Y1_N1END[0]
  PIN Tile_X0Y1_N1END[1]
    DIRECTION INPUT ;
    USE SIGNAL ;
    ANTENNAGATEAREA 2.132000 ;
    PORT
      LAYER Metal2 ;
        RECT 32.920 0.000 33.320 0.400 ;
    END
  END Tile_X0Y1_N1END[1]
  PIN Tile_X0Y1_N1END[2]
    DIRECTION INPUT ;
    USE SIGNAL ;
    ANTENNAGATEAREA 2.145000 ;
    PORT
      LAYER Metal2 ;
        RECT 33.880 0.000 34.280 0.400 ;
    END
  END Tile_X0Y1_N1END[2]
  PIN Tile_X0Y1_N1END[3]
    DIRECTION INPUT ;
    USE SIGNAL ;
    ANTENNAGATEAREA 2.132000 ;
    PORT
      LAYER Metal2 ;
        RECT 34.840 0.000 35.240 0.400 ;
    END
  END Tile_X0Y1_N1END[3]
  PIN Tile_X0Y1_N2END[0]
    DIRECTION INPUT ;
    USE SIGNAL ;
    ANTENNAGATEAREA 1.492400 ;
    PORT
      LAYER Metal2 ;
        RECT 43.480 0.000 43.880 0.400 ;
    END
  END Tile_X0Y1_N2END[0]
  PIN Tile_X0Y1_N2END[1]
    DIRECTION INPUT ;
    USE SIGNAL ;
    ANTENNAGATEAREA 1.066000 ;
    PORT
      LAYER Metal2 ;
        RECT 44.440 0.000 44.840 0.400 ;
    END
  END Tile_X0Y1_N2END[1]
  PIN Tile_X0Y1_N2END[2]
    DIRECTION INPUT ;
    USE SIGNAL ;
    ANTENNAGATEAREA 1.094600 ;
    PORT
      LAYER Metal2 ;
        RECT 45.400 0.000 45.800 0.400 ;
    END
  END Tile_X0Y1_N2END[2]
  PIN Tile_X0Y1_N2END[3]
    DIRECTION INPUT ;
    USE SIGNAL ;
    ANTENNAGATEAREA 1.279200 ;
    PORT
      LAYER Metal2 ;
        RECT 46.360 0.000 46.760 0.400 ;
    END
  END Tile_X0Y1_N2END[3]
  PIN Tile_X0Y1_N2END[4]
    DIRECTION INPUT ;
    USE SIGNAL ;
    ANTENNAGATEAREA 1.305200 ;
    PORT
      LAYER Metal2 ;
        RECT 47.320 0.000 47.720 0.400 ;
    END
  END Tile_X0Y1_N2END[4]
  PIN Tile_X0Y1_N2END[5]
    DIRECTION INPUT ;
    USE SIGNAL ;
    ANTENNAGATEAREA 1.066000 ;
    PORT
      LAYER Metal2 ;
        RECT 48.280 0.000 48.680 0.400 ;
    END
  END Tile_X0Y1_N2END[5]
  PIN Tile_X0Y1_N2END[6]
    DIRECTION INPUT ;
    USE SIGNAL ;
    ANTENNAGATEAREA 1.066000 ;
    PORT
      LAYER Metal2 ;
        RECT 49.240 0.000 49.640 0.400 ;
    END
  END Tile_X0Y1_N2END[6]
  PIN Tile_X0Y1_N2END[7]
    DIRECTION INPUT ;
    USE SIGNAL ;
    ANTENNAGATEAREA 1.279200 ;
    PORT
      LAYER Metal2 ;
        RECT 50.200 0.000 50.600 0.400 ;
    END
  END Tile_X0Y1_N2END[7]
  PIN Tile_X0Y1_N2MID[0]
    DIRECTION INPUT ;
    USE SIGNAL ;
    ANTENNAGATEAREA 1.848600 ;
    PORT
      LAYER Metal2 ;
        RECT 35.800 0.000 36.200 0.400 ;
    END
  END Tile_X0Y1_N2MID[0]
  PIN Tile_X0Y1_N2MID[1]
    DIRECTION INPUT ;
    USE SIGNAL ;
    ANTENNAGATEAREA 2.140900 ;
    PORT
      LAYER Metal2 ;
        RECT 36.760 0.000 37.160 0.400 ;
    END
  END Tile_X0Y1_N2MID[1]
  PIN Tile_X0Y1_N2MID[2]
    DIRECTION INPUT ;
    USE SIGNAL ;
    ANTENNAGATEAREA 1.804400 ;
    PORT
      LAYER Metal2 ;
        RECT 37.720 0.000 38.120 0.400 ;
    END
  END Tile_X0Y1_N2MID[2]
  PIN Tile_X0Y1_N2MID[3]
    DIRECTION INPUT ;
    USE SIGNAL ;
    ANTENNAGATEAREA 11.468599 ;
    ANTENNADIFFAREA 32.246399 ;
    PORT
      LAYER Metal2 ;
        RECT 38.680 0.000 39.080 0.400 ;
    END
  END Tile_X0Y1_N2MID[3]
  PIN Tile_X0Y1_N2MID[4]
    DIRECTION INPUT ;
    USE SIGNAL ;
    ANTENNAGATEAREA 1.521000 ;
    PORT
      LAYER Metal2 ;
        RECT 39.640 0.000 40.040 0.400 ;
    END
  END Tile_X0Y1_N2MID[4]
  PIN Tile_X0Y1_N2MID[5]
    DIRECTION INPUT ;
    USE SIGNAL ;
    ANTENNAGATEAREA 2.033200 ;
    PORT
      LAYER Metal2 ;
        RECT 40.600 0.000 41.000 0.400 ;
    END
  END Tile_X0Y1_N2MID[5]
  PIN Tile_X0Y1_N2MID[6]
    DIRECTION INPUT ;
    USE SIGNAL ;
    ANTENNAGATEAREA 2.013200 ;
    PORT
      LAYER Metal2 ;
        RECT 41.560 0.000 41.960 0.400 ;
    END
  END Tile_X0Y1_N2MID[6]
  PIN Tile_X0Y1_N2MID[7]
    DIRECTION INPUT ;
    USE SIGNAL ;
    ANTENNAGATEAREA 2.443800 ;
    PORT
      LAYER Metal2 ;
        RECT 42.520 0.000 42.920 0.400 ;
    END
  END Tile_X0Y1_N2MID[7]
  PIN Tile_X0Y1_N4END[0]
    DIRECTION INPUT ;
    USE SIGNAL ;
    ANTENNAGATEAREA 1.079800 ;
    PORT
      LAYER Metal2 ;
        RECT 51.160 0.000 51.560 0.400 ;
    END
  END Tile_X0Y1_N4END[0]
  PIN Tile_X0Y1_N4END[10]
    DIRECTION INPUT ;
    USE SIGNAL ;
    ANTENNAGATEAREA 0.789100 ;
    ANTENNADIFFAREA 2.015400 ;
    PORT
      LAYER Metal2 ;
        RECT 60.760 0.000 61.160 0.400 ;
    END
  END Tile_X0Y1_N4END[10]
  PIN Tile_X0Y1_N4END[11]
    DIRECTION INPUT ;
    USE SIGNAL ;
    ANTENNAGATEAREA 2.005900 ;
    ANTENNADIFFAREA 6.046200 ;
    PORT
      LAYER Metal2 ;
        RECT 61.720 0.000 62.120 0.400 ;
    END
  END Tile_X0Y1_N4END[11]
  PIN Tile_X0Y1_N4END[12]
    DIRECTION INPUT ;
    USE SIGNAL ;
    ANTENNAGATEAREA 2.005900 ;
    ANTENNADIFFAREA 6.046200 ;
    PORT
      LAYER Metal2 ;
        RECT 62.680 0.000 63.080 0.400 ;
    END
  END Tile_X0Y1_N4END[12]
  PIN Tile_X0Y1_N4END[13]
    DIRECTION INPUT ;
    USE SIGNAL ;
    ANTENNAGATEAREA 0.789100 ;
    ANTENNADIFFAREA 2.015400 ;
    PORT
      LAYER Metal2 ;
        RECT 63.640 0.000 64.040 0.400 ;
    END
  END Tile_X0Y1_N4END[13]
  PIN Tile_X0Y1_N4END[14]
    DIRECTION INPUT ;
    USE SIGNAL ;
    ANTENNAGATEAREA 0.180700 ;
    PORT
      LAYER Metal2 ;
        RECT 64.600 0.000 65.000 0.400 ;
    END
  END Tile_X0Y1_N4END[14]
  PIN Tile_X0Y1_N4END[15]
    DIRECTION INPUT ;
    USE SIGNAL ;
    ANTENNAGATEAREA 0.789100 ;
    ANTENNADIFFAREA 2.015400 ;
    PORT
      LAYER Metal2 ;
        RECT 65.560 0.000 65.960 0.400 ;
    END
  END Tile_X0Y1_N4END[15]
  PIN Tile_X0Y1_N4END[1]
    DIRECTION INPUT ;
    USE SIGNAL ;
    ANTENNAGATEAREA 1.066000 ;
    PORT
      LAYER Metal2 ;
        RECT 52.120 0.000 52.520 0.400 ;
    END
  END Tile_X0Y1_N4END[1]
  PIN Tile_X0Y1_N4END[2]
    DIRECTION INPUT ;
    USE SIGNAL ;
    ANTENNAGATEAREA 1.033500 ;
    PORT
      LAYER Metal2 ;
        RECT 53.080 0.000 53.480 0.400 ;
    END
  END Tile_X0Y1_N4END[2]
  PIN Tile_X0Y1_N4END[3]
    DIRECTION INPUT ;
    USE SIGNAL ;
    ANTENNAGATEAREA 1.001000 ;
    PORT
      LAYER Metal2 ;
        RECT 54.040 0.000 54.440 0.400 ;
    END
  END Tile_X0Y1_N4END[3]
  PIN Tile_X0Y1_N4END[4]
    DIRECTION INPUT ;
    USE SIGNAL ;
    ANTENNAGATEAREA 7.693400 ;
    ANTENNADIFFAREA 22.169399 ;
    PORT
      LAYER Metal2 ;
        RECT 55.000 0.000 55.400 0.400 ;
    END
  END Tile_X0Y1_N4END[4]
  PIN Tile_X0Y1_N4END[5]
    DIRECTION INPUT ;
    USE SIGNAL ;
    ANTENNAGATEAREA 1.075100 ;
    PORT
      LAYER Metal2 ;
        RECT 55.960 0.000 56.360 0.400 ;
    END
  END Tile_X0Y1_N4END[5]
  PIN Tile_X0Y1_N4END[6]
    DIRECTION INPUT ;
    USE SIGNAL ;
    ANTENNAGATEAREA 1.001000 ;
    PORT
      LAYER Metal2 ;
        RECT 56.920 0.000 57.320 0.400 ;
    END
  END Tile_X0Y1_N4END[6]
  PIN Tile_X0Y1_N4END[7]
    DIRECTION INPUT ;
    USE SIGNAL ;
    ANTENNAGATEAREA 1.014000 ;
    PORT
      LAYER Metal2 ;
        RECT 57.880 0.000 58.280 0.400 ;
    END
  END Tile_X0Y1_N4END[7]
  PIN Tile_X0Y1_N4END[8]
    DIRECTION INPUT ;
    USE SIGNAL ;
    ANTENNAGATEAREA 0.789100 ;
    ANTENNADIFFAREA 2.015400 ;
    PORT
      LAYER Metal2 ;
        RECT 58.840 0.000 59.240 0.400 ;
    END
  END Tile_X0Y1_N4END[8]
  PIN Tile_X0Y1_N4END[9]
    DIRECTION INPUT ;
    USE SIGNAL ;
    ANTENNAGATEAREA 0.789100 ;
    ANTENNADIFFAREA 2.015400 ;
    PORT
      LAYER Metal2 ;
        RECT 59.800 0.000 60.200 0.400 ;
    END
  END Tile_X0Y1_N4END[9]
  PIN Tile_X0Y1_NN4END[0]
    DIRECTION INPUT ;
    USE SIGNAL ;
    ANTENNAGATEAREA 0.426400 ;
    PORT
      LAYER Metal2 ;
        RECT 66.520 0.000 66.920 0.400 ;
    END
  END Tile_X0Y1_NN4END[0]
  PIN Tile_X0Y1_NN4END[10]
    DIRECTION INPUT ;
    USE SIGNAL ;
    ANTENNAGATEAREA 0.789100 ;
    ANTENNADIFFAREA 2.015400 ;
    PORT
      LAYER Metal2 ;
        RECT 76.120 0.000 76.520 0.400 ;
    END
  END Tile_X0Y1_NN4END[10]
  PIN Tile_X0Y1_NN4END[11]
    DIRECTION INPUT ;
    USE SIGNAL ;
    ANTENNAGATEAREA 0.180700 ;
    PORT
      LAYER Metal2 ;
        RECT 77.080 0.000 77.480 0.400 ;
    END
  END Tile_X0Y1_NN4END[11]
  PIN Tile_X0Y1_NN4END[12]
    DIRECTION INPUT ;
    USE SIGNAL ;
    ANTENNAGATEAREA 0.180700 ;
    PORT
      LAYER Metal2 ;
        RECT 78.040 0.000 78.440 0.400 ;
    END
  END Tile_X0Y1_NN4END[12]
  PIN Tile_X0Y1_NN4END[13]
    DIRECTION INPUT ;
    USE SIGNAL ;
    ANTENNAGATEAREA 0.180700 ;
    PORT
      LAYER Metal2 ;
        RECT 79.000 0.000 79.400 0.400 ;
    END
  END Tile_X0Y1_NN4END[13]
  PIN Tile_X0Y1_NN4END[14]
    DIRECTION INPUT ;
    USE SIGNAL ;
    ANTENNAGATEAREA 0.180700 ;
    PORT
      LAYER Metal2 ;
        RECT 79.960 0.000 80.360 0.400 ;
    END
  END Tile_X0Y1_NN4END[14]
  PIN Tile_X0Y1_NN4END[15]
    DIRECTION INPUT ;
    USE SIGNAL ;
    ANTENNAGATEAREA 0.180700 ;
    PORT
      LAYER Metal2 ;
        RECT 80.920 0.000 81.320 0.400 ;
    END
  END Tile_X0Y1_NN4END[15]
  PIN Tile_X0Y1_NN4END[1]
    DIRECTION INPUT ;
    USE SIGNAL ;
    ANTENNAGATEAREA 0.607100 ;
    PORT
      LAYER Metal2 ;
        RECT 67.480 0.000 67.880 0.400 ;
    END
  END Tile_X0Y1_NN4END[1]
  PIN Tile_X0Y1_NN4END[2]
    DIRECTION INPUT ;
    USE SIGNAL ;
    ANTENNAGATEAREA 0.639600 ;
    PORT
      LAYER Metal2 ;
        RECT 68.440 0.000 68.840 0.400 ;
    END
  END Tile_X0Y1_NN4END[2]
  PIN Tile_X0Y1_NN4END[3]
    DIRECTION INPUT ;
    USE SIGNAL ;
    ANTENNAGATEAREA 0.639600 ;
    PORT
      LAYER Metal2 ;
        RECT 69.400 0.000 69.800 0.400 ;
    END
  END Tile_X0Y1_NN4END[3]
  PIN Tile_X0Y1_NN4END[4]
    DIRECTION INPUT ;
    USE SIGNAL ;
    ANTENNAGATEAREA 0.426400 ;
    PORT
      LAYER Metal2 ;
        RECT 70.360 0.000 70.760 0.400 ;
    END
  END Tile_X0Y1_NN4END[4]
  PIN Tile_X0Y1_NN4END[5]
    DIRECTION INPUT ;
    USE SIGNAL ;
    ANTENNAGATEAREA 0.668200 ;
    PORT
      LAYER Metal2 ;
        RECT 71.320 0.000 71.720 0.400 ;
    END
  END Tile_X0Y1_NN4END[5]
  PIN Tile_X0Y1_NN4END[6]
    DIRECTION INPUT ;
    USE SIGNAL ;
    ANTENNAGATEAREA 0.705400 ;
    PORT
      LAYER Metal2 ;
        RECT 72.280 0.000 72.680 0.400 ;
    END
  END Tile_X0Y1_NN4END[6]
  PIN Tile_X0Y1_NN4END[7]
    DIRECTION INPUT ;
    USE SIGNAL ;
    ANTENNAGATEAREA 3.073200 ;
    ANTENNADIFFAREA 8.061600 ;
    PORT
      LAYER Metal2 ;
        RECT 73.240 0.000 73.640 0.400 ;
    END
  END Tile_X0Y1_NN4END[7]
  PIN Tile_X0Y1_NN4END[8]
    DIRECTION INPUT ;
    USE SIGNAL ;
    ANTENNAGATEAREA 0.180700 ;
    PORT
      LAYER Metal2 ;
        RECT 74.200 0.000 74.600 0.400 ;
    END
  END Tile_X0Y1_NN4END[8]
  PIN Tile_X0Y1_NN4END[9]
    DIRECTION INPUT ;
    USE SIGNAL ;
    ANTENNAGATEAREA 0.789100 ;
    ANTENNADIFFAREA 2.015400 ;
    PORT
      LAYER Metal2 ;
        RECT 75.160 0.000 75.560 0.400 ;
    END
  END Tile_X0Y1_NN4END[9]
  PIN Tile_X0Y1_S1BEG[0]
    DIRECTION OUTPUT ;
    USE SIGNAL ;
    ANTENNADIFFAREA 0.708600 ;
    PORT
      LAYER Metal2 ;
        RECT 81.880 0.000 82.280 0.400 ;
    END
  END Tile_X0Y1_S1BEG[0]
  PIN Tile_X0Y1_S1BEG[1]
    DIRECTION OUTPUT ;
    USE SIGNAL ;
    ANTENNADIFFAREA 0.708600 ;
    PORT
      LAYER Metal2 ;
        RECT 82.840 0.000 83.240 0.400 ;
    END
  END Tile_X0Y1_S1BEG[1]
  PIN Tile_X0Y1_S1BEG[2]
    DIRECTION OUTPUT ;
    USE SIGNAL ;
    ANTENNADIFFAREA 0.708600 ;
    PORT
      LAYER Metal2 ;
        RECT 83.800 0.000 84.200 0.400 ;
    END
  END Tile_X0Y1_S1BEG[2]
  PIN Tile_X0Y1_S1BEG[3]
    DIRECTION OUTPUT ;
    USE SIGNAL ;
    ANTENNADIFFAREA 0.708600 ;
    PORT
      LAYER Metal2 ;
        RECT 84.760 0.000 85.160 0.400 ;
    END
  END Tile_X0Y1_S1BEG[3]
  PIN Tile_X0Y1_S2BEG[0]
    DIRECTION OUTPUT ;
    USE SIGNAL ;
    ANTENNADIFFAREA 0.708600 ;
    PORT
      LAYER Metal2 ;
        RECT 85.720 0.000 86.120 0.400 ;
    END
  END Tile_X0Y1_S2BEG[0]
  PIN Tile_X0Y1_S2BEG[1]
    DIRECTION OUTPUT ;
    USE SIGNAL ;
    ANTENNADIFFAREA 0.708600 ;
    PORT
      LAYER Metal2 ;
        RECT 86.680 0.000 87.080 0.400 ;
    END
  END Tile_X0Y1_S2BEG[1]
  PIN Tile_X0Y1_S2BEG[2]
    DIRECTION OUTPUT ;
    USE SIGNAL ;
    ANTENNADIFFAREA 0.708600 ;
    PORT
      LAYER Metal2 ;
        RECT 87.640 0.000 88.040 0.400 ;
    END
  END Tile_X0Y1_S2BEG[2]
  PIN Tile_X0Y1_S2BEG[3]
    DIRECTION OUTPUT ;
    USE SIGNAL ;
    ANTENNADIFFAREA 0.708600 ;
    PORT
      LAYER Metal2 ;
        RECT 88.600 0.000 89.000 0.400 ;
    END
  END Tile_X0Y1_S2BEG[3]
  PIN Tile_X0Y1_S2BEG[4]
    DIRECTION OUTPUT ;
    USE SIGNAL ;
    ANTENNADIFFAREA 0.708600 ;
    PORT
      LAYER Metal2 ;
        RECT 89.560 0.000 89.960 0.400 ;
    END
  END Tile_X0Y1_S2BEG[4]
  PIN Tile_X0Y1_S2BEG[5]
    DIRECTION OUTPUT ;
    USE SIGNAL ;
    ANTENNADIFFAREA 0.708600 ;
    PORT
      LAYER Metal2 ;
        RECT 90.520 0.000 90.920 0.400 ;
    END
  END Tile_X0Y1_S2BEG[5]
  PIN Tile_X0Y1_S2BEG[6]
    DIRECTION OUTPUT ;
    USE SIGNAL ;
    ANTENNADIFFAREA 0.708600 ;
    PORT
      LAYER Metal2 ;
        RECT 91.480 0.000 91.880 0.400 ;
    END
  END Tile_X0Y1_S2BEG[6]
  PIN Tile_X0Y1_S2BEG[7]
    DIRECTION OUTPUT ;
    USE SIGNAL ;
    ANTENNADIFFAREA 0.708600 ;
    PORT
      LAYER Metal2 ;
        RECT 92.440 0.000 92.840 0.400 ;
    END
  END Tile_X0Y1_S2BEG[7]
  PIN Tile_X0Y1_S2BEGb[0]
    DIRECTION OUTPUT ;
    USE SIGNAL ;
    ANTENNADIFFAREA 0.708600 ;
    PORT
      LAYER Metal2 ;
        RECT 93.400 0.000 93.800 0.400 ;
    END
  END Tile_X0Y1_S2BEGb[0]
  PIN Tile_X0Y1_S2BEGb[1]
    DIRECTION OUTPUT ;
    USE SIGNAL ;
    ANTENNADIFFAREA 0.708600 ;
    PORT
      LAYER Metal2 ;
        RECT 94.360 0.000 94.760 0.400 ;
    END
  END Tile_X0Y1_S2BEGb[1]
  PIN Tile_X0Y1_S2BEGb[2]
    DIRECTION OUTPUT ;
    USE SIGNAL ;
    ANTENNADIFFAREA 0.708600 ;
    PORT
      LAYER Metal2 ;
        RECT 95.320 0.000 95.720 0.400 ;
    END
  END Tile_X0Y1_S2BEGb[2]
  PIN Tile_X0Y1_S2BEGb[3]
    DIRECTION OUTPUT ;
    USE SIGNAL ;
    ANTENNADIFFAREA 0.708600 ;
    PORT
      LAYER Metal2 ;
        RECT 96.280 0.000 96.680 0.400 ;
    END
  END Tile_X0Y1_S2BEGb[3]
  PIN Tile_X0Y1_S2BEGb[4]
    DIRECTION OUTPUT ;
    USE SIGNAL ;
    ANTENNADIFFAREA 0.708600 ;
    PORT
      LAYER Metal2 ;
        RECT 97.240 0.000 97.640 0.400 ;
    END
  END Tile_X0Y1_S2BEGb[4]
  PIN Tile_X0Y1_S2BEGb[5]
    DIRECTION OUTPUT ;
    USE SIGNAL ;
    ANTENNADIFFAREA 0.708600 ;
    PORT
      LAYER Metal2 ;
        RECT 98.200 0.000 98.600 0.400 ;
    END
  END Tile_X0Y1_S2BEGb[5]
  PIN Tile_X0Y1_S2BEGb[6]
    DIRECTION OUTPUT ;
    USE SIGNAL ;
    ANTENNADIFFAREA 0.708600 ;
    PORT
      LAYER Metal2 ;
        RECT 99.160 0.000 99.560 0.400 ;
    END
  END Tile_X0Y1_S2BEGb[6]
  PIN Tile_X0Y1_S2BEGb[7]
    DIRECTION OUTPUT ;
    USE SIGNAL ;
    ANTENNADIFFAREA 0.708600 ;
    PORT
      LAYER Metal2 ;
        RECT 100.120 0.000 100.520 0.400 ;
    END
  END Tile_X0Y1_S2BEGb[7]
  PIN Tile_X0Y1_S4BEG[0]
    DIRECTION OUTPUT ;
    USE SIGNAL ;
    ANTENNADIFFAREA 0.708600 ;
    PORT
      LAYER Metal2 ;
        RECT 101.080 0.000 101.480 0.400 ;
    END
  END Tile_X0Y1_S4BEG[0]
  PIN Tile_X0Y1_S4BEG[10]
    DIRECTION OUTPUT ;
    USE SIGNAL ;
    ANTENNADIFFAREA 0.708600 ;
    PORT
      LAYER Metal2 ;
        RECT 110.680 0.000 111.080 0.400 ;
    END
  END Tile_X0Y1_S4BEG[10]
  PIN Tile_X0Y1_S4BEG[11]
    DIRECTION OUTPUT ;
    USE SIGNAL ;
    ANTENNADIFFAREA 0.708600 ;
    PORT
      LAYER Metal2 ;
        RECT 111.640 0.000 112.040 0.400 ;
    END
  END Tile_X0Y1_S4BEG[11]
  PIN Tile_X0Y1_S4BEG[12]
    DIRECTION OUTPUT ;
    USE SIGNAL ;
    ANTENNADIFFAREA 0.708600 ;
    PORT
      LAYER Metal2 ;
        RECT 112.600 0.000 113.000 0.400 ;
    END
  END Tile_X0Y1_S4BEG[12]
  PIN Tile_X0Y1_S4BEG[13]
    DIRECTION OUTPUT ;
    USE SIGNAL ;
    ANTENNADIFFAREA 0.708600 ;
    PORT
      LAYER Metal2 ;
        RECT 113.560 0.000 113.960 0.400 ;
    END
  END Tile_X0Y1_S4BEG[13]
  PIN Tile_X0Y1_S4BEG[14]
    DIRECTION OUTPUT ;
    USE SIGNAL ;
    ANTENNADIFFAREA 0.708600 ;
    PORT
      LAYER Metal2 ;
        RECT 114.520 0.000 114.920 0.400 ;
    END
  END Tile_X0Y1_S4BEG[14]
  PIN Tile_X0Y1_S4BEG[15]
    DIRECTION OUTPUT ;
    USE SIGNAL ;
    ANTENNADIFFAREA 0.708600 ;
    PORT
      LAYER Metal2 ;
        RECT 115.480 0.000 115.880 0.400 ;
    END
  END Tile_X0Y1_S4BEG[15]
  PIN Tile_X0Y1_S4BEG[1]
    DIRECTION OUTPUT ;
    USE SIGNAL ;
    ANTENNADIFFAREA 0.708600 ;
    PORT
      LAYER Metal2 ;
        RECT 102.040 0.000 102.440 0.400 ;
    END
  END Tile_X0Y1_S4BEG[1]
  PIN Tile_X0Y1_S4BEG[2]
    DIRECTION OUTPUT ;
    USE SIGNAL ;
    ANTENNADIFFAREA 0.708600 ;
    PORT
      LAYER Metal2 ;
        RECT 103.000 0.000 103.400 0.400 ;
    END
  END Tile_X0Y1_S4BEG[2]
  PIN Tile_X0Y1_S4BEG[3]
    DIRECTION OUTPUT ;
    USE SIGNAL ;
    ANTENNADIFFAREA 0.708600 ;
    PORT
      LAYER Metal2 ;
        RECT 103.960 0.000 104.360 0.400 ;
    END
  END Tile_X0Y1_S4BEG[3]
  PIN Tile_X0Y1_S4BEG[4]
    DIRECTION OUTPUT ;
    USE SIGNAL ;
    ANTENNADIFFAREA 0.708600 ;
    PORT
      LAYER Metal2 ;
        RECT 104.920 0.000 105.320 0.400 ;
    END
  END Tile_X0Y1_S4BEG[4]
  PIN Tile_X0Y1_S4BEG[5]
    DIRECTION OUTPUT ;
    USE SIGNAL ;
    ANTENNADIFFAREA 0.708600 ;
    PORT
      LAYER Metal2 ;
        RECT 105.880 0.000 106.280 0.400 ;
    END
  END Tile_X0Y1_S4BEG[5]
  PIN Tile_X0Y1_S4BEG[6]
    DIRECTION OUTPUT ;
    USE SIGNAL ;
    ANTENNADIFFAREA 0.708600 ;
    PORT
      LAYER Metal2 ;
        RECT 106.840 0.000 107.240 0.400 ;
    END
  END Tile_X0Y1_S4BEG[6]
  PIN Tile_X0Y1_S4BEG[7]
    DIRECTION OUTPUT ;
    USE SIGNAL ;
    ANTENNADIFFAREA 0.708600 ;
    PORT
      LAYER Metal2 ;
        RECT 107.800 0.000 108.200 0.400 ;
    END
  END Tile_X0Y1_S4BEG[7]
  PIN Tile_X0Y1_S4BEG[8]
    DIRECTION OUTPUT ;
    USE SIGNAL ;
    ANTENNADIFFAREA 0.708600 ;
    PORT
      LAYER Metal2 ;
        RECT 108.760 0.000 109.160 0.400 ;
    END
  END Tile_X0Y1_S4BEG[8]
  PIN Tile_X0Y1_S4BEG[9]
    DIRECTION OUTPUT ;
    USE SIGNAL ;
    ANTENNADIFFAREA 0.708600 ;
    PORT
      LAYER Metal2 ;
        RECT 109.720 0.000 110.120 0.400 ;
    END
  END Tile_X0Y1_S4BEG[9]
  PIN Tile_X0Y1_SS4BEG[0]
    DIRECTION OUTPUT ;
    USE SIGNAL ;
    ANTENNADIFFAREA 0.708600 ;
    PORT
      LAYER Metal2 ;
        RECT 116.440 0.000 116.840 0.400 ;
    END
  END Tile_X0Y1_SS4BEG[0]
  PIN Tile_X0Y1_SS4BEG[10]
    DIRECTION OUTPUT ;
    USE SIGNAL ;
    ANTENNADIFFAREA 0.708600 ;
    PORT
      LAYER Metal2 ;
        RECT 126.040 0.000 126.440 0.400 ;
    END
  END Tile_X0Y1_SS4BEG[10]
  PIN Tile_X0Y1_SS4BEG[11]
    DIRECTION OUTPUT ;
    USE SIGNAL ;
    ANTENNADIFFAREA 0.708600 ;
    PORT
      LAYER Metal2 ;
        RECT 127.000 0.000 127.400 0.400 ;
    END
  END Tile_X0Y1_SS4BEG[11]
  PIN Tile_X0Y1_SS4BEG[12]
    DIRECTION OUTPUT ;
    USE SIGNAL ;
    ANTENNADIFFAREA 0.708600 ;
    PORT
      LAYER Metal2 ;
        RECT 127.960 0.000 128.360 0.400 ;
    END
  END Tile_X0Y1_SS4BEG[12]
  PIN Tile_X0Y1_SS4BEG[13]
    DIRECTION OUTPUT ;
    USE SIGNAL ;
    ANTENNADIFFAREA 0.708600 ;
    PORT
      LAYER Metal2 ;
        RECT 128.920 0.000 129.320 0.400 ;
    END
  END Tile_X0Y1_SS4BEG[13]
  PIN Tile_X0Y1_SS4BEG[14]
    DIRECTION OUTPUT ;
    USE SIGNAL ;
    ANTENNADIFFAREA 0.708600 ;
    PORT
      LAYER Metal2 ;
        RECT 129.880 0.000 130.280 0.400 ;
    END
  END Tile_X0Y1_SS4BEG[14]
  PIN Tile_X0Y1_SS4BEG[15]
    DIRECTION OUTPUT ;
    USE SIGNAL ;
    ANTENNADIFFAREA 0.708600 ;
    PORT
      LAYER Metal2 ;
        RECT 130.840 0.000 131.240 0.400 ;
    END
  END Tile_X0Y1_SS4BEG[15]
  PIN Tile_X0Y1_SS4BEG[1]
    DIRECTION OUTPUT ;
    USE SIGNAL ;
    ANTENNADIFFAREA 0.708600 ;
    PORT
      LAYER Metal2 ;
        RECT 117.400 0.000 117.800 0.400 ;
    END
  END Tile_X0Y1_SS4BEG[1]
  PIN Tile_X0Y1_SS4BEG[2]
    DIRECTION OUTPUT ;
    USE SIGNAL ;
    ANTENNADIFFAREA 0.708600 ;
    PORT
      LAYER Metal2 ;
        RECT 118.360 0.000 118.760 0.400 ;
    END
  END Tile_X0Y1_SS4BEG[2]
  PIN Tile_X0Y1_SS4BEG[3]
    DIRECTION OUTPUT ;
    USE SIGNAL ;
    ANTENNADIFFAREA 0.708600 ;
    PORT
      LAYER Metal2 ;
        RECT 119.320 0.000 119.720 0.400 ;
    END
  END Tile_X0Y1_SS4BEG[3]
  PIN Tile_X0Y1_SS4BEG[4]
    DIRECTION OUTPUT ;
    USE SIGNAL ;
    ANTENNADIFFAREA 0.708600 ;
    PORT
      LAYER Metal2 ;
        RECT 120.280 0.000 120.680 0.400 ;
    END
  END Tile_X0Y1_SS4BEG[4]
  PIN Tile_X0Y1_SS4BEG[5]
    DIRECTION OUTPUT ;
    USE SIGNAL ;
    ANTENNADIFFAREA 0.708600 ;
    PORT
      LAYER Metal2 ;
        RECT 121.240 0.000 121.640 0.400 ;
    END
  END Tile_X0Y1_SS4BEG[5]
  PIN Tile_X0Y1_SS4BEG[6]
    DIRECTION OUTPUT ;
    USE SIGNAL ;
    ANTENNADIFFAREA 0.708600 ;
    PORT
      LAYER Metal2 ;
        RECT 122.200 0.000 122.600 0.400 ;
    END
  END Tile_X0Y1_SS4BEG[6]
  PIN Tile_X0Y1_SS4BEG[7]
    DIRECTION OUTPUT ;
    USE SIGNAL ;
    ANTENNADIFFAREA 0.708600 ;
    PORT
      LAYER Metal2 ;
        RECT 123.160 0.000 123.560 0.400 ;
    END
  END Tile_X0Y1_SS4BEG[7]
  PIN Tile_X0Y1_SS4BEG[8]
    DIRECTION OUTPUT ;
    USE SIGNAL ;
    ANTENNADIFFAREA 0.708600 ;
    PORT
      LAYER Metal2 ;
        RECT 124.120 0.000 124.520 0.400 ;
    END
  END Tile_X0Y1_SS4BEG[8]
  PIN Tile_X0Y1_SS4BEG[9]
    DIRECTION OUTPUT ;
    USE SIGNAL ;
    ANTENNADIFFAREA 0.708600 ;
    PORT
      LAYER Metal2 ;
        RECT 125.080 0.000 125.480 0.400 ;
    END
  END Tile_X0Y1_SS4BEG[9]
  PIN Tile_X0Y1_UserCLK
    DIRECTION INPUT ;
    USE SIGNAL ;
    ANTENNAGATEAREA 1.450800 ;
    PORT
      LAYER Metal2 ;
        RECT 131.800 0.000 132.200 0.400 ;
    END
  END Tile_X0Y1_UserCLK
  PIN Tile_X0Y1_W1BEG[0]
    DIRECTION OUTPUT ;
    USE SIGNAL ;
    ANTENNADIFFAREA 0.708600 ;
    PORT
      LAYER Metal3 ;
        RECT 0.000 0.220 0.400 0.620 ;
    END
  END Tile_X0Y1_W1BEG[0]
  PIN Tile_X0Y1_W1BEG[1]
    DIRECTION OUTPUT ;
    USE SIGNAL ;
    ANTENNADIFFAREA 0.708600 ;
    PORT
      LAYER Metal3 ;
        RECT 0.000 1.900 0.400 2.300 ;
    END
  END Tile_X0Y1_W1BEG[1]
  PIN Tile_X0Y1_W1BEG[2]
    DIRECTION OUTPUT ;
    USE SIGNAL ;
    ANTENNADIFFAREA 0.708600 ;
    PORT
      LAYER Metal3 ;
        RECT 0.000 3.580 0.400 3.980 ;
    END
  END Tile_X0Y1_W1BEG[2]
  PIN Tile_X0Y1_W1BEG[3]
    DIRECTION OUTPUT ;
    USE SIGNAL ;
    ANTENNADIFFAREA 0.708600 ;
    PORT
      LAYER Metal3 ;
        RECT 0.000 5.260 0.400 5.660 ;
    END
  END Tile_X0Y1_W1BEG[3]
  PIN Tile_X0Y1_W1END[0]
    DIRECTION INPUT ;
    USE SIGNAL ;
    ANTENNAGATEAREA 1.865800 ;
    PORT
      LAYER Metal3 ;
        RECT 184.400 0.220 184.800 0.620 ;
    END
  END Tile_X0Y1_W1END[0]
  PIN Tile_X0Y1_W1END[1]
    DIRECTION INPUT ;
    USE SIGNAL ;
    ANTENNAGATEAREA 2.173400 ;
    PORT
      LAYER Metal3 ;
        RECT 184.400 1.900 184.800 2.300 ;
    END
  END Tile_X0Y1_W1END[1]
  PIN Tile_X0Y1_W1END[2]
    DIRECTION INPUT ;
    USE SIGNAL ;
    ANTENNAGATEAREA 2.431000 ;
    PORT
      LAYER Metal3 ;
        RECT 184.400 3.580 184.800 3.980 ;
    END
  END Tile_X0Y1_W1END[2]
  PIN Tile_X0Y1_W1END[3]
    DIRECTION INPUT ;
    USE SIGNAL ;
    ANTENNAGATEAREA 1.521000 ;
    PORT
      LAYER Metal3 ;
        RECT 184.400 5.260 184.800 5.660 ;
    END
  END Tile_X0Y1_W1END[3]
  PIN Tile_X0Y1_W2BEG[0]
    DIRECTION OUTPUT ;
    USE SIGNAL ;
    ANTENNADIFFAREA 0.708600 ;
    PORT
      LAYER Metal3 ;
        RECT 0.000 6.940 0.400 7.340 ;
    END
  END Tile_X0Y1_W2BEG[0]
  PIN Tile_X0Y1_W2BEG[1]
    DIRECTION OUTPUT ;
    USE SIGNAL ;
    ANTENNADIFFAREA 0.708600 ;
    PORT
      LAYER Metal3 ;
        RECT 0.000 8.620 0.400 9.020 ;
    END
  END Tile_X0Y1_W2BEG[1]
  PIN Tile_X0Y1_W2BEG[2]
    DIRECTION OUTPUT ;
    USE SIGNAL ;
    ANTENNADIFFAREA 0.708600 ;
    PORT
      LAYER Metal3 ;
        RECT 0.000 10.300 0.400 10.700 ;
    END
  END Tile_X0Y1_W2BEG[2]
  PIN Tile_X0Y1_W2BEG[3]
    DIRECTION OUTPUT ;
    USE SIGNAL ;
    ANTENNADIFFAREA 0.708600 ;
    PORT
      LAYER Metal3 ;
        RECT 0.000 11.980 0.400 12.380 ;
    END
  END Tile_X0Y1_W2BEG[3]
  PIN Tile_X0Y1_W2BEG[4]
    DIRECTION OUTPUT ;
    USE SIGNAL ;
    ANTENNADIFFAREA 0.708600 ;
    PORT
      LAYER Metal3 ;
        RECT 0.000 13.660 0.400 14.060 ;
    END
  END Tile_X0Y1_W2BEG[4]
  PIN Tile_X0Y1_W2BEG[5]
    DIRECTION OUTPUT ;
    USE SIGNAL ;
    ANTENNADIFFAREA 0.708600 ;
    PORT
      LAYER Metal3 ;
        RECT 0.000 15.340 0.400 15.740 ;
    END
  END Tile_X0Y1_W2BEG[5]
  PIN Tile_X0Y1_W2BEG[6]
    DIRECTION OUTPUT ;
    USE SIGNAL ;
    ANTENNADIFFAREA 0.708600 ;
    PORT
      LAYER Metal3 ;
        RECT 0.000 17.020 0.400 17.420 ;
    END
  END Tile_X0Y1_W2BEG[6]
  PIN Tile_X0Y1_W2BEG[7]
    DIRECTION OUTPUT ;
    USE SIGNAL ;
    ANTENNADIFFAREA 0.708600 ;
    PORT
      LAYER Metal3 ;
        RECT 0.000 18.700 0.400 19.100 ;
    END
  END Tile_X0Y1_W2BEG[7]
  PIN Tile_X0Y1_W2BEGb[0]
    DIRECTION OUTPUT ;
    USE SIGNAL ;
    ANTENNADIFFAREA 0.708600 ;
    PORT
      LAYER Metal3 ;
        RECT 0.000 20.380 0.400 20.780 ;
    END
  END Tile_X0Y1_W2BEGb[0]
  PIN Tile_X0Y1_W2BEGb[1]
    DIRECTION OUTPUT ;
    USE SIGNAL ;
    ANTENNADIFFAREA 0.708600 ;
    PORT
      LAYER Metal3 ;
        RECT 0.000 22.060 0.400 22.460 ;
    END
  END Tile_X0Y1_W2BEGb[1]
  PIN Tile_X0Y1_W2BEGb[2]
    DIRECTION OUTPUT ;
    USE SIGNAL ;
    ANTENNADIFFAREA 0.708600 ;
    PORT
      LAYER Metal3 ;
        RECT 0.000 23.740 0.400 24.140 ;
    END
  END Tile_X0Y1_W2BEGb[2]
  PIN Tile_X0Y1_W2BEGb[3]
    DIRECTION OUTPUT ;
    USE SIGNAL ;
    ANTENNADIFFAREA 0.708600 ;
    PORT
      LAYER Metal3 ;
        RECT 0.000 25.420 0.400 25.820 ;
    END
  END Tile_X0Y1_W2BEGb[3]
  PIN Tile_X0Y1_W2BEGb[4]
    DIRECTION OUTPUT ;
    USE SIGNAL ;
    ANTENNADIFFAREA 0.708600 ;
    PORT
      LAYER Metal3 ;
        RECT 0.000 27.100 0.400 27.500 ;
    END
  END Tile_X0Y1_W2BEGb[4]
  PIN Tile_X0Y1_W2BEGb[5]
    DIRECTION OUTPUT ;
    USE SIGNAL ;
    ANTENNADIFFAREA 0.708600 ;
    PORT
      LAYER Metal3 ;
        RECT 0.000 28.780 0.400 29.180 ;
    END
  END Tile_X0Y1_W2BEGb[5]
  PIN Tile_X0Y1_W2BEGb[6]
    DIRECTION OUTPUT ;
    USE SIGNAL ;
    ANTENNADIFFAREA 0.708600 ;
    PORT
      LAYER Metal3 ;
        RECT 0.000 30.460 0.400 30.860 ;
    END
  END Tile_X0Y1_W2BEGb[6]
  PIN Tile_X0Y1_W2BEGb[7]
    DIRECTION OUTPUT ;
    USE SIGNAL ;
    ANTENNADIFFAREA 0.708600 ;
    PORT
      LAYER Metal3 ;
        RECT 0.000 32.140 0.400 32.540 ;
    END
  END Tile_X0Y1_W2BEGb[7]
  PIN Tile_X0Y1_W2END[0]
    DIRECTION INPUT ;
    USE SIGNAL ;
    ANTENNAGATEAREA 0.607100 ;
    PORT
      LAYER Metal3 ;
        RECT 184.400 20.380 184.800 20.780 ;
    END
  END Tile_X0Y1_W2END[0]
  PIN Tile_X0Y1_W2END[1]
    DIRECTION INPUT ;
    USE SIGNAL ;
    ANTENNAGATEAREA 1.489600 ;
    PORT
      LAYER Metal3 ;
        RECT 184.400 22.060 184.800 22.460 ;
    END
  END Tile_X0Y1_W2END[1]
  PIN Tile_X0Y1_W2END[2]
    DIRECTION INPUT ;
    USE SIGNAL ;
    ANTENNAGATEAREA 1.325500 ;
    PORT
      LAYER Metal3 ;
        RECT 184.400 23.740 184.800 24.140 ;
    END
  END Tile_X0Y1_W2END[2]
  PIN Tile_X0Y1_W2END[3]
    DIRECTION INPUT ;
    USE SIGNAL ;
    ANTENNAGATEAREA 1.551700 ;
    PORT
      LAYER Metal3 ;
        RECT 184.400 25.420 184.800 25.820 ;
    END
  END Tile_X0Y1_W2END[3]
  PIN Tile_X0Y1_W2END[4]
    DIRECTION INPUT ;
    USE SIGNAL ;
    ANTENNAGATEAREA 1.817700 ;
    PORT
      LAYER Metal3 ;
        RECT 184.400 27.100 184.800 27.500 ;
    END
  END Tile_X0Y1_W2END[4]
  PIN Tile_X0Y1_W2END[5]
    DIRECTION INPUT ;
    USE SIGNAL ;
    ANTENNAGATEAREA 0.426400 ;
    PORT
      LAYER Metal3 ;
        RECT 184.400 28.780 184.800 29.180 ;
    END
  END Tile_X0Y1_W2END[5]
  PIN Tile_X0Y1_W2END[6]
    DIRECTION INPUT ;
    USE SIGNAL ;
    ANTENNAGATEAREA 0.426400 ;
    PORT
      LAYER Metal3 ;
        RECT 184.400 30.460 184.800 30.860 ;
    END
  END Tile_X0Y1_W2END[6]
  PIN Tile_X0Y1_W2END[7]
    DIRECTION INPUT ;
    USE SIGNAL ;
    ANTENNAGATEAREA 0.886100 ;
    PORT
      LAYER Metal3 ;
        RECT 184.400 32.140 184.800 32.540 ;
    END
  END Tile_X0Y1_W2END[7]
  PIN Tile_X0Y1_W2MID[0]
    DIRECTION INPUT ;
    USE SIGNAL ;
    ANTENNAGATEAREA 1.230900 ;
    PORT
      LAYER Metal3 ;
        RECT 184.400 6.940 184.800 7.340 ;
    END
  END Tile_X0Y1_W2MID[0]
  PIN Tile_X0Y1_W2MID[1]
    DIRECTION INPUT ;
    USE SIGNAL ;
    ANTENNAGATEAREA 1.156500 ;
    PORT
      LAYER Metal3 ;
        RECT 184.400 8.620 184.800 9.020 ;
    END
  END Tile_X0Y1_W2MID[1]
  PIN Tile_X0Y1_W2MID[2]
    DIRECTION INPUT ;
    USE SIGNAL ;
    ANTENNAGATEAREA 4.504000 ;
    ANTENNADIFFAREA 12.092400 ;
    PORT
      LAYER Metal3 ;
        RECT 184.400 10.300 184.800 10.700 ;
    END
  END Tile_X0Y1_W2MID[2]
  PIN Tile_X0Y1_W2MID[3]
    DIRECTION INPUT ;
    USE SIGNAL ;
    ANTENNAGATEAREA 0.848900 ;
    PORT
      LAYER Metal3 ;
        RECT 184.400 11.980 184.800 12.380 ;
    END
  END Tile_X0Y1_W2MID[3]
  PIN Tile_X0Y1_W2MID[4]
    DIRECTION INPUT ;
    USE SIGNAL ;
    ANTENNAGATEAREA 0.422500 ;
    PORT
      LAYER Metal3 ;
        RECT 184.400 13.660 184.800 14.060 ;
    END
  END Tile_X0Y1_W2MID[4]
  PIN Tile_X0Y1_W2MID[5]
    DIRECTION INPUT ;
    USE SIGNAL ;
    ANTENNAGATEAREA 1.033500 ;
    PORT
      LAYER Metal3 ;
        RECT 184.400 15.340 184.800 15.740 ;
    END
  END Tile_X0Y1_W2MID[5]
  PIN Tile_X0Y1_W2MID[6]
    DIRECTION INPUT ;
    USE SIGNAL ;
    ANTENNAGATEAREA 0.951900 ;
    PORT
      LAYER Metal3 ;
        RECT 184.400 17.020 184.800 17.420 ;
    END
  END Tile_X0Y1_W2MID[6]
  PIN Tile_X0Y1_W2MID[7]
    DIRECTION INPUT ;
    USE SIGNAL ;
    ANTENNAGATEAREA 1.119300 ;
    PORT
      LAYER Metal3 ;
        RECT 184.400 18.700 184.800 19.100 ;
    END
  END Tile_X0Y1_W2MID[7]
  PIN Tile_X0Y1_W6BEG[0]
    DIRECTION OUTPUT ;
    USE SIGNAL ;
    ANTENNADIFFAREA 0.708600 ;
    PORT
      LAYER Metal3 ;
        RECT 0.000 60.700 0.400 61.100 ;
    END
  END Tile_X0Y1_W6BEG[0]
  PIN Tile_X0Y1_W6BEG[10]
    DIRECTION OUTPUT ;
    USE SIGNAL ;
    ANTENNADIFFAREA 0.708600 ;
    PORT
      LAYER Metal3 ;
        RECT 0.000 77.500 0.400 77.900 ;
    END
  END Tile_X0Y1_W6BEG[10]
  PIN Tile_X0Y1_W6BEG[11]
    DIRECTION OUTPUT ;
    USE SIGNAL ;
    ANTENNADIFFAREA 0.708600 ;
    PORT
      LAYER Metal3 ;
        RECT 0.000 79.180 0.400 79.580 ;
    END
  END Tile_X0Y1_W6BEG[11]
  PIN Tile_X0Y1_W6BEG[1]
    DIRECTION OUTPUT ;
    USE SIGNAL ;
    ANTENNADIFFAREA 0.708600 ;
    PORT
      LAYER Metal3 ;
        RECT 0.000 62.380 0.400 62.780 ;
    END
  END Tile_X0Y1_W6BEG[1]
  PIN Tile_X0Y1_W6BEG[2]
    DIRECTION OUTPUT ;
    USE SIGNAL ;
    ANTENNADIFFAREA 0.708600 ;
    PORT
      LAYER Metal3 ;
        RECT 0.000 64.060 0.400 64.460 ;
    END
  END Tile_X0Y1_W6BEG[2]
  PIN Tile_X0Y1_W6BEG[3]
    DIRECTION OUTPUT ;
    USE SIGNAL ;
    ANTENNADIFFAREA 0.708600 ;
    PORT
      LAYER Metal3 ;
        RECT 0.000 65.740 0.400 66.140 ;
    END
  END Tile_X0Y1_W6BEG[3]
  PIN Tile_X0Y1_W6BEG[4]
    DIRECTION OUTPUT ;
    USE SIGNAL ;
    ANTENNADIFFAREA 0.708600 ;
    PORT
      LAYER Metal3 ;
        RECT 0.000 67.420 0.400 67.820 ;
    END
  END Tile_X0Y1_W6BEG[4]
  PIN Tile_X0Y1_W6BEG[5]
    DIRECTION OUTPUT ;
    USE SIGNAL ;
    ANTENNADIFFAREA 0.708600 ;
    PORT
      LAYER Metal3 ;
        RECT 0.000 69.100 0.400 69.500 ;
    END
  END Tile_X0Y1_W6BEG[5]
  PIN Tile_X0Y1_W6BEG[6]
    DIRECTION OUTPUT ;
    USE SIGNAL ;
    ANTENNADIFFAREA 0.708600 ;
    PORT
      LAYER Metal3 ;
        RECT 0.000 70.780 0.400 71.180 ;
    END
  END Tile_X0Y1_W6BEG[6]
  PIN Tile_X0Y1_W6BEG[7]
    DIRECTION OUTPUT ;
    USE SIGNAL ;
    ANTENNADIFFAREA 0.708600 ;
    PORT
      LAYER Metal3 ;
        RECT 0.000 72.460 0.400 72.860 ;
    END
  END Tile_X0Y1_W6BEG[7]
  PIN Tile_X0Y1_W6BEG[8]
    DIRECTION OUTPUT ;
    USE SIGNAL ;
    ANTENNADIFFAREA 0.708600 ;
    PORT
      LAYER Metal3 ;
        RECT 0.000 74.140 0.400 74.540 ;
    END
  END Tile_X0Y1_W6BEG[8]
  PIN Tile_X0Y1_W6BEG[9]
    DIRECTION OUTPUT ;
    USE SIGNAL ;
    ANTENNADIFFAREA 0.708600 ;
    PORT
      LAYER Metal3 ;
        RECT 0.000 75.820 0.400 76.220 ;
    END
  END Tile_X0Y1_W6BEG[9]
  PIN Tile_X0Y1_W6END[0]
    DIRECTION INPUT ;
    USE SIGNAL ;
    ANTENNAGATEAREA 1.974200 ;
    PORT
      LAYER Metal3 ;
        RECT 184.400 60.700 184.800 61.100 ;
    END
  END Tile_X0Y1_W6END[0]
  PIN Tile_X0Y1_W6END[10]
    DIRECTION INPUT ;
    USE SIGNAL ;
    ANTENNAGATEAREA 0.180700 ;
    PORT
      LAYER Metal3 ;
        RECT 184.400 77.500 184.800 77.900 ;
    END
  END Tile_X0Y1_W6END[10]
  PIN Tile_X0Y1_W6END[11]
    DIRECTION INPUT ;
    USE SIGNAL ;
    ANTENNAGATEAREA 0.180700 ;
    PORT
      LAYER Metal3 ;
        RECT 184.400 79.180 184.800 79.580 ;
    END
  END Tile_X0Y1_W6END[11]
  PIN Tile_X0Y1_W6END[1]
    DIRECTION INPUT ;
    USE SIGNAL ;
    ANTENNAGATEAREA 1.547000 ;
    PORT
      LAYER Metal3 ;
        RECT 184.400 62.380 184.800 62.780 ;
    END
  END Tile_X0Y1_W6END[1]
  PIN Tile_X0Y1_W6END[2]
    DIRECTION INPUT ;
    USE SIGNAL ;
    ANTENNAGATEAREA 0.180700 ;
    PORT
      LAYER Metal3 ;
        RECT 184.400 64.060 184.800 64.460 ;
    END
  END Tile_X0Y1_W6END[2]
  PIN Tile_X0Y1_W6END[3]
    DIRECTION INPUT ;
    USE SIGNAL ;
    ANTENNAGATEAREA 0.180700 ;
    PORT
      LAYER Metal3 ;
        RECT 184.400 65.740 184.800 66.140 ;
    END
  END Tile_X0Y1_W6END[3]
  PIN Tile_X0Y1_W6END[4]
    DIRECTION INPUT ;
    USE SIGNAL ;
    ANTENNAGATEAREA 0.180700 ;
    PORT
      LAYER Metal3 ;
        RECT 184.400 67.420 184.800 67.820 ;
    END
  END Tile_X0Y1_W6END[4]
  PIN Tile_X0Y1_W6END[5]
    DIRECTION INPUT ;
    USE SIGNAL ;
    ANTENNAGATEAREA 0.180700 ;
    PORT
      LAYER Metal3 ;
        RECT 184.400 69.100 184.800 69.500 ;
    END
  END Tile_X0Y1_W6END[5]
  PIN Tile_X0Y1_W6END[6]
    DIRECTION INPUT ;
    USE SIGNAL ;
    ANTENNAGATEAREA 0.180700 ;
    PORT
      LAYER Metal3 ;
        RECT 184.400 70.780 184.800 71.180 ;
    END
  END Tile_X0Y1_W6END[6]
  PIN Tile_X0Y1_W6END[7]
    DIRECTION INPUT ;
    USE SIGNAL ;
    ANTENNAGATEAREA 0.180700 ;
    PORT
      LAYER Metal3 ;
        RECT 184.400 72.460 184.800 72.860 ;
    END
  END Tile_X0Y1_W6END[7]
  PIN Tile_X0Y1_W6END[8]
    DIRECTION INPUT ;
    USE SIGNAL ;
    ANTENNAGATEAREA 0.180700 ;
    PORT
      LAYER Metal3 ;
        RECT 184.400 74.140 184.800 74.540 ;
    END
  END Tile_X0Y1_W6END[8]
  PIN Tile_X0Y1_W6END[9]
    DIRECTION INPUT ;
    USE SIGNAL ;
    ANTENNAGATEAREA 0.180700 ;
    PORT
      LAYER Metal3 ;
        RECT 184.400 75.820 184.800 76.220 ;
    END
  END Tile_X0Y1_W6END[9]
  PIN Tile_X0Y1_WW4BEG[0]
    DIRECTION OUTPUT ;
    USE SIGNAL ;
    ANTENNADIFFAREA 0.708600 ;
    PORT
      LAYER Metal3 ;
        RECT 0.000 33.820 0.400 34.220 ;
    END
  END Tile_X0Y1_WW4BEG[0]
  PIN Tile_X0Y1_WW4BEG[10]
    DIRECTION OUTPUT ;
    USE SIGNAL ;
    ANTENNADIFFAREA 0.708600 ;
    PORT
      LAYER Metal3 ;
        RECT 0.000 50.620 0.400 51.020 ;
    END
  END Tile_X0Y1_WW4BEG[10]
  PIN Tile_X0Y1_WW4BEG[11]
    DIRECTION OUTPUT ;
    USE SIGNAL ;
    ANTENNADIFFAREA 0.708600 ;
    PORT
      LAYER Metal3 ;
        RECT 0.000 52.300 0.400 52.700 ;
    END
  END Tile_X0Y1_WW4BEG[11]
  PIN Tile_X0Y1_WW4BEG[12]
    DIRECTION OUTPUT ;
    USE SIGNAL ;
    ANTENNADIFFAREA 0.708600 ;
    PORT
      LAYER Metal3 ;
        RECT 0.000 53.980 0.400 54.380 ;
    END
  END Tile_X0Y1_WW4BEG[12]
  PIN Tile_X0Y1_WW4BEG[13]
    DIRECTION OUTPUT ;
    USE SIGNAL ;
    ANTENNADIFFAREA 0.708600 ;
    PORT
      LAYER Metal3 ;
        RECT 0.000 55.660 0.400 56.060 ;
    END
  END Tile_X0Y1_WW4BEG[13]
  PIN Tile_X0Y1_WW4BEG[14]
    DIRECTION OUTPUT ;
    USE SIGNAL ;
    ANTENNADIFFAREA 0.708600 ;
    PORT
      LAYER Metal3 ;
        RECT 0.000 57.340 0.400 57.740 ;
    END
  END Tile_X0Y1_WW4BEG[14]
  PIN Tile_X0Y1_WW4BEG[15]
    DIRECTION OUTPUT ;
    USE SIGNAL ;
    ANTENNADIFFAREA 0.708600 ;
    PORT
      LAYER Metal3 ;
        RECT 0.000 59.020 0.400 59.420 ;
    END
  END Tile_X0Y1_WW4BEG[15]
  PIN Tile_X0Y1_WW4BEG[1]
    DIRECTION OUTPUT ;
    USE SIGNAL ;
    ANTENNADIFFAREA 0.708600 ;
    PORT
      LAYER Metal3 ;
        RECT 0.000 35.500 0.400 35.900 ;
    END
  END Tile_X0Y1_WW4BEG[1]
  PIN Tile_X0Y1_WW4BEG[2]
    DIRECTION OUTPUT ;
    USE SIGNAL ;
    ANTENNADIFFAREA 0.708600 ;
    PORT
      LAYER Metal3 ;
        RECT 0.000 37.180 0.400 37.580 ;
    END
  END Tile_X0Y1_WW4BEG[2]
  PIN Tile_X0Y1_WW4BEG[3]
    DIRECTION OUTPUT ;
    USE SIGNAL ;
    ANTENNADIFFAREA 0.708600 ;
    PORT
      LAYER Metal3 ;
        RECT 0.000 38.860 0.400 39.260 ;
    END
  END Tile_X0Y1_WW4BEG[3]
  PIN Tile_X0Y1_WW4BEG[4]
    DIRECTION OUTPUT ;
    USE SIGNAL ;
    ANTENNADIFFAREA 0.708600 ;
    PORT
      LAYER Metal3 ;
        RECT 0.000 40.540 0.400 40.940 ;
    END
  END Tile_X0Y1_WW4BEG[4]
  PIN Tile_X0Y1_WW4BEG[5]
    DIRECTION OUTPUT ;
    USE SIGNAL ;
    ANTENNADIFFAREA 0.708600 ;
    PORT
      LAYER Metal3 ;
        RECT 0.000 42.220 0.400 42.620 ;
    END
  END Tile_X0Y1_WW4BEG[5]
  PIN Tile_X0Y1_WW4BEG[6]
    DIRECTION OUTPUT ;
    USE SIGNAL ;
    ANTENNADIFFAREA 0.708600 ;
    PORT
      LAYER Metal3 ;
        RECT 0.000 43.900 0.400 44.300 ;
    END
  END Tile_X0Y1_WW4BEG[6]
  PIN Tile_X0Y1_WW4BEG[7]
    DIRECTION OUTPUT ;
    USE SIGNAL ;
    ANTENNADIFFAREA 0.708600 ;
    PORT
      LAYER Metal3 ;
        RECT 0.000 45.580 0.400 45.980 ;
    END
  END Tile_X0Y1_WW4BEG[7]
  PIN Tile_X0Y1_WW4BEG[8]
    DIRECTION OUTPUT ;
    USE SIGNAL ;
    ANTENNADIFFAREA 0.708600 ;
    PORT
      LAYER Metal3 ;
        RECT 0.000 47.260 0.400 47.660 ;
    END
  END Tile_X0Y1_WW4BEG[8]
  PIN Tile_X0Y1_WW4BEG[9]
    DIRECTION OUTPUT ;
    USE SIGNAL ;
    ANTENNADIFFAREA 0.708600 ;
    PORT
      LAYER Metal3 ;
        RECT 0.000 48.940 0.400 49.340 ;
    END
  END Tile_X0Y1_WW4BEG[9]
  PIN Tile_X0Y1_WW4END[0]
    DIRECTION INPUT ;
    USE SIGNAL ;
    ANTENNAGATEAREA 0.668200 ;
    PORT
      LAYER Metal3 ;
        RECT 184.400 33.820 184.800 34.220 ;
    END
  END Tile_X0Y1_WW4END[0]
  PIN Tile_X0Y1_WW4END[10]
    DIRECTION INPUT ;
    USE SIGNAL ;
    ANTENNAGATEAREA 0.180700 ;
    PORT
      LAYER Metal3 ;
        RECT 184.400 50.620 184.800 51.020 ;
    END
  END Tile_X0Y1_WW4END[10]
  PIN Tile_X0Y1_WW4END[11]
    DIRECTION INPUT ;
    USE SIGNAL ;
    ANTENNAGATEAREA 0.180700 ;
    PORT
      LAYER Metal3 ;
        RECT 184.400 52.300 184.800 52.700 ;
    END
  END Tile_X0Y1_WW4END[11]
  PIN Tile_X0Y1_WW4END[12]
    DIRECTION INPUT ;
    USE SIGNAL ;
    ANTENNAGATEAREA 0.180700 ;
    PORT
      LAYER Metal3 ;
        RECT 184.400 53.980 184.800 54.380 ;
    END
  END Tile_X0Y1_WW4END[12]
  PIN Tile_X0Y1_WW4END[13]
    DIRECTION INPUT ;
    USE SIGNAL ;
    ANTENNAGATEAREA 0.180700 ;
    PORT
      LAYER Metal3 ;
        RECT 184.400 55.660 184.800 56.060 ;
    END
  END Tile_X0Y1_WW4END[13]
  PIN Tile_X0Y1_WW4END[14]
    DIRECTION INPUT ;
    USE SIGNAL ;
    ANTENNAGATEAREA 0.180700 ;
    PORT
      LAYER Metal3 ;
        RECT 184.400 57.340 184.800 57.740 ;
    END
  END Tile_X0Y1_WW4END[14]
  PIN Tile_X0Y1_WW4END[15]
    DIRECTION INPUT ;
    USE SIGNAL ;
    ANTENNAGATEAREA 0.180700 ;
    PORT
      LAYER Metal3 ;
        RECT 184.400 59.020 184.800 59.420 ;
    END
  END Tile_X0Y1_WW4END[15]
  PIN Tile_X0Y1_WW4END[1]
    DIRECTION INPUT ;
    USE SIGNAL ;
    ANTENNAGATEAREA 0.705400 ;
    PORT
      LAYER Metal3 ;
        RECT 184.400 35.500 184.800 35.900 ;
    END
  END Tile_X0Y1_WW4END[1]
  PIN Tile_X0Y1_WW4END[2]
    DIRECTION INPUT ;
    USE SIGNAL ;
    ANTENNAGATEAREA 0.705400 ;
    PORT
      LAYER Metal3 ;
        RECT 184.400 37.180 184.800 37.580 ;
    END
  END Tile_X0Y1_WW4END[2]
  PIN Tile_X0Y1_WW4END[3]
    DIRECTION INPUT ;
    USE SIGNAL ;
    ANTENNAGATEAREA 0.639600 ;
    PORT
      LAYER Metal3 ;
        RECT 184.400 38.860 184.800 39.260 ;
    END
  END Tile_X0Y1_WW4END[3]
  PIN Tile_X0Y1_WW4END[4]
    DIRECTION INPUT ;
    USE SIGNAL ;
    ANTENNAGATEAREA 0.180700 ;
    PORT
      LAYER Metal3 ;
        RECT 184.400 40.540 184.800 40.940 ;
    END
  END Tile_X0Y1_WW4END[4]
  PIN Tile_X0Y1_WW4END[5]
    DIRECTION INPUT ;
    USE SIGNAL ;
    ANTENNAGATEAREA 0.180700 ;
    PORT
      LAYER Metal3 ;
        RECT 184.400 42.220 184.800 42.620 ;
    END
  END Tile_X0Y1_WW4END[5]
  PIN Tile_X0Y1_WW4END[6]
    DIRECTION INPUT ;
    USE SIGNAL ;
    ANTENNAGATEAREA 0.180700 ;
    PORT
      LAYER Metal3 ;
        RECT 184.400 43.900 184.800 44.300 ;
    END
  END Tile_X0Y1_WW4END[6]
  PIN Tile_X0Y1_WW4END[7]
    DIRECTION INPUT ;
    USE SIGNAL ;
    ANTENNAGATEAREA 0.180700 ;
    PORT
      LAYER Metal3 ;
        RECT 184.400 45.580 184.800 45.980 ;
    END
  END Tile_X0Y1_WW4END[7]
  PIN Tile_X0Y1_WW4END[8]
    DIRECTION INPUT ;
    USE SIGNAL ;
    ANTENNAGATEAREA 0.180700 ;
    PORT
      LAYER Metal3 ;
        RECT 184.400 47.260 184.800 47.660 ;
    END
  END Tile_X0Y1_WW4END[8]
  PIN Tile_X0Y1_WW4END[9]
    DIRECTION INPUT ;
    USE SIGNAL ;
    ANTENNAGATEAREA 0.180700 ;
    PORT
      LAYER Metal3 ;
        RECT 184.400 48.940 184.800 49.340 ;
    END
  END Tile_X0Y1_WW4END[9]
  PIN VGND
    DIRECTION INOUT ;
    USE GROUND ;
    PORT
      LAYER TopMetal1 ;
        RECT 21.580 0.000 23.780 430.920 ;
    END
    PORT
      LAYER TopMetal1 ;
        RECT 97.180 0.000 99.380 430.920 ;
    END
    PORT
      LAYER TopMetal1 ;
        RECT 172.780 0.000 174.980 430.920 ;
    END
  END VGND
  PIN VPWR
    DIRECTION INOUT ;
    USE POWER ;
    PORT
      LAYER TopMetal1 ;
        RECT 15.380 0.000 17.580 430.920 ;
    END
    PORT
      LAYER TopMetal1 ;
        RECT 90.980 0.000 93.180 430.920 ;
    END
    PORT
      LAYER TopMetal1 ;
        RECT 166.580 0.000 168.780 430.920 ;
    END
  END VPWR
  OBS
      LAYER GatPoly ;
        RECT 2.880 3.630 181.920 427.290 ;
      LAYER Metal1 ;
        RECT 2.880 3.560 181.920 427.360 ;
      LAYER Metal2 ;
        RECT 0.375 430.310 31.750 430.520 ;
        RECT 32.570 430.310 32.710 430.520 ;
        RECT 33.530 430.310 33.670 430.520 ;
        RECT 34.490 430.310 34.630 430.520 ;
        RECT 35.450 430.310 35.590 430.520 ;
        RECT 36.410 430.310 36.550 430.520 ;
        RECT 37.370 430.310 37.510 430.520 ;
        RECT 38.330 430.310 38.470 430.520 ;
        RECT 39.290 430.310 39.430 430.520 ;
        RECT 40.250 430.310 40.390 430.520 ;
        RECT 41.210 430.310 41.350 430.520 ;
        RECT 42.170 430.310 42.310 430.520 ;
        RECT 43.130 430.310 43.270 430.520 ;
        RECT 44.090 430.310 44.230 430.520 ;
        RECT 45.050 430.310 45.190 430.520 ;
        RECT 46.010 430.310 46.150 430.520 ;
        RECT 46.970 430.310 47.110 430.520 ;
        RECT 47.930 430.310 48.070 430.520 ;
        RECT 48.890 430.310 49.030 430.520 ;
        RECT 49.850 430.310 49.990 430.520 ;
        RECT 50.810 430.310 50.950 430.520 ;
        RECT 51.770 430.310 51.910 430.520 ;
        RECT 52.730 430.310 52.870 430.520 ;
        RECT 53.690 430.310 53.830 430.520 ;
        RECT 54.650 430.310 54.790 430.520 ;
        RECT 55.610 430.310 55.750 430.520 ;
        RECT 56.570 430.310 56.710 430.520 ;
        RECT 57.530 430.310 57.670 430.520 ;
        RECT 58.490 430.310 58.630 430.520 ;
        RECT 59.450 430.310 59.590 430.520 ;
        RECT 60.410 430.310 60.550 430.520 ;
        RECT 61.370 430.310 61.510 430.520 ;
        RECT 62.330 430.310 62.470 430.520 ;
        RECT 63.290 430.310 63.430 430.520 ;
        RECT 64.250 430.310 64.390 430.520 ;
        RECT 65.210 430.310 65.350 430.520 ;
        RECT 66.170 430.310 66.310 430.520 ;
        RECT 67.130 430.310 67.270 430.520 ;
        RECT 68.090 430.310 68.230 430.520 ;
        RECT 69.050 430.310 69.190 430.520 ;
        RECT 70.010 430.310 70.150 430.520 ;
        RECT 70.970 430.310 71.110 430.520 ;
        RECT 71.930 430.310 72.070 430.520 ;
        RECT 72.890 430.310 73.030 430.520 ;
        RECT 73.850 430.310 73.990 430.520 ;
        RECT 74.810 430.310 74.950 430.520 ;
        RECT 75.770 430.310 75.910 430.520 ;
        RECT 76.730 430.310 76.870 430.520 ;
        RECT 77.690 430.310 77.830 430.520 ;
        RECT 78.650 430.310 78.790 430.520 ;
        RECT 79.610 430.310 79.750 430.520 ;
        RECT 80.570 430.310 80.710 430.520 ;
        RECT 81.530 430.310 81.670 430.520 ;
        RECT 82.490 430.310 82.630 430.520 ;
        RECT 83.450 430.310 83.590 430.520 ;
        RECT 84.410 430.310 84.550 430.520 ;
        RECT 85.370 430.310 85.510 430.520 ;
        RECT 86.330 430.310 86.470 430.520 ;
        RECT 87.290 430.310 87.430 430.520 ;
        RECT 88.250 430.310 88.390 430.520 ;
        RECT 89.210 430.310 89.350 430.520 ;
        RECT 90.170 430.310 90.310 430.520 ;
        RECT 91.130 430.310 91.270 430.520 ;
        RECT 92.090 430.310 92.230 430.520 ;
        RECT 93.050 430.310 93.190 430.520 ;
        RECT 94.010 430.310 94.150 430.520 ;
        RECT 94.970 430.310 95.110 430.520 ;
        RECT 95.930 430.310 96.070 430.520 ;
        RECT 96.890 430.310 97.030 430.520 ;
        RECT 97.850 430.310 97.990 430.520 ;
        RECT 98.810 430.310 98.950 430.520 ;
        RECT 99.770 430.310 99.910 430.520 ;
        RECT 100.730 430.310 100.870 430.520 ;
        RECT 101.690 430.310 101.830 430.520 ;
        RECT 102.650 430.310 102.790 430.520 ;
        RECT 103.610 430.310 103.750 430.520 ;
        RECT 104.570 430.310 104.710 430.520 ;
        RECT 105.530 430.310 105.670 430.520 ;
        RECT 106.490 430.310 106.630 430.520 ;
        RECT 107.450 430.310 107.590 430.520 ;
        RECT 108.410 430.310 108.550 430.520 ;
        RECT 109.370 430.310 109.510 430.520 ;
        RECT 110.330 430.310 110.470 430.520 ;
        RECT 111.290 430.310 111.430 430.520 ;
        RECT 112.250 430.310 112.390 430.520 ;
        RECT 113.210 430.310 113.350 430.520 ;
        RECT 114.170 430.310 114.310 430.520 ;
        RECT 115.130 430.310 115.270 430.520 ;
        RECT 116.090 430.310 116.230 430.520 ;
        RECT 117.050 430.310 117.190 430.520 ;
        RECT 118.010 430.310 118.150 430.520 ;
        RECT 118.970 430.310 119.110 430.520 ;
        RECT 119.930 430.310 120.070 430.520 ;
        RECT 120.890 430.310 121.030 430.520 ;
        RECT 121.850 430.310 121.990 430.520 ;
        RECT 122.810 430.310 122.950 430.520 ;
        RECT 123.770 430.310 123.910 430.520 ;
        RECT 124.730 430.310 124.870 430.520 ;
        RECT 125.690 430.310 125.830 430.520 ;
        RECT 126.650 430.310 126.790 430.520 ;
        RECT 127.610 430.310 127.750 430.520 ;
        RECT 128.570 430.310 128.710 430.520 ;
        RECT 129.530 430.310 129.670 430.520 ;
        RECT 130.490 430.310 130.630 430.520 ;
        RECT 131.450 430.310 131.590 430.520 ;
        RECT 132.410 430.310 132.550 430.520 ;
        RECT 133.370 430.310 133.510 430.520 ;
        RECT 134.330 430.310 134.470 430.520 ;
        RECT 135.290 430.310 135.430 430.520 ;
        RECT 136.250 430.310 136.390 430.520 ;
        RECT 137.210 430.310 137.350 430.520 ;
        RECT 138.170 430.310 138.310 430.520 ;
        RECT 139.130 430.310 139.270 430.520 ;
        RECT 140.090 430.310 140.230 430.520 ;
        RECT 141.050 430.310 141.190 430.520 ;
        RECT 142.010 430.310 142.150 430.520 ;
        RECT 142.970 430.310 143.110 430.520 ;
        RECT 143.930 430.310 144.070 430.520 ;
        RECT 144.890 430.310 145.030 430.520 ;
        RECT 145.850 430.310 145.990 430.520 ;
        RECT 146.810 430.310 146.950 430.520 ;
        RECT 147.770 430.310 147.910 430.520 ;
        RECT 148.730 430.310 148.870 430.520 ;
        RECT 149.690 430.310 149.830 430.520 ;
        RECT 150.650 430.310 150.790 430.520 ;
        RECT 151.610 430.310 184.425 430.520 ;
        RECT 0.375 0.610 184.425 430.310 ;
        RECT 0.375 0.275 31.750 0.610 ;
        RECT 32.570 0.275 32.710 0.610 ;
        RECT 33.530 0.275 33.670 0.610 ;
        RECT 34.490 0.275 34.630 0.610 ;
        RECT 35.450 0.275 35.590 0.610 ;
        RECT 36.410 0.275 36.550 0.610 ;
        RECT 37.370 0.275 37.510 0.610 ;
        RECT 38.330 0.275 38.470 0.610 ;
        RECT 39.290 0.275 39.430 0.610 ;
        RECT 40.250 0.275 40.390 0.610 ;
        RECT 41.210 0.275 41.350 0.610 ;
        RECT 42.170 0.275 42.310 0.610 ;
        RECT 43.130 0.275 43.270 0.610 ;
        RECT 44.090 0.275 44.230 0.610 ;
        RECT 45.050 0.275 45.190 0.610 ;
        RECT 46.010 0.275 46.150 0.610 ;
        RECT 46.970 0.275 47.110 0.610 ;
        RECT 47.930 0.275 48.070 0.610 ;
        RECT 48.890 0.275 49.030 0.610 ;
        RECT 49.850 0.275 49.990 0.610 ;
        RECT 50.810 0.275 50.950 0.610 ;
        RECT 51.770 0.275 51.910 0.610 ;
        RECT 52.730 0.275 52.870 0.610 ;
        RECT 53.690 0.275 53.830 0.610 ;
        RECT 54.650 0.275 54.790 0.610 ;
        RECT 55.610 0.275 55.750 0.610 ;
        RECT 56.570 0.275 56.710 0.610 ;
        RECT 57.530 0.275 57.670 0.610 ;
        RECT 58.490 0.275 58.630 0.610 ;
        RECT 59.450 0.275 59.590 0.610 ;
        RECT 60.410 0.275 60.550 0.610 ;
        RECT 61.370 0.275 61.510 0.610 ;
        RECT 62.330 0.275 62.470 0.610 ;
        RECT 63.290 0.275 63.430 0.610 ;
        RECT 64.250 0.275 64.390 0.610 ;
        RECT 65.210 0.275 65.350 0.610 ;
        RECT 66.170 0.275 66.310 0.610 ;
        RECT 67.130 0.275 67.270 0.610 ;
        RECT 68.090 0.275 68.230 0.610 ;
        RECT 69.050 0.275 69.190 0.610 ;
        RECT 70.010 0.275 70.150 0.610 ;
        RECT 70.970 0.275 71.110 0.610 ;
        RECT 71.930 0.275 72.070 0.610 ;
        RECT 72.890 0.275 73.030 0.610 ;
        RECT 73.850 0.275 73.990 0.610 ;
        RECT 74.810 0.275 74.950 0.610 ;
        RECT 75.770 0.275 75.910 0.610 ;
        RECT 76.730 0.275 76.870 0.610 ;
        RECT 77.690 0.275 77.830 0.610 ;
        RECT 78.650 0.275 78.790 0.610 ;
        RECT 79.610 0.275 79.750 0.610 ;
        RECT 80.570 0.275 80.710 0.610 ;
        RECT 81.530 0.275 81.670 0.610 ;
        RECT 82.490 0.275 82.630 0.610 ;
        RECT 83.450 0.275 83.590 0.610 ;
        RECT 84.410 0.275 84.550 0.610 ;
        RECT 85.370 0.275 85.510 0.610 ;
        RECT 86.330 0.275 86.470 0.610 ;
        RECT 87.290 0.275 87.430 0.610 ;
        RECT 88.250 0.275 88.390 0.610 ;
        RECT 89.210 0.275 89.350 0.610 ;
        RECT 90.170 0.275 90.310 0.610 ;
        RECT 91.130 0.275 91.270 0.610 ;
        RECT 92.090 0.275 92.230 0.610 ;
        RECT 93.050 0.275 93.190 0.610 ;
        RECT 94.010 0.275 94.150 0.610 ;
        RECT 94.970 0.275 95.110 0.610 ;
        RECT 95.930 0.275 96.070 0.610 ;
        RECT 96.890 0.275 97.030 0.610 ;
        RECT 97.850 0.275 97.990 0.610 ;
        RECT 98.810 0.275 98.950 0.610 ;
        RECT 99.770 0.275 99.910 0.610 ;
        RECT 100.730 0.275 100.870 0.610 ;
        RECT 101.690 0.275 101.830 0.610 ;
        RECT 102.650 0.275 102.790 0.610 ;
        RECT 103.610 0.275 103.750 0.610 ;
        RECT 104.570 0.275 104.710 0.610 ;
        RECT 105.530 0.275 105.670 0.610 ;
        RECT 106.490 0.275 106.630 0.610 ;
        RECT 107.450 0.275 107.590 0.610 ;
        RECT 108.410 0.275 108.550 0.610 ;
        RECT 109.370 0.275 109.510 0.610 ;
        RECT 110.330 0.275 110.470 0.610 ;
        RECT 111.290 0.275 111.430 0.610 ;
        RECT 112.250 0.275 112.390 0.610 ;
        RECT 113.210 0.275 113.350 0.610 ;
        RECT 114.170 0.275 114.310 0.610 ;
        RECT 115.130 0.275 115.270 0.610 ;
        RECT 116.090 0.275 116.230 0.610 ;
        RECT 117.050 0.275 117.190 0.610 ;
        RECT 118.010 0.275 118.150 0.610 ;
        RECT 118.970 0.275 119.110 0.610 ;
        RECT 119.930 0.275 120.070 0.610 ;
        RECT 120.890 0.275 121.030 0.610 ;
        RECT 121.850 0.275 121.990 0.610 ;
        RECT 122.810 0.275 122.950 0.610 ;
        RECT 123.770 0.275 123.910 0.610 ;
        RECT 124.730 0.275 124.870 0.610 ;
        RECT 125.690 0.275 125.830 0.610 ;
        RECT 126.650 0.275 126.790 0.610 ;
        RECT 127.610 0.275 127.750 0.610 ;
        RECT 128.570 0.275 128.710 0.610 ;
        RECT 129.530 0.275 129.670 0.610 ;
        RECT 130.490 0.275 130.630 0.610 ;
        RECT 131.450 0.275 131.590 0.610 ;
        RECT 132.410 0.275 132.550 0.610 ;
        RECT 133.370 0.275 133.510 0.610 ;
        RECT 134.330 0.275 134.470 0.610 ;
        RECT 135.290 0.275 135.430 0.610 ;
        RECT 136.250 0.275 136.390 0.610 ;
        RECT 137.210 0.275 137.350 0.610 ;
        RECT 138.170 0.275 138.310 0.610 ;
        RECT 139.130 0.275 139.270 0.610 ;
        RECT 140.090 0.275 140.230 0.610 ;
        RECT 141.050 0.275 141.190 0.610 ;
        RECT 142.010 0.275 142.150 0.610 ;
        RECT 142.970 0.275 143.110 0.610 ;
        RECT 143.930 0.275 144.070 0.610 ;
        RECT 144.890 0.275 145.030 0.610 ;
        RECT 145.850 0.275 145.990 0.610 ;
        RECT 146.810 0.275 146.950 0.610 ;
        RECT 147.770 0.275 147.910 0.610 ;
        RECT 148.730 0.275 148.870 0.610 ;
        RECT 149.690 0.275 149.830 0.610 ;
        RECT 150.650 0.275 150.790 0.610 ;
        RECT 151.610 0.275 184.425 0.610 ;
      LAYER Metal3 ;
        RECT 0.335 429.650 184.465 430.605 ;
        RECT 0.610 428.830 184.190 429.650 ;
        RECT 0.335 427.970 184.465 428.830 ;
        RECT 0.610 427.150 184.190 427.970 ;
        RECT 0.335 426.290 184.465 427.150 ;
        RECT 0.610 425.470 184.190 426.290 ;
        RECT 0.335 424.610 184.465 425.470 ;
        RECT 0.610 423.790 184.190 424.610 ;
        RECT 0.335 422.930 184.465 423.790 ;
        RECT 0.610 422.110 184.190 422.930 ;
        RECT 0.335 421.250 184.465 422.110 ;
        RECT 0.610 420.430 184.190 421.250 ;
        RECT 0.335 419.570 184.465 420.430 ;
        RECT 0.610 418.750 184.190 419.570 ;
        RECT 0.335 417.890 184.465 418.750 ;
        RECT 0.610 417.070 184.190 417.890 ;
        RECT 0.335 416.210 184.465 417.070 ;
        RECT 0.610 415.390 184.190 416.210 ;
        RECT 0.335 414.530 184.465 415.390 ;
        RECT 0.610 413.710 184.190 414.530 ;
        RECT 0.335 412.850 184.465 413.710 ;
        RECT 0.610 412.030 184.190 412.850 ;
        RECT 0.335 411.170 184.465 412.030 ;
        RECT 0.610 410.350 184.190 411.170 ;
        RECT 0.335 409.490 184.465 410.350 ;
        RECT 0.610 408.670 184.190 409.490 ;
        RECT 0.335 407.810 184.465 408.670 ;
        RECT 0.610 406.990 184.190 407.810 ;
        RECT 0.335 406.130 184.465 406.990 ;
        RECT 0.610 405.310 184.190 406.130 ;
        RECT 0.335 404.450 184.465 405.310 ;
        RECT 0.610 403.630 184.190 404.450 ;
        RECT 0.335 402.770 184.465 403.630 ;
        RECT 0.610 401.950 184.190 402.770 ;
        RECT 0.335 401.090 184.465 401.950 ;
        RECT 0.610 400.270 184.190 401.090 ;
        RECT 0.335 399.410 184.465 400.270 ;
        RECT 0.610 398.590 184.190 399.410 ;
        RECT 0.335 397.730 184.465 398.590 ;
        RECT 0.610 396.910 184.190 397.730 ;
        RECT 0.335 396.050 184.465 396.910 ;
        RECT 0.610 395.230 184.190 396.050 ;
        RECT 0.335 394.370 184.465 395.230 ;
        RECT 0.610 393.550 184.190 394.370 ;
        RECT 0.335 392.690 184.465 393.550 ;
        RECT 0.610 391.870 184.190 392.690 ;
        RECT 0.335 391.010 184.465 391.870 ;
        RECT 0.610 390.190 184.190 391.010 ;
        RECT 0.335 389.330 184.465 390.190 ;
        RECT 0.610 388.510 184.190 389.330 ;
        RECT 0.335 387.650 184.465 388.510 ;
        RECT 0.610 386.830 184.190 387.650 ;
        RECT 0.335 385.970 184.465 386.830 ;
        RECT 0.610 385.150 184.190 385.970 ;
        RECT 0.335 384.290 184.465 385.150 ;
        RECT 0.610 383.470 184.190 384.290 ;
        RECT 0.335 382.610 184.465 383.470 ;
        RECT 0.610 381.790 184.190 382.610 ;
        RECT 0.335 380.930 184.465 381.790 ;
        RECT 0.610 380.110 184.190 380.930 ;
        RECT 0.335 379.250 184.465 380.110 ;
        RECT 0.610 378.430 184.190 379.250 ;
        RECT 0.335 377.570 184.465 378.430 ;
        RECT 0.610 376.750 184.190 377.570 ;
        RECT 0.335 375.890 184.465 376.750 ;
        RECT 0.610 375.070 184.190 375.890 ;
        RECT 0.335 374.210 184.465 375.070 ;
        RECT 0.610 373.390 184.190 374.210 ;
        RECT 0.335 372.530 184.465 373.390 ;
        RECT 0.610 371.710 184.190 372.530 ;
        RECT 0.335 370.850 184.465 371.710 ;
        RECT 0.610 370.030 184.190 370.850 ;
        RECT 0.335 369.170 184.465 370.030 ;
        RECT 0.610 368.350 184.190 369.170 ;
        RECT 0.335 367.490 184.465 368.350 ;
        RECT 0.610 366.670 184.190 367.490 ;
        RECT 0.335 365.810 184.465 366.670 ;
        RECT 0.610 364.990 184.190 365.810 ;
        RECT 0.335 364.130 184.465 364.990 ;
        RECT 0.610 363.310 184.190 364.130 ;
        RECT 0.335 362.450 184.465 363.310 ;
        RECT 0.610 361.630 184.190 362.450 ;
        RECT 0.335 360.770 184.465 361.630 ;
        RECT 0.610 359.950 184.190 360.770 ;
        RECT 0.335 359.090 184.465 359.950 ;
        RECT 0.610 358.270 184.190 359.090 ;
        RECT 0.335 357.410 184.465 358.270 ;
        RECT 0.610 356.590 184.190 357.410 ;
        RECT 0.335 355.730 184.465 356.590 ;
        RECT 0.610 354.910 184.190 355.730 ;
        RECT 0.335 354.050 184.465 354.910 ;
        RECT 0.610 353.230 184.190 354.050 ;
        RECT 0.335 352.370 184.465 353.230 ;
        RECT 0.610 351.550 184.190 352.370 ;
        RECT 0.335 350.690 184.465 351.550 ;
        RECT 0.610 349.870 184.190 350.690 ;
        RECT 0.335 349.010 184.465 349.870 ;
        RECT 0.610 348.190 184.190 349.010 ;
        RECT 0.335 347.330 184.465 348.190 ;
        RECT 0.610 346.510 184.190 347.330 ;
        RECT 0.335 345.650 184.465 346.510 ;
        RECT 0.610 344.830 184.190 345.650 ;
        RECT 0.335 343.970 184.465 344.830 ;
        RECT 0.610 343.150 184.190 343.970 ;
        RECT 0.335 342.290 184.465 343.150 ;
        RECT 0.610 341.470 184.190 342.290 ;
        RECT 0.335 340.610 184.465 341.470 ;
        RECT 0.610 339.790 184.190 340.610 ;
        RECT 0.335 338.930 184.465 339.790 ;
        RECT 0.610 338.110 184.190 338.930 ;
        RECT 0.335 337.250 184.465 338.110 ;
        RECT 0.610 336.430 184.190 337.250 ;
        RECT 0.335 335.570 184.465 336.430 ;
        RECT 0.610 334.750 184.190 335.570 ;
        RECT 0.335 333.890 184.465 334.750 ;
        RECT 0.610 333.070 184.190 333.890 ;
        RECT 0.335 332.210 184.465 333.070 ;
        RECT 0.610 331.390 184.190 332.210 ;
        RECT 0.335 330.530 184.465 331.390 ;
        RECT 0.610 329.710 184.190 330.530 ;
        RECT 0.335 328.850 184.465 329.710 ;
        RECT 0.610 328.030 184.190 328.850 ;
        RECT 0.335 327.170 184.465 328.030 ;
        RECT 0.610 326.350 184.190 327.170 ;
        RECT 0.335 325.490 184.465 326.350 ;
        RECT 0.610 324.670 184.190 325.490 ;
        RECT 0.335 323.810 184.465 324.670 ;
        RECT 0.610 322.990 184.190 323.810 ;
        RECT 0.335 322.130 184.465 322.990 ;
        RECT 0.610 321.310 184.190 322.130 ;
        RECT 0.335 320.450 184.465 321.310 ;
        RECT 0.610 319.630 184.190 320.450 ;
        RECT 0.335 318.770 184.465 319.630 ;
        RECT 0.610 317.950 184.190 318.770 ;
        RECT 0.335 317.090 184.465 317.950 ;
        RECT 0.610 316.270 184.190 317.090 ;
        RECT 0.335 315.410 184.465 316.270 ;
        RECT 0.610 314.590 184.190 315.410 ;
        RECT 0.335 313.730 184.465 314.590 ;
        RECT 0.610 312.910 184.190 313.730 ;
        RECT 0.335 312.050 184.465 312.910 ;
        RECT 0.610 311.230 184.190 312.050 ;
        RECT 0.335 310.370 184.465 311.230 ;
        RECT 0.610 309.550 184.190 310.370 ;
        RECT 0.335 308.690 184.465 309.550 ;
        RECT 0.610 307.870 184.190 308.690 ;
        RECT 0.335 307.010 184.465 307.870 ;
        RECT 0.610 306.190 184.190 307.010 ;
        RECT 0.335 305.330 184.465 306.190 ;
        RECT 0.610 304.510 184.190 305.330 ;
        RECT 0.335 303.650 184.465 304.510 ;
        RECT 0.610 302.830 184.190 303.650 ;
        RECT 0.335 301.970 184.465 302.830 ;
        RECT 0.610 301.150 184.190 301.970 ;
        RECT 0.335 300.290 184.465 301.150 ;
        RECT 0.610 299.470 184.190 300.290 ;
        RECT 0.335 298.610 184.465 299.470 ;
        RECT 0.610 297.790 184.190 298.610 ;
        RECT 0.335 296.930 184.465 297.790 ;
        RECT 0.610 296.110 184.190 296.930 ;
        RECT 0.335 295.250 184.465 296.110 ;
        RECT 0.610 294.430 184.190 295.250 ;
        RECT 0.335 293.570 184.465 294.430 ;
        RECT 0.610 292.750 184.190 293.570 ;
        RECT 0.335 291.890 184.465 292.750 ;
        RECT 0.610 291.070 184.190 291.890 ;
        RECT 0.335 290.210 184.465 291.070 ;
        RECT 0.610 289.390 184.190 290.210 ;
        RECT 0.335 288.530 184.465 289.390 ;
        RECT 0.610 287.710 184.190 288.530 ;
        RECT 0.335 286.850 184.465 287.710 ;
        RECT 0.610 286.030 184.190 286.850 ;
        RECT 0.335 285.170 184.465 286.030 ;
        RECT 0.610 284.350 184.190 285.170 ;
        RECT 0.335 283.490 184.465 284.350 ;
        RECT 0.610 282.670 184.190 283.490 ;
        RECT 0.335 281.810 184.465 282.670 ;
        RECT 0.610 280.990 184.190 281.810 ;
        RECT 0.335 280.130 184.465 280.990 ;
        RECT 0.610 279.310 184.190 280.130 ;
        RECT 0.335 278.450 184.465 279.310 ;
        RECT 0.610 277.630 184.190 278.450 ;
        RECT 0.335 276.770 184.465 277.630 ;
        RECT 0.610 275.950 184.190 276.770 ;
        RECT 0.335 275.090 184.465 275.950 ;
        RECT 0.610 274.270 184.190 275.090 ;
        RECT 0.335 273.410 184.465 274.270 ;
        RECT 0.610 272.590 184.190 273.410 ;
        RECT 0.335 271.730 184.465 272.590 ;
        RECT 0.610 270.910 184.190 271.730 ;
        RECT 0.335 270.050 184.465 270.910 ;
        RECT 0.610 269.230 184.190 270.050 ;
        RECT 0.335 268.370 184.465 269.230 ;
        RECT 0.610 267.550 184.190 268.370 ;
        RECT 0.335 266.690 184.465 267.550 ;
        RECT 0.610 265.870 184.190 266.690 ;
        RECT 0.335 265.010 184.465 265.870 ;
        RECT 0.610 264.190 184.190 265.010 ;
        RECT 0.335 263.330 184.465 264.190 ;
        RECT 0.610 262.510 184.190 263.330 ;
        RECT 0.335 261.650 184.465 262.510 ;
        RECT 0.610 260.830 184.190 261.650 ;
        RECT 0.335 259.970 184.465 260.830 ;
        RECT 0.610 259.150 184.190 259.970 ;
        RECT 0.335 258.290 184.465 259.150 ;
        RECT 0.610 257.470 184.190 258.290 ;
        RECT 0.335 256.610 184.465 257.470 ;
        RECT 0.610 255.790 184.190 256.610 ;
        RECT 0.335 254.930 184.465 255.790 ;
        RECT 0.610 254.110 184.190 254.930 ;
        RECT 0.335 253.250 184.465 254.110 ;
        RECT 0.610 252.430 184.190 253.250 ;
        RECT 0.335 251.570 184.465 252.430 ;
        RECT 0.610 250.750 184.190 251.570 ;
        RECT 0.335 249.890 184.465 250.750 ;
        RECT 0.610 249.070 184.190 249.890 ;
        RECT 0.335 248.210 184.465 249.070 ;
        RECT 0.610 247.390 184.190 248.210 ;
        RECT 0.335 246.530 184.465 247.390 ;
        RECT 0.610 245.710 184.190 246.530 ;
        RECT 0.335 244.850 184.465 245.710 ;
        RECT 0.610 244.030 184.190 244.850 ;
        RECT 0.335 243.170 184.465 244.030 ;
        RECT 0.610 242.350 184.190 243.170 ;
        RECT 0.335 241.490 184.465 242.350 ;
        RECT 0.610 240.670 184.190 241.490 ;
        RECT 0.335 239.810 184.465 240.670 ;
        RECT 0.610 238.990 184.190 239.810 ;
        RECT 0.335 238.130 184.465 238.990 ;
        RECT 0.610 237.310 184.190 238.130 ;
        RECT 0.335 236.450 184.465 237.310 ;
        RECT 0.610 235.630 184.190 236.450 ;
        RECT 0.335 234.770 184.465 235.630 ;
        RECT 0.610 233.950 184.190 234.770 ;
        RECT 0.335 233.090 184.465 233.950 ;
        RECT 0.610 232.270 184.190 233.090 ;
        RECT 0.335 231.410 184.465 232.270 ;
        RECT 0.610 230.590 184.190 231.410 ;
        RECT 0.335 229.730 184.465 230.590 ;
        RECT 0.610 228.910 184.190 229.730 ;
        RECT 0.335 228.050 184.465 228.910 ;
        RECT 0.610 227.230 184.190 228.050 ;
        RECT 0.335 226.370 184.465 227.230 ;
        RECT 0.610 225.550 184.190 226.370 ;
        RECT 0.335 224.690 184.465 225.550 ;
        RECT 0.610 223.870 184.190 224.690 ;
        RECT 0.335 223.010 184.465 223.870 ;
        RECT 0.610 222.190 184.190 223.010 ;
        RECT 0.335 221.330 184.465 222.190 ;
        RECT 0.610 220.510 184.190 221.330 ;
        RECT 0.335 219.650 184.465 220.510 ;
        RECT 0.610 218.830 184.190 219.650 ;
        RECT 0.335 217.970 184.465 218.830 ;
        RECT 0.610 217.150 184.190 217.970 ;
        RECT 0.335 216.290 184.465 217.150 ;
        RECT 0.610 215.470 184.190 216.290 ;
        RECT 0.335 214.190 184.465 215.470 ;
        RECT 0.610 213.370 184.190 214.190 ;
        RECT 0.335 212.510 184.465 213.370 ;
        RECT 0.610 211.690 184.190 212.510 ;
        RECT 0.335 210.830 184.465 211.690 ;
        RECT 0.610 210.010 184.190 210.830 ;
        RECT 0.335 209.150 184.465 210.010 ;
        RECT 0.610 208.330 184.190 209.150 ;
        RECT 0.335 207.470 184.465 208.330 ;
        RECT 0.610 206.650 184.190 207.470 ;
        RECT 0.335 205.790 184.465 206.650 ;
        RECT 0.610 204.970 184.190 205.790 ;
        RECT 0.335 204.110 184.465 204.970 ;
        RECT 0.610 203.290 184.190 204.110 ;
        RECT 0.335 202.430 184.465 203.290 ;
        RECT 0.610 201.610 184.190 202.430 ;
        RECT 0.335 200.750 184.465 201.610 ;
        RECT 0.610 199.930 184.190 200.750 ;
        RECT 0.335 199.070 184.465 199.930 ;
        RECT 0.610 198.250 184.190 199.070 ;
        RECT 0.335 197.390 184.465 198.250 ;
        RECT 0.610 196.570 184.190 197.390 ;
        RECT 0.335 195.710 184.465 196.570 ;
        RECT 0.610 194.890 184.190 195.710 ;
        RECT 0.335 194.030 184.465 194.890 ;
        RECT 0.610 193.210 184.190 194.030 ;
        RECT 0.335 192.350 184.465 193.210 ;
        RECT 0.610 191.530 184.190 192.350 ;
        RECT 0.335 190.670 184.465 191.530 ;
        RECT 0.610 189.850 184.190 190.670 ;
        RECT 0.335 188.990 184.465 189.850 ;
        RECT 0.610 188.170 184.190 188.990 ;
        RECT 0.335 187.310 184.465 188.170 ;
        RECT 0.610 186.490 184.190 187.310 ;
        RECT 0.335 185.630 184.465 186.490 ;
        RECT 0.610 184.810 184.190 185.630 ;
        RECT 0.335 183.950 184.465 184.810 ;
        RECT 0.610 183.130 184.190 183.950 ;
        RECT 0.335 182.270 184.465 183.130 ;
        RECT 0.610 181.450 184.190 182.270 ;
        RECT 0.335 180.590 184.465 181.450 ;
        RECT 0.610 179.770 184.190 180.590 ;
        RECT 0.335 178.910 184.465 179.770 ;
        RECT 0.610 178.090 184.190 178.910 ;
        RECT 0.335 177.230 184.465 178.090 ;
        RECT 0.610 176.410 184.190 177.230 ;
        RECT 0.335 175.550 184.465 176.410 ;
        RECT 0.610 174.730 184.190 175.550 ;
        RECT 0.335 173.870 184.465 174.730 ;
        RECT 0.610 173.050 184.190 173.870 ;
        RECT 0.335 172.190 184.465 173.050 ;
        RECT 0.610 171.370 184.190 172.190 ;
        RECT 0.335 170.510 184.465 171.370 ;
        RECT 0.610 169.690 184.190 170.510 ;
        RECT 0.335 168.830 184.465 169.690 ;
        RECT 0.610 168.010 184.190 168.830 ;
        RECT 0.335 167.150 184.465 168.010 ;
        RECT 0.610 166.330 184.190 167.150 ;
        RECT 0.335 165.470 184.465 166.330 ;
        RECT 0.610 164.650 184.190 165.470 ;
        RECT 0.335 163.790 184.465 164.650 ;
        RECT 0.610 162.970 184.190 163.790 ;
        RECT 0.335 162.110 184.465 162.970 ;
        RECT 0.610 161.290 184.190 162.110 ;
        RECT 0.335 160.430 184.465 161.290 ;
        RECT 0.610 159.610 184.190 160.430 ;
        RECT 0.335 158.750 184.465 159.610 ;
        RECT 0.610 157.930 184.190 158.750 ;
        RECT 0.335 157.070 184.465 157.930 ;
        RECT 0.610 156.250 184.190 157.070 ;
        RECT 0.335 155.390 184.465 156.250 ;
        RECT 0.610 154.570 184.190 155.390 ;
        RECT 0.335 153.710 184.465 154.570 ;
        RECT 0.610 152.890 184.190 153.710 ;
        RECT 0.335 152.030 184.465 152.890 ;
        RECT 0.610 151.210 184.190 152.030 ;
        RECT 0.335 150.350 184.465 151.210 ;
        RECT 0.610 149.530 184.190 150.350 ;
        RECT 0.335 148.670 184.465 149.530 ;
        RECT 0.610 147.850 184.190 148.670 ;
        RECT 0.335 146.990 184.465 147.850 ;
        RECT 0.610 146.170 184.190 146.990 ;
        RECT 0.335 145.310 184.465 146.170 ;
        RECT 0.610 144.490 184.190 145.310 ;
        RECT 0.335 143.630 184.465 144.490 ;
        RECT 0.610 142.810 184.190 143.630 ;
        RECT 0.335 141.950 184.465 142.810 ;
        RECT 0.610 141.130 184.190 141.950 ;
        RECT 0.335 140.270 184.465 141.130 ;
        RECT 0.610 139.450 184.190 140.270 ;
        RECT 0.335 138.590 184.465 139.450 ;
        RECT 0.610 137.770 184.190 138.590 ;
        RECT 0.335 136.910 184.465 137.770 ;
        RECT 0.610 136.090 184.190 136.910 ;
        RECT 0.335 135.230 184.465 136.090 ;
        RECT 0.610 134.410 184.190 135.230 ;
        RECT 0.335 133.550 184.465 134.410 ;
        RECT 0.610 132.730 184.190 133.550 ;
        RECT 0.335 131.870 184.465 132.730 ;
        RECT 0.610 131.050 184.190 131.870 ;
        RECT 0.335 130.190 184.465 131.050 ;
        RECT 0.610 129.370 184.190 130.190 ;
        RECT 0.335 128.510 184.465 129.370 ;
        RECT 0.610 127.690 184.190 128.510 ;
        RECT 0.335 126.830 184.465 127.690 ;
        RECT 0.610 126.010 184.190 126.830 ;
        RECT 0.335 125.150 184.465 126.010 ;
        RECT 0.610 124.330 184.190 125.150 ;
        RECT 0.335 123.470 184.465 124.330 ;
        RECT 0.610 122.650 184.190 123.470 ;
        RECT 0.335 121.790 184.465 122.650 ;
        RECT 0.610 120.970 184.190 121.790 ;
        RECT 0.335 120.110 184.465 120.970 ;
        RECT 0.610 119.290 184.190 120.110 ;
        RECT 0.335 118.430 184.465 119.290 ;
        RECT 0.610 117.610 184.190 118.430 ;
        RECT 0.335 116.750 184.465 117.610 ;
        RECT 0.610 115.930 184.190 116.750 ;
        RECT 0.335 115.070 184.465 115.930 ;
        RECT 0.610 114.250 184.190 115.070 ;
        RECT 0.335 113.390 184.465 114.250 ;
        RECT 0.610 112.570 184.190 113.390 ;
        RECT 0.335 111.710 184.465 112.570 ;
        RECT 0.610 110.890 184.190 111.710 ;
        RECT 0.335 110.030 184.465 110.890 ;
        RECT 0.610 109.210 184.190 110.030 ;
        RECT 0.335 108.350 184.465 109.210 ;
        RECT 0.610 107.530 184.190 108.350 ;
        RECT 0.335 106.670 184.465 107.530 ;
        RECT 0.610 105.850 184.190 106.670 ;
        RECT 0.335 104.990 184.465 105.850 ;
        RECT 0.610 104.170 184.190 104.990 ;
        RECT 0.335 103.310 184.465 104.170 ;
        RECT 0.610 102.490 184.190 103.310 ;
        RECT 0.335 101.630 184.465 102.490 ;
        RECT 0.610 100.810 184.190 101.630 ;
        RECT 0.335 99.950 184.465 100.810 ;
        RECT 0.610 99.130 184.190 99.950 ;
        RECT 0.335 98.270 184.465 99.130 ;
        RECT 0.610 97.450 184.190 98.270 ;
        RECT 0.335 96.590 184.465 97.450 ;
        RECT 0.610 95.770 184.190 96.590 ;
        RECT 0.335 94.910 184.465 95.770 ;
        RECT 0.610 94.090 184.190 94.910 ;
        RECT 0.335 93.230 184.465 94.090 ;
        RECT 0.610 92.410 184.190 93.230 ;
        RECT 0.335 91.550 184.465 92.410 ;
        RECT 0.610 90.730 184.190 91.550 ;
        RECT 0.335 89.870 184.465 90.730 ;
        RECT 0.610 89.050 184.190 89.870 ;
        RECT 0.335 88.190 184.465 89.050 ;
        RECT 0.610 87.370 184.190 88.190 ;
        RECT 0.335 86.510 184.465 87.370 ;
        RECT 0.610 85.690 184.190 86.510 ;
        RECT 0.335 84.830 184.465 85.690 ;
        RECT 0.610 84.010 184.190 84.830 ;
        RECT 0.335 83.150 184.465 84.010 ;
        RECT 0.610 82.330 184.190 83.150 ;
        RECT 0.335 81.470 184.465 82.330 ;
        RECT 0.610 80.650 184.190 81.470 ;
        RECT 0.335 79.790 184.465 80.650 ;
        RECT 0.610 78.970 184.190 79.790 ;
        RECT 0.335 78.110 184.465 78.970 ;
        RECT 0.610 77.290 184.190 78.110 ;
        RECT 0.335 76.430 184.465 77.290 ;
        RECT 0.610 75.610 184.190 76.430 ;
        RECT 0.335 74.750 184.465 75.610 ;
        RECT 0.610 73.930 184.190 74.750 ;
        RECT 0.335 73.070 184.465 73.930 ;
        RECT 0.610 72.250 184.190 73.070 ;
        RECT 0.335 71.390 184.465 72.250 ;
        RECT 0.610 70.570 184.190 71.390 ;
        RECT 0.335 69.710 184.465 70.570 ;
        RECT 0.610 68.890 184.190 69.710 ;
        RECT 0.335 68.030 184.465 68.890 ;
        RECT 0.610 67.210 184.190 68.030 ;
        RECT 0.335 66.350 184.465 67.210 ;
        RECT 0.610 65.530 184.190 66.350 ;
        RECT 0.335 64.670 184.465 65.530 ;
        RECT 0.610 63.850 184.190 64.670 ;
        RECT 0.335 62.990 184.465 63.850 ;
        RECT 0.610 62.170 184.190 62.990 ;
        RECT 0.335 61.310 184.465 62.170 ;
        RECT 0.610 60.490 184.190 61.310 ;
        RECT 0.335 59.630 184.465 60.490 ;
        RECT 0.610 58.810 184.190 59.630 ;
        RECT 0.335 57.950 184.465 58.810 ;
        RECT 0.610 57.130 184.190 57.950 ;
        RECT 0.335 56.270 184.465 57.130 ;
        RECT 0.610 55.450 184.190 56.270 ;
        RECT 0.335 54.590 184.465 55.450 ;
        RECT 0.610 53.770 184.190 54.590 ;
        RECT 0.335 52.910 184.465 53.770 ;
        RECT 0.610 52.090 184.190 52.910 ;
        RECT 0.335 51.230 184.465 52.090 ;
        RECT 0.610 50.410 184.190 51.230 ;
        RECT 0.335 49.550 184.465 50.410 ;
        RECT 0.610 48.730 184.190 49.550 ;
        RECT 0.335 47.870 184.465 48.730 ;
        RECT 0.610 47.050 184.190 47.870 ;
        RECT 0.335 46.190 184.465 47.050 ;
        RECT 0.610 45.370 184.190 46.190 ;
        RECT 0.335 44.510 184.465 45.370 ;
        RECT 0.610 43.690 184.190 44.510 ;
        RECT 0.335 42.830 184.465 43.690 ;
        RECT 0.610 42.010 184.190 42.830 ;
        RECT 0.335 41.150 184.465 42.010 ;
        RECT 0.610 40.330 184.190 41.150 ;
        RECT 0.335 39.470 184.465 40.330 ;
        RECT 0.610 38.650 184.190 39.470 ;
        RECT 0.335 37.790 184.465 38.650 ;
        RECT 0.610 36.970 184.190 37.790 ;
        RECT 0.335 36.110 184.465 36.970 ;
        RECT 0.610 35.290 184.190 36.110 ;
        RECT 0.335 34.430 184.465 35.290 ;
        RECT 0.610 33.610 184.190 34.430 ;
        RECT 0.335 32.750 184.465 33.610 ;
        RECT 0.610 31.930 184.190 32.750 ;
        RECT 0.335 31.070 184.465 31.930 ;
        RECT 0.610 30.250 184.190 31.070 ;
        RECT 0.335 29.390 184.465 30.250 ;
        RECT 0.610 28.570 184.190 29.390 ;
        RECT 0.335 27.710 184.465 28.570 ;
        RECT 0.610 26.890 184.190 27.710 ;
        RECT 0.335 26.030 184.465 26.890 ;
        RECT 0.610 25.210 184.190 26.030 ;
        RECT 0.335 24.350 184.465 25.210 ;
        RECT 0.610 23.530 184.190 24.350 ;
        RECT 0.335 22.670 184.465 23.530 ;
        RECT 0.610 21.850 184.190 22.670 ;
        RECT 0.335 20.990 184.465 21.850 ;
        RECT 0.610 20.170 184.190 20.990 ;
        RECT 0.335 19.310 184.465 20.170 ;
        RECT 0.610 18.490 184.190 19.310 ;
        RECT 0.335 17.630 184.465 18.490 ;
        RECT 0.610 16.810 184.190 17.630 ;
        RECT 0.335 15.950 184.465 16.810 ;
        RECT 0.610 15.130 184.190 15.950 ;
        RECT 0.335 14.270 184.465 15.130 ;
        RECT 0.610 13.450 184.190 14.270 ;
        RECT 0.335 12.590 184.465 13.450 ;
        RECT 0.610 11.770 184.190 12.590 ;
        RECT 0.335 10.910 184.465 11.770 ;
        RECT 0.610 10.090 184.190 10.910 ;
        RECT 0.335 9.230 184.465 10.090 ;
        RECT 0.610 8.410 184.190 9.230 ;
        RECT 0.335 7.550 184.465 8.410 ;
        RECT 0.610 6.730 184.190 7.550 ;
        RECT 0.335 5.870 184.465 6.730 ;
        RECT 0.610 5.050 184.190 5.870 ;
        RECT 0.335 4.190 184.465 5.050 ;
        RECT 0.610 3.370 184.190 4.190 ;
        RECT 0.335 2.510 184.465 3.370 ;
        RECT 0.610 1.690 184.190 2.510 ;
        RECT 0.335 0.830 184.465 1.690 ;
        RECT 0.610 0.315 184.190 0.830 ;
      LAYER Metal4 ;
        RECT 0.375 0.270 184.425 430.645 ;
      LAYER Metal5 ;
        RECT 0.335 0.320 184.465 430.180 ;
      LAYER TopMetal1 ;
        RECT 0.820 2.540 13.740 425.860 ;
        RECT 19.220 2.540 19.940 425.860 ;
        RECT 25.420 2.540 89.340 425.860 ;
        RECT 94.820 2.540 95.540 425.860 ;
        RECT 101.020 2.540 164.940 425.860 ;
        RECT 170.420 2.540 171.140 425.860 ;
        RECT 176.620 2.540 182.580 425.860 ;
  END
END DSP
END LIBRARY

